VERSION 5.7 ;
BUSBITCHARS "[]" ;
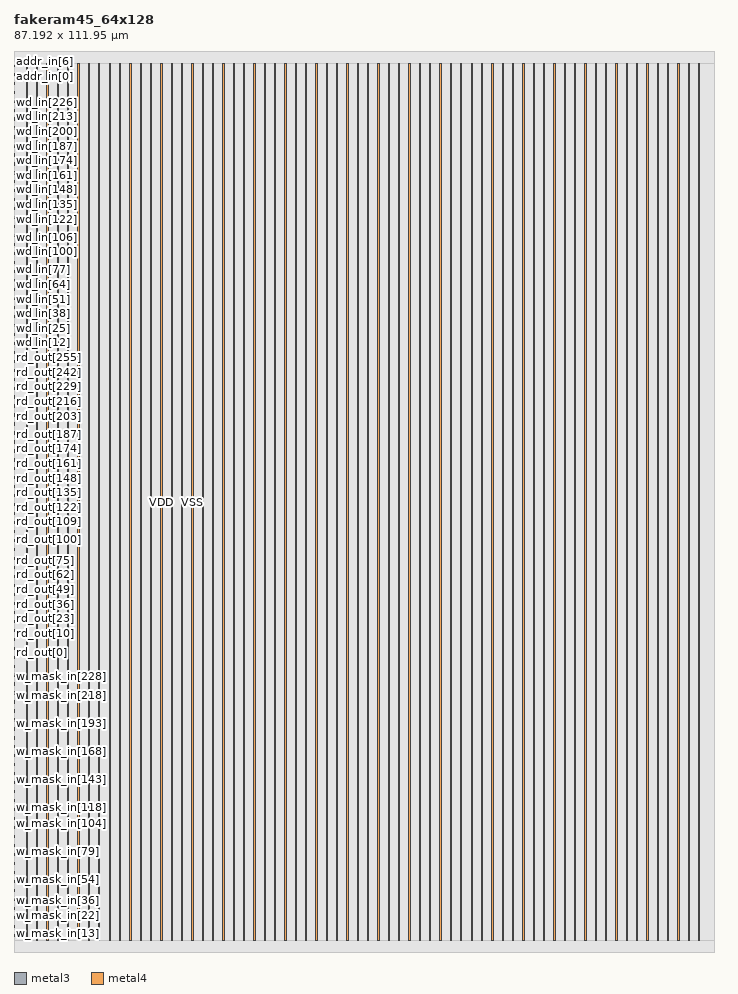
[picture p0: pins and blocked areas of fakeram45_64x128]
MACRO fakeram45_64x128
  FOREIGN fakeram45_64x128 0 0 ;
  SYMMETRY X Y R90 ;
  SIZE 87.192 BY 111.950 ;
  CLASS BLOCK ;
  PIN w_mask_in[0]
    DIRECTION INPUT ;
    USE SIGNAL ;
    SHAPE ABUTMENT ;
    PORT
      LAYER metal3 ;
      RECT 0.000 1.400 0.040 1.435 ;
    END
  END w_mask_in[0]
  PIN w_mask_in[1]
    DIRECTION INPUT ;
    USE SIGNAL ;
    SHAPE ABUTMENT ;
    PORT
      LAYER metal3 ;
      RECT 0.000 1.540 0.040 1.575 ;
    END
  END w_mask_in[1]
  PIN w_mask_in[2]
    DIRECTION INPUT ;
    USE SIGNAL ;
    SHAPE ABUTMENT ;
    PORT
      LAYER metal3 ;
      RECT 0.000 1.680 0.040 1.715 ;
    END
  END w_mask_in[2]
  PIN w_mask_in[3]
    DIRECTION INPUT ;
    USE SIGNAL ;
    SHAPE ABUTMENT ;
    PORT
      LAYER metal3 ;
      RECT 0.000 1.820 0.040 1.855 ;
    END
  END w_mask_in[3]
  PIN w_mask_in[4]
    DIRECTION INPUT ;
    USE SIGNAL ;
    SHAPE ABUTMENT ;
    PORT
      LAYER metal3 ;
      RECT 0.000 1.960 0.040 1.995 ;
    END
  END w_mask_in[4]
  PIN w_mask_in[5]
    DIRECTION INPUT ;
    USE SIGNAL ;
    SHAPE ABUTMENT ;
    PORT
      LAYER metal3 ;
      RECT 0.000 2.100 0.040 2.135 ;
    END
  END w_mask_in[5]
  PIN w_mask_in[6]
    DIRECTION INPUT ;
    USE SIGNAL ;
    SHAPE ABUTMENT ;
    PORT
      LAYER metal3 ;
      RECT 0.000 2.240 0.040 2.275 ;
    END
  END w_mask_in[6]
  PIN w_mask_in[7]
    DIRECTION INPUT ;
    USE SIGNAL ;
    SHAPE ABUTMENT ;
    PORT
      LAYER metal3 ;
      RECT 0.000 2.380 0.040 2.415 ;
    END
  END w_mask_in[7]
  PIN w_mask_in[8]
    DIRECTION INPUT ;
    USE SIGNAL ;
    SHAPE ABUTMENT ;
    PORT
      LAYER metal3 ;
      RECT 0.000 2.520 0.040 2.555 ;
    END
  END w_mask_in[8]
  PIN w_mask_in[9]
    DIRECTION INPUT ;
    USE SIGNAL ;
    SHAPE ABUTMENT ;
    PORT
      LAYER metal3 ;
      RECT 0.000 2.660 0.040 2.695 ;
    END
  END w_mask_in[9]
  PIN w_mask_in[10]
    DIRECTION INPUT ;
    USE SIGNAL ;
    SHAPE ABUTMENT ;
    PORT
      LAYER metal3 ;
      RECT 0.000 2.800 0.040 2.835 ;
    END
  END w_mask_in[10]
  PIN w_mask_in[11]
    DIRECTION INPUT ;
    USE SIGNAL ;
    SHAPE ABUTMENT ;
    PORT
      LAYER metal3 ;
      RECT 0.000 2.940 0.040 2.975 ;
    END
  END w_mask_in[11]
  PIN w_mask_in[12]
    DIRECTION INPUT ;
    USE SIGNAL ;
    SHAPE ABUTMENT ;
    PORT
      LAYER metal3 ;
      RECT 0.000 3.080 0.040 3.115 ;
    END
  END w_mask_in[12]
  PIN w_mask_in[13]
    DIRECTION INPUT ;
    USE SIGNAL ;
    SHAPE ABUTMENT ;
    PORT
      LAYER metal3 ;
      RECT 0.000 3.220 0.040 3.255 ;
    END
  END w_mask_in[13]
  PIN w_mask_in[14]
    DIRECTION INPUT ;
    USE SIGNAL ;
    SHAPE ABUTMENT ;
    PORT
      LAYER metal3 ;
      RECT 0.000 3.360 0.040 3.395 ;
    END
  END w_mask_in[14]
  PIN w_mask_in[15]
    DIRECTION INPUT ;
    USE SIGNAL ;
    SHAPE ABUTMENT ;
    PORT
      LAYER metal3 ;
      RECT 0.000 3.500 0.040 3.535 ;
    END
  END w_mask_in[15]
  PIN w_mask_in[16]
    DIRECTION INPUT ;
    USE SIGNAL ;
    SHAPE ABUTMENT ;
    PORT
      LAYER metal3 ;
      RECT 0.000 3.640 0.040 3.675 ;
    END
  END w_mask_in[16]
  PIN w_mask_in[17]
    DIRECTION INPUT ;
    USE SIGNAL ;
    SHAPE ABUTMENT ;
    PORT
      LAYER metal3 ;
      RECT 0.000 3.780 0.040 3.815 ;
    END
  END w_mask_in[17]
  PIN w_mask_in[18]
    DIRECTION INPUT ;
    USE SIGNAL ;
    SHAPE ABUTMENT ;
    PORT
      LAYER metal3 ;
      RECT 0.000 3.920 0.040 3.955 ;
    END
  END w_mask_in[18]
  PIN w_mask_in[19]
    DIRECTION INPUT ;
    USE SIGNAL ;
    SHAPE ABUTMENT ;
    PORT
      LAYER metal3 ;
      RECT 0.000 4.060 0.040 4.095 ;
    END
  END w_mask_in[19]
  PIN w_mask_in[20]
    DIRECTION INPUT ;
    USE SIGNAL ;
    SHAPE ABUTMENT ;
    PORT
      LAYER metal3 ;
      RECT 0.000 4.200 0.040 4.235 ;
    END
  END w_mask_in[20]
  PIN w_mask_in[21]
    DIRECTION INPUT ;
    USE SIGNAL ;
    SHAPE ABUTMENT ;
    PORT
      LAYER metal3 ;
      RECT 0.000 4.340 0.040 4.375 ;
    END
  END w_mask_in[21]
  PIN w_mask_in[22]
    DIRECTION INPUT ;
    USE SIGNAL ;
    SHAPE ABUTMENT ;
    PORT
      LAYER metal3 ;
      RECT 0.000 4.480 0.040 4.515 ;
    END
  END w_mask_in[22]
  PIN w_mask_in[23]
    DIRECTION INPUT ;
    USE SIGNAL ;
    SHAPE ABUTMENT ;
    PORT
      LAYER metal3 ;
      RECT 0.000 4.620 0.040 4.655 ;
    END
  END w_mask_in[23]
  PIN w_mask_in[24]
    DIRECTION INPUT ;
    USE SIGNAL ;
    SHAPE ABUTMENT ;
    PORT
      LAYER metal3 ;
      RECT 0.000 4.760 0.040 4.795 ;
    END
  END w_mask_in[24]
  PIN w_mask_in[25]
    DIRECTION INPUT ;
    USE SIGNAL ;
    SHAPE ABUTMENT ;
    PORT
      LAYER metal3 ;
      RECT 0.000 4.900 0.040 4.935 ;
    END
  END w_mask_in[25]
  PIN w_mask_in[26]
    DIRECTION INPUT ;
    USE SIGNAL ;
    SHAPE ABUTMENT ;
    PORT
      LAYER metal3 ;
      RECT 0.000 5.040 0.040 5.075 ;
    END
  END w_mask_in[26]
  PIN w_mask_in[27]
    DIRECTION INPUT ;
    USE SIGNAL ;
    SHAPE ABUTMENT ;
    PORT
      LAYER metal3 ;
      RECT 0.000 5.180 0.040 5.215 ;
    END
  END w_mask_in[27]
  PIN w_mask_in[28]
    DIRECTION INPUT ;
    USE SIGNAL ;
    SHAPE ABUTMENT ;
    PORT
      LAYER metal3 ;
      RECT 0.000 5.320 0.040 5.355 ;
    END
  END w_mask_in[28]
  PIN w_mask_in[29]
    DIRECTION INPUT ;
    USE SIGNAL ;
    SHAPE ABUTMENT ;
    PORT
      LAYER metal3 ;
      RECT 0.000 5.460 0.040 5.495 ;
    END
  END w_mask_in[29]
  PIN w_mask_in[30]
    DIRECTION INPUT ;
    USE SIGNAL ;
    SHAPE ABUTMENT ;
    PORT
      LAYER metal3 ;
      RECT 0.000 5.600 0.040 5.635 ;
    END
  END w_mask_in[30]
  PIN w_mask_in[31]
    DIRECTION INPUT ;
    USE SIGNAL ;
    SHAPE ABUTMENT ;
    PORT
      LAYER metal3 ;
      RECT 0.000 5.740 0.040 5.775 ;
    END
  END w_mask_in[31]
  PIN w_mask_in[32]
    DIRECTION INPUT ;
    USE SIGNAL ;
    SHAPE ABUTMENT ;
    PORT
      LAYER metal3 ;
      RECT 0.000 5.880 0.040 5.915 ;
    END
  END w_mask_in[32]
  PIN w_mask_in[33]
    DIRECTION INPUT ;
    USE SIGNAL ;
    SHAPE ABUTMENT ;
    PORT
      LAYER metal3 ;
      RECT 0.000 6.020 0.040 6.055 ;
    END
  END w_mask_in[33]
  PIN w_mask_in[34]
    DIRECTION INPUT ;
    USE SIGNAL ;
    SHAPE ABUTMENT ;
    PORT
      LAYER metal3 ;
      RECT 0.000 6.160 0.040 6.195 ;
    END
  END w_mask_in[34]
  PIN w_mask_in[35]
    DIRECTION INPUT ;
    USE SIGNAL ;
    SHAPE ABUTMENT ;
    PORT
      LAYER metal3 ;
      RECT 0.000 6.300 0.040 6.335 ;
    END
  END w_mask_in[35]
  PIN w_mask_in[36]
    DIRECTION INPUT ;
    USE SIGNAL ;
    SHAPE ABUTMENT ;
    PORT
      LAYER metal3 ;
      RECT 0.000 6.440 0.040 6.475 ;
    END
  END w_mask_in[36]
  PIN w_mask_in[37]
    DIRECTION INPUT ;
    USE SIGNAL ;
    SHAPE ABUTMENT ;
    PORT
      LAYER metal3 ;
      RECT 0.000 6.580 0.040 6.615 ;
    END
  END w_mask_in[37]
  PIN w_mask_in[38]
    DIRECTION INPUT ;
    USE SIGNAL ;
    SHAPE ABUTMENT ;
    PORT
      LAYER metal3 ;
      RECT 0.000 6.720 0.040 6.755 ;
    END
  END w_mask_in[38]
  PIN w_mask_in[39]
    DIRECTION INPUT ;
    USE SIGNAL ;
    SHAPE ABUTMENT ;
    PORT
      LAYER metal3 ;
      RECT 0.000 6.860 0.040 6.895 ;
    END
  END w_mask_in[39]
  PIN w_mask_in[40]
    DIRECTION INPUT ;
    USE SIGNAL ;
    SHAPE ABUTMENT ;
    PORT
      LAYER metal3 ;
      RECT 0.000 7.000 0.040 7.035 ;
    END
  END w_mask_in[40]
  PIN w_mask_in[41]
    DIRECTION INPUT ;
    USE SIGNAL ;
    SHAPE ABUTMENT ;
    PORT
      LAYER metal3 ;
      RECT 0.000 7.140 0.040 7.175 ;
    END
  END w_mask_in[41]
  PIN w_mask_in[42]
    DIRECTION INPUT ;
    USE SIGNAL ;
    SHAPE ABUTMENT ;
    PORT
      LAYER metal3 ;
      RECT 0.000 7.280 0.040 7.315 ;
    END
  END w_mask_in[42]
  PIN w_mask_in[43]
    DIRECTION INPUT ;
    USE SIGNAL ;
    SHAPE ABUTMENT ;
    PORT
      LAYER metal3 ;
      RECT 0.000 7.420 0.040 7.455 ;
    END
  END w_mask_in[43]
  PIN w_mask_in[44]
    DIRECTION INPUT ;
    USE SIGNAL ;
    SHAPE ABUTMENT ;
    PORT
      LAYER metal3 ;
      RECT 0.000 7.560 0.040 7.595 ;
    END
  END w_mask_in[44]
  PIN w_mask_in[45]
    DIRECTION INPUT ;
    USE SIGNAL ;
    SHAPE ABUTMENT ;
    PORT
      LAYER metal3 ;
      RECT 0.000 7.700 0.040 7.735 ;
    END
  END w_mask_in[45]
  PIN w_mask_in[46]
    DIRECTION INPUT ;
    USE SIGNAL ;
    SHAPE ABUTMENT ;
    PORT
      LAYER metal3 ;
      RECT 0.000 7.840 0.040 7.875 ;
    END
  END w_mask_in[46]
  PIN w_mask_in[47]
    DIRECTION INPUT ;
    USE SIGNAL ;
    SHAPE ABUTMENT ;
    PORT
      LAYER metal3 ;
      RECT 0.000 7.980 0.040 8.015 ;
    END
  END w_mask_in[47]
  PIN w_mask_in[48]
    DIRECTION INPUT ;
    USE SIGNAL ;
    SHAPE ABUTMENT ;
    PORT
      LAYER metal3 ;
      RECT 0.000 8.120 0.040 8.155 ;
    END
  END w_mask_in[48]
  PIN w_mask_in[49]
    DIRECTION INPUT ;
    USE SIGNAL ;
    SHAPE ABUTMENT ;
    PORT
      LAYER metal3 ;
      RECT 0.000 8.260 0.040 8.295 ;
    END
  END w_mask_in[49]
  PIN w_mask_in[50]
    DIRECTION INPUT ;
    USE SIGNAL ;
    SHAPE ABUTMENT ;
    PORT
      LAYER metal3 ;
      RECT 0.000 8.400 0.040 8.435 ;
    END
  END w_mask_in[50]
  PIN w_mask_in[51]
    DIRECTION INPUT ;
    USE SIGNAL ;
    SHAPE ABUTMENT ;
    PORT
      LAYER metal3 ;
      RECT 0.000 8.540 0.040 8.575 ;
    END
  END w_mask_in[51]
  PIN w_mask_in[52]
    DIRECTION INPUT ;
    USE SIGNAL ;
    SHAPE ABUTMENT ;
    PORT
      LAYER metal3 ;
      RECT 0.000 8.680 0.040 8.715 ;
    END
  END w_mask_in[52]
  PIN w_mask_in[53]
    DIRECTION INPUT ;
    USE SIGNAL ;
    SHAPE ABUTMENT ;
    PORT
      LAYER metal3 ;
      RECT 0.000 8.820 0.040 8.855 ;
    END
  END w_mask_in[53]
  PIN w_mask_in[54]
    DIRECTION INPUT ;
    USE SIGNAL ;
    SHAPE ABUTMENT ;
    PORT
      LAYER metal3 ;
      RECT 0.000 8.960 0.040 8.995 ;
    END
  END w_mask_in[54]
  PIN w_mask_in[55]
    DIRECTION INPUT ;
    USE SIGNAL ;
    SHAPE ABUTMENT ;
    PORT
      LAYER metal3 ;
      RECT 0.000 9.100 0.040 9.135 ;
    END
  END w_mask_in[55]
  PIN w_mask_in[56]
    DIRECTION INPUT ;
    USE SIGNAL ;
    SHAPE ABUTMENT ;
    PORT
      LAYER metal3 ;
      RECT 0.000 9.240 0.040 9.275 ;
    END
  END w_mask_in[56]
  PIN w_mask_in[57]
    DIRECTION INPUT ;
    USE SIGNAL ;
    SHAPE ABUTMENT ;
    PORT
      LAYER metal3 ;
      RECT 0.000 9.380 0.040 9.415 ;
    END
  END w_mask_in[57]
  PIN w_mask_in[58]
    DIRECTION INPUT ;
    USE SIGNAL ;
    SHAPE ABUTMENT ;
    PORT
      LAYER metal3 ;
      RECT 0.000 9.520 0.040 9.555 ;
    END
  END w_mask_in[58]
  PIN w_mask_in[59]
    DIRECTION INPUT ;
    USE SIGNAL ;
    SHAPE ABUTMENT ;
    PORT
      LAYER metal3 ;
      RECT 0.000 9.660 0.040 9.695 ;
    END
  END w_mask_in[59]
  PIN w_mask_in[60]
    DIRECTION INPUT ;
    USE SIGNAL ;
    SHAPE ABUTMENT ;
    PORT
      LAYER metal3 ;
      RECT 0.000 9.800 0.040 9.835 ;
    END
  END w_mask_in[60]
  PIN w_mask_in[61]
    DIRECTION INPUT ;
    USE SIGNAL ;
    SHAPE ABUTMENT ;
    PORT
      LAYER metal3 ;
      RECT 0.000 9.940 0.040 9.975 ;
    END
  END w_mask_in[61]
  PIN w_mask_in[62]
    DIRECTION INPUT ;
    USE SIGNAL ;
    SHAPE ABUTMENT ;
    PORT
      LAYER metal3 ;
      RECT 0.000 10.080 0.040 10.115 ;
    END
  END w_mask_in[62]
  PIN w_mask_in[63]
    DIRECTION INPUT ;
    USE SIGNAL ;
    SHAPE ABUTMENT ;
    PORT
      LAYER metal3 ;
      RECT 0.000 10.220 0.040 10.255 ;
    END
  END w_mask_in[63]
  PIN w_mask_in[64]
    DIRECTION INPUT ;
    USE SIGNAL ;
    SHAPE ABUTMENT ;
    PORT
      LAYER metal3 ;
      RECT 0.000 10.360 0.040 10.395 ;
    END
  END w_mask_in[64]
  PIN w_mask_in[65]
    DIRECTION INPUT ;
    USE SIGNAL ;
    SHAPE ABUTMENT ;
    PORT
      LAYER metal3 ;
      RECT 0.000 10.500 0.040 10.535 ;
    END
  END w_mask_in[65]
  PIN w_mask_in[66]
    DIRECTION INPUT ;
    USE SIGNAL ;
    SHAPE ABUTMENT ;
    PORT
      LAYER metal3 ;
      RECT 0.000 10.640 0.040 10.675 ;
    END
  END w_mask_in[66]
  PIN w_mask_in[67]
    DIRECTION INPUT ;
    USE SIGNAL ;
    SHAPE ABUTMENT ;
    PORT
      LAYER metal3 ;
      RECT 0.000 10.780 0.040 10.815 ;
    END
  END w_mask_in[67]
  PIN w_mask_in[68]
    DIRECTION INPUT ;
    USE SIGNAL ;
    SHAPE ABUTMENT ;
    PORT
      LAYER metal3 ;
      RECT 0.000 10.920 0.040 10.955 ;
    END
  END w_mask_in[68]
  PIN w_mask_in[69]
    DIRECTION INPUT ;
    USE SIGNAL ;
    SHAPE ABUTMENT ;
    PORT
      LAYER metal3 ;
      RECT 0.000 11.060 0.040 11.095 ;
    END
  END w_mask_in[69]
  PIN w_mask_in[70]
    DIRECTION INPUT ;
    USE SIGNAL ;
    SHAPE ABUTMENT ;
    PORT
      LAYER metal3 ;
      RECT 0.000 11.200 0.040 11.235 ;
    END
  END w_mask_in[70]
  PIN w_mask_in[71]
    DIRECTION INPUT ;
    USE SIGNAL ;
    SHAPE ABUTMENT ;
    PORT
      LAYER metal3 ;
      RECT 0.000 11.340 0.040 11.375 ;
    END
  END w_mask_in[71]
  PIN w_mask_in[72]
    DIRECTION INPUT ;
    USE SIGNAL ;
    SHAPE ABUTMENT ;
    PORT
      LAYER metal3 ;
      RECT 0.000 11.480 0.040 11.515 ;
    END
  END w_mask_in[72]
  PIN w_mask_in[73]
    DIRECTION INPUT ;
    USE SIGNAL ;
    SHAPE ABUTMENT ;
    PORT
      LAYER metal3 ;
      RECT 0.000 11.620 0.040 11.655 ;
    END
  END w_mask_in[73]
  PIN w_mask_in[74]
    DIRECTION INPUT ;
    USE SIGNAL ;
    SHAPE ABUTMENT ;
    PORT
      LAYER metal3 ;
      RECT 0.000 11.760 0.040 11.795 ;
    END
  END w_mask_in[74]
  PIN w_mask_in[75]
    DIRECTION INPUT ;
    USE SIGNAL ;
    SHAPE ABUTMENT ;
    PORT
      LAYER metal3 ;
      RECT 0.000 11.900 0.040 11.935 ;
    END
  END w_mask_in[75]
  PIN w_mask_in[76]
    DIRECTION INPUT ;
    USE SIGNAL ;
    SHAPE ABUTMENT ;
    PORT
      LAYER metal3 ;
      RECT 0.000 12.040 0.040 12.075 ;
    END
  END w_mask_in[76]
  PIN w_mask_in[77]
    DIRECTION INPUT ;
    USE SIGNAL ;
    SHAPE ABUTMENT ;
    PORT
      LAYER metal3 ;
      RECT 0.000 12.180 0.040 12.215 ;
    END
  END w_mask_in[77]
  PIN w_mask_in[78]
    DIRECTION INPUT ;
    USE SIGNAL ;
    SHAPE ABUTMENT ;
    PORT
      LAYER metal3 ;
      RECT 0.000 12.320 0.040 12.355 ;
    END
  END w_mask_in[78]
  PIN w_mask_in[79]
    DIRECTION INPUT ;
    USE SIGNAL ;
    SHAPE ABUTMENT ;
    PORT
      LAYER metal3 ;
      RECT 0.000 12.460 0.040 12.495 ;
    END
  END w_mask_in[79]
  PIN w_mask_in[80]
    DIRECTION INPUT ;
    USE SIGNAL ;
    SHAPE ABUTMENT ;
    PORT
      LAYER metal3 ;
      RECT 0.000 12.600 0.040 12.635 ;
    END
  END w_mask_in[80]
  PIN w_mask_in[81]
    DIRECTION INPUT ;
    USE SIGNAL ;
    SHAPE ABUTMENT ;
    PORT
      LAYER metal3 ;
      RECT 0.000 12.740 0.040 12.775 ;
    END
  END w_mask_in[81]
  PIN w_mask_in[82]
    DIRECTION INPUT ;
    USE SIGNAL ;
    SHAPE ABUTMENT ;
    PORT
      LAYER metal3 ;
      RECT 0.000 12.880 0.040 12.915 ;
    END
  END w_mask_in[82]
  PIN w_mask_in[83]
    DIRECTION INPUT ;
    USE SIGNAL ;
    SHAPE ABUTMENT ;
    PORT
      LAYER metal3 ;
      RECT 0.000 13.020 0.040 13.055 ;
    END
  END w_mask_in[83]
  PIN w_mask_in[84]
    DIRECTION INPUT ;
    USE SIGNAL ;
    SHAPE ABUTMENT ;
    PORT
      LAYER metal3 ;
      RECT 0.000 13.160 0.040 13.195 ;
    END
  END w_mask_in[84]
  PIN w_mask_in[85]
    DIRECTION INPUT ;
    USE SIGNAL ;
    SHAPE ABUTMENT ;
    PORT
      LAYER metal3 ;
      RECT 0.000 13.300 0.040 13.335 ;
    END
  END w_mask_in[85]
  PIN w_mask_in[86]
    DIRECTION INPUT ;
    USE SIGNAL ;
    SHAPE ABUTMENT ;
    PORT
      LAYER metal3 ;
      RECT 0.000 13.440 0.040 13.475 ;
    END
  END w_mask_in[86]
  PIN w_mask_in[87]
    DIRECTION INPUT ;
    USE SIGNAL ;
    SHAPE ABUTMENT ;
    PORT
      LAYER metal3 ;
      RECT 0.000 13.580 0.040 13.615 ;
    END
  END w_mask_in[87]
  PIN w_mask_in[88]
    DIRECTION INPUT ;
    USE SIGNAL ;
    SHAPE ABUTMENT ;
    PORT
      LAYER metal3 ;
      RECT 0.000 13.720 0.040 13.755 ;
    END
  END w_mask_in[88]
  PIN w_mask_in[89]
    DIRECTION INPUT ;
    USE SIGNAL ;
    SHAPE ABUTMENT ;
    PORT
      LAYER metal3 ;
      RECT 0.000 13.860 0.040 13.895 ;
    END
  END w_mask_in[89]
  PIN w_mask_in[90]
    DIRECTION INPUT ;
    USE SIGNAL ;
    SHAPE ABUTMENT ;
    PORT
      LAYER metal3 ;
      RECT 0.000 14.000 0.040 14.035 ;
    END
  END w_mask_in[90]
  PIN w_mask_in[91]
    DIRECTION INPUT ;
    USE SIGNAL ;
    SHAPE ABUTMENT ;
    PORT
      LAYER metal3 ;
      RECT 0.000 14.140 0.040 14.175 ;
    END
  END w_mask_in[91]
  PIN w_mask_in[92]
    DIRECTION INPUT ;
    USE SIGNAL ;
    SHAPE ABUTMENT ;
    PORT
      LAYER metal3 ;
      RECT 0.000 14.280 0.040 14.315 ;
    END
  END w_mask_in[92]
  PIN w_mask_in[93]
    DIRECTION INPUT ;
    USE SIGNAL ;
    SHAPE ABUTMENT ;
    PORT
      LAYER metal3 ;
      RECT 0.000 14.420 0.040 14.455 ;
    END
  END w_mask_in[93]
  PIN w_mask_in[94]
    DIRECTION INPUT ;
    USE SIGNAL ;
    SHAPE ABUTMENT ;
    PORT
      LAYER metal3 ;
      RECT 0.000 14.560 0.040 14.595 ;
    END
  END w_mask_in[94]
  PIN w_mask_in[95]
    DIRECTION INPUT ;
    USE SIGNAL ;
    SHAPE ABUTMENT ;
    PORT
      LAYER metal3 ;
      RECT 0.000 14.700 0.040 14.735 ;
    END
  END w_mask_in[95]
  PIN w_mask_in[96]
    DIRECTION INPUT ;
    USE SIGNAL ;
    SHAPE ABUTMENT ;
    PORT
      LAYER metal3 ;
      RECT 0.000 14.840 0.040 14.875 ;
    END
  END w_mask_in[96]
  PIN w_mask_in[97]
    DIRECTION INPUT ;
    USE SIGNAL ;
    SHAPE ABUTMENT ;
    PORT
      LAYER metal3 ;
      RECT 0.000 14.980 0.040 15.015 ;
    END
  END w_mask_in[97]
  PIN w_mask_in[98]
    DIRECTION INPUT ;
    USE SIGNAL ;
    SHAPE ABUTMENT ;
    PORT
      LAYER metal3 ;
      RECT 0.000 15.120 0.040 15.155 ;
    END
  END w_mask_in[98]
  PIN w_mask_in[99]
    DIRECTION INPUT ;
    USE SIGNAL ;
    SHAPE ABUTMENT ;
    PORT
      LAYER metal3 ;
      RECT 0.000 15.260 0.040 15.295 ;
    END
  END w_mask_in[99]
  PIN w_mask_in[100]
    DIRECTION INPUT ;
    USE SIGNAL ;
    SHAPE ABUTMENT ;
    PORT
      LAYER metal3 ;
      RECT 0.000 15.400 0.040 15.435 ;
    END
  END w_mask_in[100]
  PIN w_mask_in[101]
    DIRECTION INPUT ;
    USE SIGNAL ;
    SHAPE ABUTMENT ;
    PORT
      LAYER metal3 ;
      RECT 0.000 15.540 0.040 15.575 ;
    END
  END w_mask_in[101]
  PIN w_mask_in[102]
    DIRECTION INPUT ;
    USE SIGNAL ;
    SHAPE ABUTMENT ;
    PORT
      LAYER metal3 ;
      RECT 0.000 15.680 0.040 15.715 ;
    END
  END w_mask_in[102]
  PIN w_mask_in[103]
    DIRECTION INPUT ;
    USE SIGNAL ;
    SHAPE ABUTMENT ;
    PORT
      LAYER metal3 ;
      RECT 0.000 15.820 0.040 15.855 ;
    END
  END w_mask_in[103]
  PIN w_mask_in[104]
    DIRECTION INPUT ;
    USE SIGNAL ;
    SHAPE ABUTMENT ;
    PORT
      LAYER metal3 ;
      RECT 0.000 15.960 0.040 15.995 ;
    END
  END w_mask_in[104]
  PIN w_mask_in[105]
    DIRECTION INPUT ;
    USE SIGNAL ;
    SHAPE ABUTMENT ;
    PORT
      LAYER metal3 ;
      RECT 0.000 16.100 0.040 16.135 ;
    END
  END w_mask_in[105]
  PIN w_mask_in[106]
    DIRECTION INPUT ;
    USE SIGNAL ;
    SHAPE ABUTMENT ;
    PORT
      LAYER metal3 ;
      RECT 0.000 16.240 0.040 16.275 ;
    END
  END w_mask_in[106]
  PIN w_mask_in[107]
    DIRECTION INPUT ;
    USE SIGNAL ;
    SHAPE ABUTMENT ;
    PORT
      LAYER metal3 ;
      RECT 0.000 16.380 0.040 16.415 ;
    END
  END w_mask_in[107]
  PIN w_mask_in[108]
    DIRECTION INPUT ;
    USE SIGNAL ;
    SHAPE ABUTMENT ;
    PORT
      LAYER metal3 ;
      RECT 0.000 16.520 0.040 16.555 ;
    END
  END w_mask_in[108]
  PIN w_mask_in[109]
    DIRECTION INPUT ;
    USE SIGNAL ;
    SHAPE ABUTMENT ;
    PORT
      LAYER metal3 ;
      RECT 0.000 16.660 0.040 16.695 ;
    END
  END w_mask_in[109]
  PIN w_mask_in[110]
    DIRECTION INPUT ;
    USE SIGNAL ;
    SHAPE ABUTMENT ;
    PORT
      LAYER metal3 ;
      RECT 0.000 16.800 0.040 16.835 ;
    END
  END w_mask_in[110]
  PIN w_mask_in[111]
    DIRECTION INPUT ;
    USE SIGNAL ;
    SHAPE ABUTMENT ;
    PORT
      LAYER metal3 ;
      RECT 0.000 16.940 0.040 16.975 ;
    END
  END w_mask_in[111]
  PIN w_mask_in[112]
    DIRECTION INPUT ;
    USE SIGNAL ;
    SHAPE ABUTMENT ;
    PORT
      LAYER metal3 ;
      RECT 0.000 17.080 0.040 17.115 ;
    END
  END w_mask_in[112]
  PIN w_mask_in[113]
    DIRECTION INPUT ;
    USE SIGNAL ;
    SHAPE ABUTMENT ;
    PORT
      LAYER metal3 ;
      RECT 0.000 17.220 0.040 17.255 ;
    END
  END w_mask_in[113]
  PIN w_mask_in[114]
    DIRECTION INPUT ;
    USE SIGNAL ;
    SHAPE ABUTMENT ;
    PORT
      LAYER metal3 ;
      RECT 0.000 17.360 0.040 17.395 ;
    END
  END w_mask_in[114]
  PIN w_mask_in[115]
    DIRECTION INPUT ;
    USE SIGNAL ;
    SHAPE ABUTMENT ;
    PORT
      LAYER metal3 ;
      RECT 0.000 17.500 0.040 17.535 ;
    END
  END w_mask_in[115]
  PIN w_mask_in[116]
    DIRECTION INPUT ;
    USE SIGNAL ;
    SHAPE ABUTMENT ;
    PORT
      LAYER metal3 ;
      RECT 0.000 17.640 0.040 17.675 ;
    END
  END w_mask_in[116]
  PIN w_mask_in[117]
    DIRECTION INPUT ;
    USE SIGNAL ;
    SHAPE ABUTMENT ;
    PORT
      LAYER metal3 ;
      RECT 0.000 17.780 0.040 17.815 ;
    END
  END w_mask_in[117]
  PIN w_mask_in[118]
    DIRECTION INPUT ;
    USE SIGNAL ;
    SHAPE ABUTMENT ;
    PORT
      LAYER metal3 ;
      RECT 0.000 17.920 0.040 17.955 ;
    END
  END w_mask_in[118]
  PIN w_mask_in[119]
    DIRECTION INPUT ;
    USE SIGNAL ;
    SHAPE ABUTMENT ;
    PORT
      LAYER metal3 ;
      RECT 0.000 18.060 0.040 18.095 ;
    END
  END w_mask_in[119]
  PIN w_mask_in[120]
    DIRECTION INPUT ;
    USE SIGNAL ;
    SHAPE ABUTMENT ;
    PORT
      LAYER metal3 ;
      RECT 0.000 18.200 0.040 18.235 ;
    END
  END w_mask_in[120]
  PIN w_mask_in[121]
    DIRECTION INPUT ;
    USE SIGNAL ;
    SHAPE ABUTMENT ;
    PORT
      LAYER metal3 ;
      RECT 0.000 18.340 0.040 18.375 ;
    END
  END w_mask_in[121]
  PIN w_mask_in[122]
    DIRECTION INPUT ;
    USE SIGNAL ;
    SHAPE ABUTMENT ;
    PORT
      LAYER metal3 ;
      RECT 0.000 18.480 0.040 18.515 ;
    END
  END w_mask_in[122]
  PIN w_mask_in[123]
    DIRECTION INPUT ;
    USE SIGNAL ;
    SHAPE ABUTMENT ;
    PORT
      LAYER metal3 ;
      RECT 0.000 18.620 0.040 18.655 ;
    END
  END w_mask_in[123]
  PIN w_mask_in[124]
    DIRECTION INPUT ;
    USE SIGNAL ;
    SHAPE ABUTMENT ;
    PORT
      LAYER metal3 ;
      RECT 0.000 18.760 0.040 18.795 ;
    END
  END w_mask_in[124]
  PIN w_mask_in[125]
    DIRECTION INPUT ;
    USE SIGNAL ;
    SHAPE ABUTMENT ;
    PORT
      LAYER metal3 ;
      RECT 0.000 18.900 0.040 18.935 ;
    END
  END w_mask_in[125]
  PIN w_mask_in[126]
    DIRECTION INPUT ;
    USE SIGNAL ;
    SHAPE ABUTMENT ;
    PORT
      LAYER metal3 ;
      RECT 0.000 19.040 0.040 19.075 ;
    END
  END w_mask_in[126]
  PIN w_mask_in[127]
    DIRECTION INPUT ;
    USE SIGNAL ;
    SHAPE ABUTMENT ;
    PORT
      LAYER metal3 ;
      RECT 0.000 19.180 0.040 19.215 ;
    END
  END w_mask_in[127]
  PIN w_mask_in[128]
    DIRECTION INPUT ;
    USE SIGNAL ;
    SHAPE ABUTMENT ;
    PORT
      LAYER metal3 ;
      RECT 0.000 19.320 0.040 19.355 ;
    END
  END w_mask_in[128]
  PIN w_mask_in[129]
    DIRECTION INPUT ;
    USE SIGNAL ;
    SHAPE ABUTMENT ;
    PORT
      LAYER metal3 ;
      RECT 0.000 19.460 0.040 19.495 ;
    END
  END w_mask_in[129]
  PIN w_mask_in[130]
    DIRECTION INPUT ;
    USE SIGNAL ;
    SHAPE ABUTMENT ;
    PORT
      LAYER metal3 ;
      RECT 0.000 19.600 0.040 19.635 ;
    END
  END w_mask_in[130]
  PIN w_mask_in[131]
    DIRECTION INPUT ;
    USE SIGNAL ;
    SHAPE ABUTMENT ;
    PORT
      LAYER metal3 ;
      RECT 0.000 19.740 0.040 19.775 ;
    END
  END w_mask_in[131]
  PIN w_mask_in[132]
    DIRECTION INPUT ;
    USE SIGNAL ;
    SHAPE ABUTMENT ;
    PORT
      LAYER metal3 ;
      RECT 0.000 19.880 0.040 19.915 ;
    END
  END w_mask_in[132]
  PIN w_mask_in[133]
    DIRECTION INPUT ;
    USE SIGNAL ;
    SHAPE ABUTMENT ;
    PORT
      LAYER metal3 ;
      RECT 0.000 20.020 0.040 20.055 ;
    END
  END w_mask_in[133]
  PIN w_mask_in[134]
    DIRECTION INPUT ;
    USE SIGNAL ;
    SHAPE ABUTMENT ;
    PORT
      LAYER metal3 ;
      RECT 0.000 20.160 0.040 20.195 ;
    END
  END w_mask_in[134]
  PIN w_mask_in[135]
    DIRECTION INPUT ;
    USE SIGNAL ;
    SHAPE ABUTMENT ;
    PORT
      LAYER metal3 ;
      RECT 0.000 20.300 0.040 20.335 ;
    END
  END w_mask_in[135]
  PIN w_mask_in[136]
    DIRECTION INPUT ;
    USE SIGNAL ;
    SHAPE ABUTMENT ;
    PORT
      LAYER metal3 ;
      RECT 0.000 20.440 0.040 20.475 ;
    END
  END w_mask_in[136]
  PIN w_mask_in[137]
    DIRECTION INPUT ;
    USE SIGNAL ;
    SHAPE ABUTMENT ;
    PORT
      LAYER metal3 ;
      RECT 0.000 20.580 0.040 20.615 ;
    END
  END w_mask_in[137]
  PIN w_mask_in[138]
    DIRECTION INPUT ;
    USE SIGNAL ;
    SHAPE ABUTMENT ;
    PORT
      LAYER metal3 ;
      RECT 0.000 20.720 0.040 20.755 ;
    END
  END w_mask_in[138]
  PIN w_mask_in[139]
    DIRECTION INPUT ;
    USE SIGNAL ;
    SHAPE ABUTMENT ;
    PORT
      LAYER metal3 ;
      RECT 0.000 20.860 0.040 20.895 ;
    END
  END w_mask_in[139]
  PIN w_mask_in[140]
    DIRECTION INPUT ;
    USE SIGNAL ;
    SHAPE ABUTMENT ;
    PORT
      LAYER metal3 ;
      RECT 0.000 21.000 0.040 21.035 ;
    END
  END w_mask_in[140]
  PIN w_mask_in[141]
    DIRECTION INPUT ;
    USE SIGNAL ;
    SHAPE ABUTMENT ;
    PORT
      LAYER metal3 ;
      RECT 0.000 21.140 0.040 21.175 ;
    END
  END w_mask_in[141]
  PIN w_mask_in[142]
    DIRECTION INPUT ;
    USE SIGNAL ;
    SHAPE ABUTMENT ;
    PORT
      LAYER metal3 ;
      RECT 0.000 21.280 0.040 21.315 ;
    END
  END w_mask_in[142]
  PIN w_mask_in[143]
    DIRECTION INPUT ;
    USE SIGNAL ;
    SHAPE ABUTMENT ;
    PORT
      LAYER metal3 ;
      RECT 0.000 21.420 0.040 21.455 ;
    END
  END w_mask_in[143]
  PIN w_mask_in[144]
    DIRECTION INPUT ;
    USE SIGNAL ;
    SHAPE ABUTMENT ;
    PORT
      LAYER metal3 ;
      RECT 0.000 21.560 0.040 21.595 ;
    END
  END w_mask_in[144]
  PIN w_mask_in[145]
    DIRECTION INPUT ;
    USE SIGNAL ;
    SHAPE ABUTMENT ;
    PORT
      LAYER metal3 ;
      RECT 0.000 21.700 0.040 21.735 ;
    END
  END w_mask_in[145]
  PIN w_mask_in[146]
    DIRECTION INPUT ;
    USE SIGNAL ;
    SHAPE ABUTMENT ;
    PORT
      LAYER metal3 ;
      RECT 0.000 21.840 0.040 21.875 ;
    END
  END w_mask_in[146]
  PIN w_mask_in[147]
    DIRECTION INPUT ;
    USE SIGNAL ;
    SHAPE ABUTMENT ;
    PORT
      LAYER metal3 ;
      RECT 0.000 21.980 0.040 22.015 ;
    END
  END w_mask_in[147]
  PIN w_mask_in[148]
    DIRECTION INPUT ;
    USE SIGNAL ;
    SHAPE ABUTMENT ;
    PORT
      LAYER metal3 ;
      RECT 0.000 22.120 0.040 22.155 ;
    END
  END w_mask_in[148]
  PIN w_mask_in[149]
    DIRECTION INPUT ;
    USE SIGNAL ;
    SHAPE ABUTMENT ;
    PORT
      LAYER metal3 ;
      RECT 0.000 22.260 0.040 22.295 ;
    END
  END w_mask_in[149]
  PIN w_mask_in[150]
    DIRECTION INPUT ;
    USE SIGNAL ;
    SHAPE ABUTMENT ;
    PORT
      LAYER metal3 ;
      RECT 0.000 22.400 0.040 22.435 ;
    END
  END w_mask_in[150]
  PIN w_mask_in[151]
    DIRECTION INPUT ;
    USE SIGNAL ;
    SHAPE ABUTMENT ;
    PORT
      LAYER metal3 ;
      RECT 0.000 22.540 0.040 22.575 ;
    END
  END w_mask_in[151]
  PIN w_mask_in[152]
    DIRECTION INPUT ;
    USE SIGNAL ;
    SHAPE ABUTMENT ;
    PORT
      LAYER metal3 ;
      RECT 0.000 22.680 0.040 22.715 ;
    END
  END w_mask_in[152]
  PIN w_mask_in[153]
    DIRECTION INPUT ;
    USE SIGNAL ;
    SHAPE ABUTMENT ;
    PORT
      LAYER metal3 ;
      RECT 0.000 22.820 0.040 22.855 ;
    END
  END w_mask_in[153]
  PIN w_mask_in[154]
    DIRECTION INPUT ;
    USE SIGNAL ;
    SHAPE ABUTMENT ;
    PORT
      LAYER metal3 ;
      RECT 0.000 22.960 0.040 22.995 ;
    END
  END w_mask_in[154]
  PIN w_mask_in[155]
    DIRECTION INPUT ;
    USE SIGNAL ;
    SHAPE ABUTMENT ;
    PORT
      LAYER metal3 ;
      RECT 0.000 23.100 0.040 23.135 ;
    END
  END w_mask_in[155]
  PIN w_mask_in[156]
    DIRECTION INPUT ;
    USE SIGNAL ;
    SHAPE ABUTMENT ;
    PORT
      LAYER metal3 ;
      RECT 0.000 23.240 0.040 23.275 ;
    END
  END w_mask_in[156]
  PIN w_mask_in[157]
    DIRECTION INPUT ;
    USE SIGNAL ;
    SHAPE ABUTMENT ;
    PORT
      LAYER metal3 ;
      RECT 0.000 23.380 0.040 23.415 ;
    END
  END w_mask_in[157]
  PIN w_mask_in[158]
    DIRECTION INPUT ;
    USE SIGNAL ;
    SHAPE ABUTMENT ;
    PORT
      LAYER metal3 ;
      RECT 0.000 23.520 0.040 23.555 ;
    END
  END w_mask_in[158]
  PIN w_mask_in[159]
    DIRECTION INPUT ;
    USE SIGNAL ;
    SHAPE ABUTMENT ;
    PORT
      LAYER metal3 ;
      RECT 0.000 23.660 0.040 23.695 ;
    END
  END w_mask_in[159]
  PIN w_mask_in[160]
    DIRECTION INPUT ;
    USE SIGNAL ;
    SHAPE ABUTMENT ;
    PORT
      LAYER metal3 ;
      RECT 0.000 23.800 0.040 23.835 ;
    END
  END w_mask_in[160]
  PIN w_mask_in[161]
    DIRECTION INPUT ;
    USE SIGNAL ;
    SHAPE ABUTMENT ;
    PORT
      LAYER metal3 ;
      RECT 0.000 23.940 0.040 23.975 ;
    END
  END w_mask_in[161]
  PIN w_mask_in[162]
    DIRECTION INPUT ;
    USE SIGNAL ;
    SHAPE ABUTMENT ;
    PORT
      LAYER metal3 ;
      RECT 0.000 24.080 0.040 24.115 ;
    END
  END w_mask_in[162]
  PIN w_mask_in[163]
    DIRECTION INPUT ;
    USE SIGNAL ;
    SHAPE ABUTMENT ;
    PORT
      LAYER metal3 ;
      RECT 0.000 24.220 0.040 24.255 ;
    END
  END w_mask_in[163]
  PIN w_mask_in[164]
    DIRECTION INPUT ;
    USE SIGNAL ;
    SHAPE ABUTMENT ;
    PORT
      LAYER metal3 ;
      RECT 0.000 24.360 0.040 24.395 ;
    END
  END w_mask_in[164]
  PIN w_mask_in[165]
    DIRECTION INPUT ;
    USE SIGNAL ;
    SHAPE ABUTMENT ;
    PORT
      LAYER metal3 ;
      RECT 0.000 24.500 0.040 24.535 ;
    END
  END w_mask_in[165]
  PIN w_mask_in[166]
    DIRECTION INPUT ;
    USE SIGNAL ;
    SHAPE ABUTMENT ;
    PORT
      LAYER metal3 ;
      RECT 0.000 24.640 0.040 24.675 ;
    END
  END w_mask_in[166]
  PIN w_mask_in[167]
    DIRECTION INPUT ;
    USE SIGNAL ;
    SHAPE ABUTMENT ;
    PORT
      LAYER metal3 ;
      RECT 0.000 24.780 0.040 24.815 ;
    END
  END w_mask_in[167]
  PIN w_mask_in[168]
    DIRECTION INPUT ;
    USE SIGNAL ;
    SHAPE ABUTMENT ;
    PORT
      LAYER metal3 ;
      RECT 0.000 24.920 0.040 24.955 ;
    END
  END w_mask_in[168]
  PIN w_mask_in[169]
    DIRECTION INPUT ;
    USE SIGNAL ;
    SHAPE ABUTMENT ;
    PORT
      LAYER metal3 ;
      RECT 0.000 25.060 0.040 25.095 ;
    END
  END w_mask_in[169]
  PIN w_mask_in[170]
    DIRECTION INPUT ;
    USE SIGNAL ;
    SHAPE ABUTMENT ;
    PORT
      LAYER metal3 ;
      RECT 0.000 25.200 0.040 25.235 ;
    END
  END w_mask_in[170]
  PIN w_mask_in[171]
    DIRECTION INPUT ;
    USE SIGNAL ;
    SHAPE ABUTMENT ;
    PORT
      LAYER metal3 ;
      RECT 0.000 25.340 0.040 25.375 ;
    END
  END w_mask_in[171]
  PIN w_mask_in[172]
    DIRECTION INPUT ;
    USE SIGNAL ;
    SHAPE ABUTMENT ;
    PORT
      LAYER metal3 ;
      RECT 0.000 25.480 0.040 25.515 ;
    END
  END w_mask_in[172]
  PIN w_mask_in[173]
    DIRECTION INPUT ;
    USE SIGNAL ;
    SHAPE ABUTMENT ;
    PORT
      LAYER metal3 ;
      RECT 0.000 25.620 0.040 25.655 ;
    END
  END w_mask_in[173]
  PIN w_mask_in[174]
    DIRECTION INPUT ;
    USE SIGNAL ;
    SHAPE ABUTMENT ;
    PORT
      LAYER metal3 ;
      RECT 0.000 25.760 0.040 25.795 ;
    END
  END w_mask_in[174]
  PIN w_mask_in[175]
    DIRECTION INPUT ;
    USE SIGNAL ;
    SHAPE ABUTMENT ;
    PORT
      LAYER metal3 ;
      RECT 0.000 25.900 0.040 25.935 ;
    END
  END w_mask_in[175]
  PIN w_mask_in[176]
    DIRECTION INPUT ;
    USE SIGNAL ;
    SHAPE ABUTMENT ;
    PORT
      LAYER metal3 ;
      RECT 0.000 26.040 0.040 26.075 ;
    END
  END w_mask_in[176]
  PIN w_mask_in[177]
    DIRECTION INPUT ;
    USE SIGNAL ;
    SHAPE ABUTMENT ;
    PORT
      LAYER metal3 ;
      RECT 0.000 26.180 0.040 26.215 ;
    END
  END w_mask_in[177]
  PIN w_mask_in[178]
    DIRECTION INPUT ;
    USE SIGNAL ;
    SHAPE ABUTMENT ;
    PORT
      LAYER metal3 ;
      RECT 0.000 26.320 0.040 26.355 ;
    END
  END w_mask_in[178]
  PIN w_mask_in[179]
    DIRECTION INPUT ;
    USE SIGNAL ;
    SHAPE ABUTMENT ;
    PORT
      LAYER metal3 ;
      RECT 0.000 26.460 0.040 26.495 ;
    END
  END w_mask_in[179]
  PIN w_mask_in[180]
    DIRECTION INPUT ;
    USE SIGNAL ;
    SHAPE ABUTMENT ;
    PORT
      LAYER metal3 ;
      RECT 0.000 26.600 0.040 26.635 ;
    END
  END w_mask_in[180]
  PIN w_mask_in[181]
    DIRECTION INPUT ;
    USE SIGNAL ;
    SHAPE ABUTMENT ;
    PORT
      LAYER metal3 ;
      RECT 0.000 26.740 0.040 26.775 ;
    END
  END w_mask_in[181]
  PIN w_mask_in[182]
    DIRECTION INPUT ;
    USE SIGNAL ;
    SHAPE ABUTMENT ;
    PORT
      LAYER metal3 ;
      RECT 0.000 26.880 0.040 26.915 ;
    END
  END w_mask_in[182]
  PIN w_mask_in[183]
    DIRECTION INPUT ;
    USE SIGNAL ;
    SHAPE ABUTMENT ;
    PORT
      LAYER metal3 ;
      RECT 0.000 27.020 0.040 27.055 ;
    END
  END w_mask_in[183]
  PIN w_mask_in[184]
    DIRECTION INPUT ;
    USE SIGNAL ;
    SHAPE ABUTMENT ;
    PORT
      LAYER metal3 ;
      RECT 0.000 27.160 0.040 27.195 ;
    END
  END w_mask_in[184]
  PIN w_mask_in[185]
    DIRECTION INPUT ;
    USE SIGNAL ;
    SHAPE ABUTMENT ;
    PORT
      LAYER metal3 ;
      RECT 0.000 27.300 0.040 27.335 ;
    END
  END w_mask_in[185]
  PIN w_mask_in[186]
    DIRECTION INPUT ;
    USE SIGNAL ;
    SHAPE ABUTMENT ;
    PORT
      LAYER metal3 ;
      RECT 0.000 27.440 0.040 27.475 ;
    END
  END w_mask_in[186]
  PIN w_mask_in[187]
    DIRECTION INPUT ;
    USE SIGNAL ;
    SHAPE ABUTMENT ;
    PORT
      LAYER metal3 ;
      RECT 0.000 27.580 0.040 27.615 ;
    END
  END w_mask_in[187]
  PIN w_mask_in[188]
    DIRECTION INPUT ;
    USE SIGNAL ;
    SHAPE ABUTMENT ;
    PORT
      LAYER metal3 ;
      RECT 0.000 27.720 0.040 27.755 ;
    END
  END w_mask_in[188]
  PIN w_mask_in[189]
    DIRECTION INPUT ;
    USE SIGNAL ;
    SHAPE ABUTMENT ;
    PORT
      LAYER metal3 ;
      RECT 0.000 27.860 0.040 27.895 ;
    END
  END w_mask_in[189]
  PIN w_mask_in[190]
    DIRECTION INPUT ;
    USE SIGNAL ;
    SHAPE ABUTMENT ;
    PORT
      LAYER metal3 ;
      RECT 0.000 28.000 0.040 28.035 ;
    END
  END w_mask_in[190]
  PIN w_mask_in[191]
    DIRECTION INPUT ;
    USE SIGNAL ;
    SHAPE ABUTMENT ;
    PORT
      LAYER metal3 ;
      RECT 0.000 28.140 0.040 28.175 ;
    END
  END w_mask_in[191]
  PIN w_mask_in[192]
    DIRECTION INPUT ;
    USE SIGNAL ;
    SHAPE ABUTMENT ;
    PORT
      LAYER metal3 ;
      RECT 0.000 28.280 0.040 28.315 ;
    END
  END w_mask_in[192]
  PIN w_mask_in[193]
    DIRECTION INPUT ;
    USE SIGNAL ;
    SHAPE ABUTMENT ;
    PORT
      LAYER metal3 ;
      RECT 0.000 28.420 0.040 28.455 ;
    END
  END w_mask_in[193]
  PIN w_mask_in[194]
    DIRECTION INPUT ;
    USE SIGNAL ;
    SHAPE ABUTMENT ;
    PORT
      LAYER metal3 ;
      RECT 0.000 28.560 0.040 28.595 ;
    END
  END w_mask_in[194]
  PIN w_mask_in[195]
    DIRECTION INPUT ;
    USE SIGNAL ;
    SHAPE ABUTMENT ;
    PORT
      LAYER metal3 ;
      RECT 0.000 28.700 0.040 28.735 ;
    END
  END w_mask_in[195]
  PIN w_mask_in[196]
    DIRECTION INPUT ;
    USE SIGNAL ;
    SHAPE ABUTMENT ;
    PORT
      LAYER metal3 ;
      RECT 0.000 28.840 0.040 28.875 ;
    END
  END w_mask_in[196]
  PIN w_mask_in[197]
    DIRECTION INPUT ;
    USE SIGNAL ;
    SHAPE ABUTMENT ;
    PORT
      LAYER metal3 ;
      RECT 0.000 28.980 0.040 29.015 ;
    END
  END w_mask_in[197]
  PIN w_mask_in[198]
    DIRECTION INPUT ;
    USE SIGNAL ;
    SHAPE ABUTMENT ;
    PORT
      LAYER metal3 ;
      RECT 0.000 29.120 0.040 29.155 ;
    END
  END w_mask_in[198]
  PIN w_mask_in[199]
    DIRECTION INPUT ;
    USE SIGNAL ;
    SHAPE ABUTMENT ;
    PORT
      LAYER metal3 ;
      RECT 0.000 29.260 0.040 29.295 ;
    END
  END w_mask_in[199]
  PIN w_mask_in[200]
    DIRECTION INPUT ;
    USE SIGNAL ;
    SHAPE ABUTMENT ;
    PORT
      LAYER metal3 ;
      RECT 0.000 29.400 0.040 29.435 ;
    END
  END w_mask_in[200]
  PIN w_mask_in[201]
    DIRECTION INPUT ;
    USE SIGNAL ;
    SHAPE ABUTMENT ;
    PORT
      LAYER metal3 ;
      RECT 0.000 29.540 0.040 29.575 ;
    END
  END w_mask_in[201]
  PIN w_mask_in[202]
    DIRECTION INPUT ;
    USE SIGNAL ;
    SHAPE ABUTMENT ;
    PORT
      LAYER metal3 ;
      RECT 0.000 29.680 0.040 29.715 ;
    END
  END w_mask_in[202]
  PIN w_mask_in[203]
    DIRECTION INPUT ;
    USE SIGNAL ;
    SHAPE ABUTMENT ;
    PORT
      LAYER metal3 ;
      RECT 0.000 29.820 0.040 29.855 ;
    END
  END w_mask_in[203]
  PIN w_mask_in[204]
    DIRECTION INPUT ;
    USE SIGNAL ;
    SHAPE ABUTMENT ;
    PORT
      LAYER metal3 ;
      RECT 0.000 29.960 0.040 29.995 ;
    END
  END w_mask_in[204]
  PIN w_mask_in[205]
    DIRECTION INPUT ;
    USE SIGNAL ;
    SHAPE ABUTMENT ;
    PORT
      LAYER metal3 ;
      RECT 0.000 30.100 0.040 30.135 ;
    END
  END w_mask_in[205]
  PIN w_mask_in[206]
    DIRECTION INPUT ;
    USE SIGNAL ;
    SHAPE ABUTMENT ;
    PORT
      LAYER metal3 ;
      RECT 0.000 30.240 0.040 30.275 ;
    END
  END w_mask_in[206]
  PIN w_mask_in[207]
    DIRECTION INPUT ;
    USE SIGNAL ;
    SHAPE ABUTMENT ;
    PORT
      LAYER metal3 ;
      RECT 0.000 30.380 0.040 30.415 ;
    END
  END w_mask_in[207]
  PIN w_mask_in[208]
    DIRECTION INPUT ;
    USE SIGNAL ;
    SHAPE ABUTMENT ;
    PORT
      LAYER metal3 ;
      RECT 0.000 30.520 0.040 30.555 ;
    END
  END w_mask_in[208]
  PIN w_mask_in[209]
    DIRECTION INPUT ;
    USE SIGNAL ;
    SHAPE ABUTMENT ;
    PORT
      LAYER metal3 ;
      RECT 0.000 30.660 0.040 30.695 ;
    END
  END w_mask_in[209]
  PIN w_mask_in[210]
    DIRECTION INPUT ;
    USE SIGNAL ;
    SHAPE ABUTMENT ;
    PORT
      LAYER metal3 ;
      RECT 0.000 30.800 0.040 30.835 ;
    END
  END w_mask_in[210]
  PIN w_mask_in[211]
    DIRECTION INPUT ;
    USE SIGNAL ;
    SHAPE ABUTMENT ;
    PORT
      LAYER metal3 ;
      RECT 0.000 30.940 0.040 30.975 ;
    END
  END w_mask_in[211]
  PIN w_mask_in[212]
    DIRECTION INPUT ;
    USE SIGNAL ;
    SHAPE ABUTMENT ;
    PORT
      LAYER metal3 ;
      RECT 0.000 31.080 0.040 31.115 ;
    END
  END w_mask_in[212]
  PIN w_mask_in[213]
    DIRECTION INPUT ;
    USE SIGNAL ;
    SHAPE ABUTMENT ;
    PORT
      LAYER metal3 ;
      RECT 0.000 31.220 0.040 31.255 ;
    END
  END w_mask_in[213]
  PIN w_mask_in[214]
    DIRECTION INPUT ;
    USE SIGNAL ;
    SHAPE ABUTMENT ;
    PORT
      LAYER metal3 ;
      RECT 0.000 31.360 0.040 31.395 ;
    END
  END w_mask_in[214]
  PIN w_mask_in[215]
    DIRECTION INPUT ;
    USE SIGNAL ;
    SHAPE ABUTMENT ;
    PORT
      LAYER metal3 ;
      RECT 0.000 31.500 0.040 31.535 ;
    END
  END w_mask_in[215]
  PIN w_mask_in[216]
    DIRECTION INPUT ;
    USE SIGNAL ;
    SHAPE ABUTMENT ;
    PORT
      LAYER metal3 ;
      RECT 0.000 31.640 0.040 31.675 ;
    END
  END w_mask_in[216]
  PIN w_mask_in[217]
    DIRECTION INPUT ;
    USE SIGNAL ;
    SHAPE ABUTMENT ;
    PORT
      LAYER metal3 ;
      RECT 0.000 31.780 0.040 31.815 ;
    END
  END w_mask_in[217]
  PIN w_mask_in[218]
    DIRECTION INPUT ;
    USE SIGNAL ;
    SHAPE ABUTMENT ;
    PORT
      LAYER metal3 ;
      RECT 0.000 31.920 0.040 31.955 ;
    END
  END w_mask_in[218]
  PIN w_mask_in[219]
    DIRECTION INPUT ;
    USE SIGNAL ;
    SHAPE ABUTMENT ;
    PORT
      LAYER metal3 ;
      RECT 0.000 32.060 0.040 32.095 ;
    END
  END w_mask_in[219]
  PIN w_mask_in[220]
    DIRECTION INPUT ;
    USE SIGNAL ;
    SHAPE ABUTMENT ;
    PORT
      LAYER metal3 ;
      RECT 0.000 32.200 0.040 32.235 ;
    END
  END w_mask_in[220]
  PIN w_mask_in[221]
    DIRECTION INPUT ;
    USE SIGNAL ;
    SHAPE ABUTMENT ;
    PORT
      LAYER metal3 ;
      RECT 0.000 32.340 0.040 32.375 ;
    END
  END w_mask_in[221]
  PIN w_mask_in[222]
    DIRECTION INPUT ;
    USE SIGNAL ;
    SHAPE ABUTMENT ;
    PORT
      LAYER metal3 ;
      RECT 0.000 32.480 0.040 32.515 ;
    END
  END w_mask_in[222]
  PIN w_mask_in[223]
    DIRECTION INPUT ;
    USE SIGNAL ;
    SHAPE ABUTMENT ;
    PORT
      LAYER metal3 ;
      RECT 0.000 32.620 0.040 32.655 ;
    END
  END w_mask_in[223]
  PIN w_mask_in[224]
    DIRECTION INPUT ;
    USE SIGNAL ;
    SHAPE ABUTMENT ;
    PORT
      LAYER metal3 ;
      RECT 0.000 32.760 0.040 32.795 ;
    END
  END w_mask_in[224]
  PIN w_mask_in[225]
    DIRECTION INPUT ;
    USE SIGNAL ;
    SHAPE ABUTMENT ;
    PORT
      LAYER metal3 ;
      RECT 0.000 32.900 0.040 32.935 ;
    END
  END w_mask_in[225]
  PIN w_mask_in[226]
    DIRECTION INPUT ;
    USE SIGNAL ;
    SHAPE ABUTMENT ;
    PORT
      LAYER metal3 ;
      RECT 0.000 33.040 0.040 33.075 ;
    END
  END w_mask_in[226]
  PIN w_mask_in[227]
    DIRECTION INPUT ;
    USE SIGNAL ;
    SHAPE ABUTMENT ;
    PORT
      LAYER metal3 ;
      RECT 0.000 33.180 0.040 33.215 ;
    END
  END w_mask_in[227]
  PIN w_mask_in[228]
    DIRECTION INPUT ;
    USE SIGNAL ;
    SHAPE ABUTMENT ;
    PORT
      LAYER metal3 ;
      RECT 0.000 33.320 0.040 33.355 ;
    END
  END w_mask_in[228]
  PIN w_mask_in[229]
    DIRECTION INPUT ;
    USE SIGNAL ;
    SHAPE ABUTMENT ;
    PORT
      LAYER metal3 ;
      RECT 0.000 33.460 0.040 33.495 ;
    END
  END w_mask_in[229]
  PIN w_mask_in[230]
    DIRECTION INPUT ;
    USE SIGNAL ;
    SHAPE ABUTMENT ;
    PORT
      LAYER metal3 ;
      RECT 0.000 33.600 0.040 33.635 ;
    END
  END w_mask_in[230]
  PIN w_mask_in[231]
    DIRECTION INPUT ;
    USE SIGNAL ;
    SHAPE ABUTMENT ;
    PORT
      LAYER metal3 ;
      RECT 0.000 33.740 0.040 33.775 ;
    END
  END w_mask_in[231]
  PIN w_mask_in[232]
    DIRECTION INPUT ;
    USE SIGNAL ;
    SHAPE ABUTMENT ;
    PORT
      LAYER metal3 ;
      RECT 0.000 33.880 0.040 33.915 ;
    END
  END w_mask_in[232]
  PIN w_mask_in[233]
    DIRECTION INPUT ;
    USE SIGNAL ;
    SHAPE ABUTMENT ;
    PORT
      LAYER metal3 ;
      RECT 0.000 34.020 0.040 34.055 ;
    END
  END w_mask_in[233]
  PIN w_mask_in[234]
    DIRECTION INPUT ;
    USE SIGNAL ;
    SHAPE ABUTMENT ;
    PORT
      LAYER metal3 ;
      RECT 0.000 34.160 0.040 34.195 ;
    END
  END w_mask_in[234]
  PIN w_mask_in[235]
    DIRECTION INPUT ;
    USE SIGNAL ;
    SHAPE ABUTMENT ;
    PORT
      LAYER metal3 ;
      RECT 0.000 34.300 0.040 34.335 ;
    END
  END w_mask_in[235]
  PIN w_mask_in[236]
    DIRECTION INPUT ;
    USE SIGNAL ;
    SHAPE ABUTMENT ;
    PORT
      LAYER metal3 ;
      RECT 0.000 34.440 0.040 34.475 ;
    END
  END w_mask_in[236]
  PIN w_mask_in[237]
    DIRECTION INPUT ;
    USE SIGNAL ;
    SHAPE ABUTMENT ;
    PORT
      LAYER metal3 ;
      RECT 0.000 34.580 0.040 34.615 ;
    END
  END w_mask_in[237]
  PIN w_mask_in[238]
    DIRECTION INPUT ;
    USE SIGNAL ;
    SHAPE ABUTMENT ;
    PORT
      LAYER metal3 ;
      RECT 0.000 34.720 0.040 34.755 ;
    END
  END w_mask_in[238]
  PIN w_mask_in[239]
    DIRECTION INPUT ;
    USE SIGNAL ;
    SHAPE ABUTMENT ;
    PORT
      LAYER metal3 ;
      RECT 0.000 34.860 0.040 34.895 ;
    END
  END w_mask_in[239]
  PIN w_mask_in[240]
    DIRECTION INPUT ;
    USE SIGNAL ;
    SHAPE ABUTMENT ;
    PORT
      LAYER metal3 ;
      RECT 0.000 35.000 0.040 35.035 ;
    END
  END w_mask_in[240]
  PIN w_mask_in[241]
    DIRECTION INPUT ;
    USE SIGNAL ;
    SHAPE ABUTMENT ;
    PORT
      LAYER metal3 ;
      RECT 0.000 35.140 0.040 35.175 ;
    END
  END w_mask_in[241]
  PIN w_mask_in[242]
    DIRECTION INPUT ;
    USE SIGNAL ;
    SHAPE ABUTMENT ;
    PORT
      LAYER metal3 ;
      RECT 0.000 35.280 0.040 35.315 ;
    END
  END w_mask_in[242]
  PIN w_mask_in[243]
    DIRECTION INPUT ;
    USE SIGNAL ;
    SHAPE ABUTMENT ;
    PORT
      LAYER metal3 ;
      RECT 0.000 35.420 0.040 35.455 ;
    END
  END w_mask_in[243]
  PIN w_mask_in[244]
    DIRECTION INPUT ;
    USE SIGNAL ;
    SHAPE ABUTMENT ;
    PORT
      LAYER metal3 ;
      RECT 0.000 35.560 0.040 35.595 ;
    END
  END w_mask_in[244]
  PIN w_mask_in[245]
    DIRECTION INPUT ;
    USE SIGNAL ;
    SHAPE ABUTMENT ;
    PORT
      LAYER metal3 ;
      RECT 0.000 35.700 0.040 35.735 ;
    END
  END w_mask_in[245]
  PIN w_mask_in[246]
    DIRECTION INPUT ;
    USE SIGNAL ;
    SHAPE ABUTMENT ;
    PORT
      LAYER metal3 ;
      RECT 0.000 35.840 0.040 35.875 ;
    END
  END w_mask_in[246]
  PIN w_mask_in[247]
    DIRECTION INPUT ;
    USE SIGNAL ;
    SHAPE ABUTMENT ;
    PORT
      LAYER metal3 ;
      RECT 0.000 35.980 0.040 36.015 ;
    END
  END w_mask_in[247]
  PIN w_mask_in[248]
    DIRECTION INPUT ;
    USE SIGNAL ;
    SHAPE ABUTMENT ;
    PORT
      LAYER metal3 ;
      RECT 0.000 36.120 0.040 36.155 ;
    END
  END w_mask_in[248]
  PIN w_mask_in[249]
    DIRECTION INPUT ;
    USE SIGNAL ;
    SHAPE ABUTMENT ;
    PORT
      LAYER metal3 ;
      RECT 0.000 36.260 0.040 36.295 ;
    END
  END w_mask_in[249]
  PIN w_mask_in[250]
    DIRECTION INPUT ;
    USE SIGNAL ;
    SHAPE ABUTMENT ;
    PORT
      LAYER metal3 ;
      RECT 0.000 36.400 0.040 36.435 ;
    END
  END w_mask_in[250]
  PIN w_mask_in[251]
    DIRECTION INPUT ;
    USE SIGNAL ;
    SHAPE ABUTMENT ;
    PORT
      LAYER metal3 ;
      RECT 0.000 36.540 0.040 36.575 ;
    END
  END w_mask_in[251]
  PIN w_mask_in[252]
    DIRECTION INPUT ;
    USE SIGNAL ;
    SHAPE ABUTMENT ;
    PORT
      LAYER metal3 ;
      RECT 0.000 36.680 0.040 36.715 ;
    END
  END w_mask_in[252]
  PIN w_mask_in[253]
    DIRECTION INPUT ;
    USE SIGNAL ;
    SHAPE ABUTMENT ;
    PORT
      LAYER metal3 ;
      RECT 0.000 36.820 0.040 36.855 ;
    END
  END w_mask_in[253]
  PIN w_mask_in[254]
    DIRECTION INPUT ;
    USE SIGNAL ;
    SHAPE ABUTMENT ;
    PORT
      LAYER metal3 ;
      RECT 0.000 36.960 0.040 36.995 ;
    END
  END w_mask_in[254]
  PIN w_mask_in[255]
    DIRECTION INPUT ;
    USE SIGNAL ;
    SHAPE ABUTMENT ;
    PORT
      LAYER metal3 ;
      RECT 0.000 37.100 0.040 37.135 ;
    END
  END w_mask_in[255]
  PIN rd_out[0]
    DIRECTION OUTPUT ;
    USE SIGNAL ;
    SHAPE ABUTMENT ;
    PORT
      LAYER metal3 ;
      RECT 0.000 37.240 0.040 37.275 ;
    END
  END rd_out[0]
  PIN rd_out[1]
    DIRECTION OUTPUT ;
    USE SIGNAL ;
    SHAPE ABUTMENT ;
    PORT
      LAYER metal3 ;
      RECT 0.000 37.380 0.040 37.415 ;
    END
  END rd_out[1]
  PIN rd_out[2]
    DIRECTION OUTPUT ;
    USE SIGNAL ;
    SHAPE ABUTMENT ;
    PORT
      LAYER metal3 ;
      RECT 0.000 37.520 0.040 37.555 ;
    END
  END rd_out[2]
  PIN rd_out[3]
    DIRECTION OUTPUT ;
    USE SIGNAL ;
    SHAPE ABUTMENT ;
    PORT
      LAYER metal3 ;
      RECT 0.000 37.660 0.040 37.695 ;
    END
  END rd_out[3]
  PIN rd_out[4]
    DIRECTION OUTPUT ;
    USE SIGNAL ;
    SHAPE ABUTMENT ;
    PORT
      LAYER metal3 ;
      RECT 0.000 37.800 0.040 37.835 ;
    END
  END rd_out[4]
  PIN rd_out[5]
    DIRECTION OUTPUT ;
    USE SIGNAL ;
    SHAPE ABUTMENT ;
    PORT
      LAYER metal3 ;
      RECT 0.000 37.940 0.040 37.975 ;
    END
  END rd_out[5]
  PIN rd_out[6]
    DIRECTION OUTPUT ;
    USE SIGNAL ;
    SHAPE ABUTMENT ;
    PORT
      LAYER metal3 ;
      RECT 0.000 38.080 0.040 38.115 ;
    END
  END rd_out[6]
  PIN rd_out[7]
    DIRECTION OUTPUT ;
    USE SIGNAL ;
    SHAPE ABUTMENT ;
    PORT
      LAYER metal3 ;
      RECT 0.000 38.220 0.040 38.255 ;
    END
  END rd_out[7]
  PIN rd_out[8]
    DIRECTION OUTPUT ;
    USE SIGNAL ;
    SHAPE ABUTMENT ;
    PORT
      LAYER metal3 ;
      RECT 0.000 38.360 0.040 38.395 ;
    END
  END rd_out[8]
  PIN rd_out[9]
    DIRECTION OUTPUT ;
    USE SIGNAL ;
    SHAPE ABUTMENT ;
    PORT
      LAYER metal3 ;
      RECT 0.000 38.500 0.040 38.535 ;
    END
  END rd_out[9]
  PIN rd_out[10]
    DIRECTION OUTPUT ;
    USE SIGNAL ;
    SHAPE ABUTMENT ;
    PORT
      LAYER metal3 ;
      RECT 0.000 38.640 0.040 38.675 ;
    END
  END rd_out[10]
  PIN rd_out[11]
    DIRECTION OUTPUT ;
    USE SIGNAL ;
    SHAPE ABUTMENT ;
    PORT
      LAYER metal3 ;
      RECT 0.000 38.780 0.040 38.815 ;
    END
  END rd_out[11]
  PIN rd_out[12]
    DIRECTION OUTPUT ;
    USE SIGNAL ;
    SHAPE ABUTMENT ;
    PORT
      LAYER metal3 ;
      RECT 0.000 38.920 0.040 38.955 ;
    END
  END rd_out[12]
  PIN rd_out[13]
    DIRECTION OUTPUT ;
    USE SIGNAL ;
    SHAPE ABUTMENT ;
    PORT
      LAYER metal3 ;
      RECT 0.000 39.060 0.040 39.095 ;
    END
  END rd_out[13]
  PIN rd_out[14]
    DIRECTION OUTPUT ;
    USE SIGNAL ;
    SHAPE ABUTMENT ;
    PORT
      LAYER metal3 ;
      RECT 0.000 39.200 0.040 39.235 ;
    END
  END rd_out[14]
  PIN rd_out[15]
    DIRECTION OUTPUT ;
    USE SIGNAL ;
    SHAPE ABUTMENT ;
    PORT
      LAYER metal3 ;
      RECT 0.000 39.340 0.040 39.375 ;
    END
  END rd_out[15]
  PIN rd_out[16]
    DIRECTION OUTPUT ;
    USE SIGNAL ;
    SHAPE ABUTMENT ;
    PORT
      LAYER metal3 ;
      RECT 0.000 39.480 0.040 39.515 ;
    END
  END rd_out[16]
  PIN rd_out[17]
    DIRECTION OUTPUT ;
    USE SIGNAL ;
    SHAPE ABUTMENT ;
    PORT
      LAYER metal3 ;
      RECT 0.000 39.620 0.040 39.655 ;
    END
  END rd_out[17]
  PIN rd_out[18]
    DIRECTION OUTPUT ;
    USE SIGNAL ;
    SHAPE ABUTMENT ;
    PORT
      LAYER metal3 ;
      RECT 0.000 39.760 0.040 39.795 ;
    END
  END rd_out[18]
  PIN rd_out[19]
    DIRECTION OUTPUT ;
    USE SIGNAL ;
    SHAPE ABUTMENT ;
    PORT
      LAYER metal3 ;
      RECT 0.000 39.900 0.040 39.935 ;
    END
  END rd_out[19]
  PIN rd_out[20]
    DIRECTION OUTPUT ;
    USE SIGNAL ;
    SHAPE ABUTMENT ;
    PORT
      LAYER metal3 ;
      RECT 0.000 40.040 0.040 40.075 ;
    END
  END rd_out[20]
  PIN rd_out[21]
    DIRECTION OUTPUT ;
    USE SIGNAL ;
    SHAPE ABUTMENT ;
    PORT
      LAYER metal3 ;
      RECT 0.000 40.180 0.040 40.215 ;
    END
  END rd_out[21]
  PIN rd_out[22]
    DIRECTION OUTPUT ;
    USE SIGNAL ;
    SHAPE ABUTMENT ;
    PORT
      LAYER metal3 ;
      RECT 0.000 40.320 0.040 40.355 ;
    END
  END rd_out[22]
  PIN rd_out[23]
    DIRECTION OUTPUT ;
    USE SIGNAL ;
    SHAPE ABUTMENT ;
    PORT
      LAYER metal3 ;
      RECT 0.000 40.460 0.040 40.495 ;
    END
  END rd_out[23]
  PIN rd_out[24]
    DIRECTION OUTPUT ;
    USE SIGNAL ;
    SHAPE ABUTMENT ;
    PORT
      LAYER metal3 ;
      RECT 0.000 40.600 0.040 40.635 ;
    END
  END rd_out[24]
  PIN rd_out[25]
    DIRECTION OUTPUT ;
    USE SIGNAL ;
    SHAPE ABUTMENT ;
    PORT
      LAYER metal3 ;
      RECT 0.000 40.740 0.040 40.775 ;
    END
  END rd_out[25]
  PIN rd_out[26]
    DIRECTION OUTPUT ;
    USE SIGNAL ;
    SHAPE ABUTMENT ;
    PORT
      LAYER metal3 ;
      RECT 0.000 40.880 0.040 40.915 ;
    END
  END rd_out[26]
  PIN rd_out[27]
    DIRECTION OUTPUT ;
    USE SIGNAL ;
    SHAPE ABUTMENT ;
    PORT
      LAYER metal3 ;
      RECT 0.000 41.020 0.040 41.055 ;
    END
  END rd_out[27]
  PIN rd_out[28]
    DIRECTION OUTPUT ;
    USE SIGNAL ;
    SHAPE ABUTMENT ;
    PORT
      LAYER metal3 ;
      RECT 0.000 41.160 0.040 41.195 ;
    END
  END rd_out[28]
  PIN rd_out[29]
    DIRECTION OUTPUT ;
    USE SIGNAL ;
    SHAPE ABUTMENT ;
    PORT
      LAYER metal3 ;
      RECT 0.000 41.300 0.040 41.335 ;
    END
  END rd_out[29]
  PIN rd_out[30]
    DIRECTION OUTPUT ;
    USE SIGNAL ;
    SHAPE ABUTMENT ;
    PORT
      LAYER metal3 ;
      RECT 0.000 41.440 0.040 41.475 ;
    END
  END rd_out[30]
  PIN rd_out[31]
    DIRECTION OUTPUT ;
    USE SIGNAL ;
    SHAPE ABUTMENT ;
    PORT
      LAYER metal3 ;
      RECT 0.000 41.580 0.040 41.615 ;
    END
  END rd_out[31]
  PIN rd_out[32]
    DIRECTION OUTPUT ;
    USE SIGNAL ;
    SHAPE ABUTMENT ;
    PORT
      LAYER metal3 ;
      RECT 0.000 41.720 0.040 41.755 ;
    END
  END rd_out[32]
  PIN rd_out[33]
    DIRECTION OUTPUT ;
    USE SIGNAL ;
    SHAPE ABUTMENT ;
    PORT
      LAYER metal3 ;
      RECT 0.000 41.860 0.040 41.895 ;
    END
  END rd_out[33]
  PIN rd_out[34]
    DIRECTION OUTPUT ;
    USE SIGNAL ;
    SHAPE ABUTMENT ;
    PORT
      LAYER metal3 ;
      RECT 0.000 42.000 0.040 42.035 ;
    END
  END rd_out[34]
  PIN rd_out[35]
    DIRECTION OUTPUT ;
    USE SIGNAL ;
    SHAPE ABUTMENT ;
    PORT
      LAYER metal3 ;
      RECT 0.000 42.140 0.040 42.175 ;
    END
  END rd_out[35]
  PIN rd_out[36]
    DIRECTION OUTPUT ;
    USE SIGNAL ;
    SHAPE ABUTMENT ;
    PORT
      LAYER metal3 ;
      RECT 0.000 42.280 0.040 42.315 ;
    END
  END rd_out[36]
  PIN rd_out[37]
    DIRECTION OUTPUT ;
    USE SIGNAL ;
    SHAPE ABUTMENT ;
    PORT
      LAYER metal3 ;
      RECT 0.000 42.420 0.040 42.455 ;
    END
  END rd_out[37]
  PIN rd_out[38]
    DIRECTION OUTPUT ;
    USE SIGNAL ;
    SHAPE ABUTMENT ;
    PORT
      LAYER metal3 ;
      RECT 0.000 42.560 0.040 42.595 ;
    END
  END rd_out[38]
  PIN rd_out[39]
    DIRECTION OUTPUT ;
    USE SIGNAL ;
    SHAPE ABUTMENT ;
    PORT
      LAYER metal3 ;
      RECT 0.000 42.700 0.040 42.735 ;
    END
  END rd_out[39]
  PIN rd_out[40]
    DIRECTION OUTPUT ;
    USE SIGNAL ;
    SHAPE ABUTMENT ;
    PORT
      LAYER metal3 ;
      RECT 0.000 42.840 0.040 42.875 ;
    END
  END rd_out[40]
  PIN rd_out[41]
    DIRECTION OUTPUT ;
    USE SIGNAL ;
    SHAPE ABUTMENT ;
    PORT
      LAYER metal3 ;
      RECT 0.000 42.980 0.040 43.015 ;
    END
  END rd_out[41]
  PIN rd_out[42]
    DIRECTION OUTPUT ;
    USE SIGNAL ;
    SHAPE ABUTMENT ;
    PORT
      LAYER metal3 ;
      RECT 0.000 43.120 0.040 43.155 ;
    END
  END rd_out[42]
  PIN rd_out[43]
    DIRECTION OUTPUT ;
    USE SIGNAL ;
    SHAPE ABUTMENT ;
    PORT
      LAYER metal3 ;
      RECT 0.000 43.260 0.040 43.295 ;
    END
  END rd_out[43]
  PIN rd_out[44]
    DIRECTION OUTPUT ;
    USE SIGNAL ;
    SHAPE ABUTMENT ;
    PORT
      LAYER metal3 ;
      RECT 0.000 43.400 0.040 43.435 ;
    END
  END rd_out[44]
  PIN rd_out[45]
    DIRECTION OUTPUT ;
    USE SIGNAL ;
    SHAPE ABUTMENT ;
    PORT
      LAYER metal3 ;
      RECT 0.000 43.540 0.040 43.575 ;
    END
  END rd_out[45]
  PIN rd_out[46]
    DIRECTION OUTPUT ;
    USE SIGNAL ;
    SHAPE ABUTMENT ;
    PORT
      LAYER metal3 ;
      RECT 0.000 43.680 0.040 43.715 ;
    END
  END rd_out[46]
  PIN rd_out[47]
    DIRECTION OUTPUT ;
    USE SIGNAL ;
    SHAPE ABUTMENT ;
    PORT
      LAYER metal3 ;
      RECT 0.000 43.820 0.040 43.855 ;
    END
  END rd_out[47]
  PIN rd_out[48]
    DIRECTION OUTPUT ;
    USE SIGNAL ;
    SHAPE ABUTMENT ;
    PORT
      LAYER metal3 ;
      RECT 0.000 43.960 0.040 43.995 ;
    END
  END rd_out[48]
  PIN rd_out[49]
    DIRECTION OUTPUT ;
    USE SIGNAL ;
    SHAPE ABUTMENT ;
    PORT
      LAYER metal3 ;
      RECT 0.000 44.100 0.040 44.135 ;
    END
  END rd_out[49]
  PIN rd_out[50]
    DIRECTION OUTPUT ;
    USE SIGNAL ;
    SHAPE ABUTMENT ;
    PORT
      LAYER metal3 ;
      RECT 0.000 44.240 0.040 44.275 ;
    END
  END rd_out[50]
  PIN rd_out[51]
    DIRECTION OUTPUT ;
    USE SIGNAL ;
    SHAPE ABUTMENT ;
    PORT
      LAYER metal3 ;
      RECT 0.000 44.380 0.040 44.415 ;
    END
  END rd_out[51]
  PIN rd_out[52]
    DIRECTION OUTPUT ;
    USE SIGNAL ;
    SHAPE ABUTMENT ;
    PORT
      LAYER metal3 ;
      RECT 0.000 44.520 0.040 44.555 ;
    END
  END rd_out[52]
  PIN rd_out[53]
    DIRECTION OUTPUT ;
    USE SIGNAL ;
    SHAPE ABUTMENT ;
    PORT
      LAYER metal3 ;
      RECT 0.000 44.660 0.040 44.695 ;
    END
  END rd_out[53]
  PIN rd_out[54]
    DIRECTION OUTPUT ;
    USE SIGNAL ;
    SHAPE ABUTMENT ;
    PORT
      LAYER metal3 ;
      RECT 0.000 44.800 0.040 44.835 ;
    END
  END rd_out[54]
  PIN rd_out[55]
    DIRECTION OUTPUT ;
    USE SIGNAL ;
    SHAPE ABUTMENT ;
    PORT
      LAYER metal3 ;
      RECT 0.000 44.940 0.040 44.975 ;
    END
  END rd_out[55]
  PIN rd_out[56]
    DIRECTION OUTPUT ;
    USE SIGNAL ;
    SHAPE ABUTMENT ;
    PORT
      LAYER metal3 ;
      RECT 0.000 45.080 0.040 45.115 ;
    END
  END rd_out[56]
  PIN rd_out[57]
    DIRECTION OUTPUT ;
    USE SIGNAL ;
    SHAPE ABUTMENT ;
    PORT
      LAYER metal3 ;
      RECT 0.000 45.220 0.040 45.255 ;
    END
  END rd_out[57]
  PIN rd_out[58]
    DIRECTION OUTPUT ;
    USE SIGNAL ;
    SHAPE ABUTMENT ;
    PORT
      LAYER metal3 ;
      RECT 0.000 45.360 0.040 45.395 ;
    END
  END rd_out[58]
  PIN rd_out[59]
    DIRECTION OUTPUT ;
    USE SIGNAL ;
    SHAPE ABUTMENT ;
    PORT
      LAYER metal3 ;
      RECT 0.000 45.500 0.040 45.535 ;
    END
  END rd_out[59]
  PIN rd_out[60]
    DIRECTION OUTPUT ;
    USE SIGNAL ;
    SHAPE ABUTMENT ;
    PORT
      LAYER metal3 ;
      RECT 0.000 45.640 0.040 45.675 ;
    END
  END rd_out[60]
  PIN rd_out[61]
    DIRECTION OUTPUT ;
    USE SIGNAL ;
    SHAPE ABUTMENT ;
    PORT
      LAYER metal3 ;
      RECT 0.000 45.780 0.040 45.815 ;
    END
  END rd_out[61]
  PIN rd_out[62]
    DIRECTION OUTPUT ;
    USE SIGNAL ;
    SHAPE ABUTMENT ;
    PORT
      LAYER metal3 ;
      RECT 0.000 45.920 0.040 45.955 ;
    END
  END rd_out[62]
  PIN rd_out[63]
    DIRECTION OUTPUT ;
    USE SIGNAL ;
    SHAPE ABUTMENT ;
    PORT
      LAYER metal3 ;
      RECT 0.000 46.060 0.040 46.095 ;
    END
  END rd_out[63]
  PIN rd_out[64]
    DIRECTION OUTPUT ;
    USE SIGNAL ;
    SHAPE ABUTMENT ;
    PORT
      LAYER metal3 ;
      RECT 0.000 46.200 0.040 46.235 ;
    END
  END rd_out[64]
  PIN rd_out[65]
    DIRECTION OUTPUT ;
    USE SIGNAL ;
    SHAPE ABUTMENT ;
    PORT
      LAYER metal3 ;
      RECT 0.000 46.340 0.040 46.375 ;
    END
  END rd_out[65]
  PIN rd_out[66]
    DIRECTION OUTPUT ;
    USE SIGNAL ;
    SHAPE ABUTMENT ;
    PORT
      LAYER metal3 ;
      RECT 0.000 46.480 0.040 46.515 ;
    END
  END rd_out[66]
  PIN rd_out[67]
    DIRECTION OUTPUT ;
    USE SIGNAL ;
    SHAPE ABUTMENT ;
    PORT
      LAYER metal3 ;
      RECT 0.000 46.620 0.040 46.655 ;
    END
  END rd_out[67]
  PIN rd_out[68]
    DIRECTION OUTPUT ;
    USE SIGNAL ;
    SHAPE ABUTMENT ;
    PORT
      LAYER metal3 ;
      RECT 0.000 46.760 0.040 46.795 ;
    END
  END rd_out[68]
  PIN rd_out[69]
    DIRECTION OUTPUT ;
    USE SIGNAL ;
    SHAPE ABUTMENT ;
    PORT
      LAYER metal3 ;
      RECT 0.000 46.900 0.040 46.935 ;
    END
  END rd_out[69]
  PIN rd_out[70]
    DIRECTION OUTPUT ;
    USE SIGNAL ;
    SHAPE ABUTMENT ;
    PORT
      LAYER metal3 ;
      RECT 0.000 47.040 0.040 47.075 ;
    END
  END rd_out[70]
  PIN rd_out[71]
    DIRECTION OUTPUT ;
    USE SIGNAL ;
    SHAPE ABUTMENT ;
    PORT
      LAYER metal3 ;
      RECT 0.000 47.180 0.040 47.215 ;
    END
  END rd_out[71]
  PIN rd_out[72]
    DIRECTION OUTPUT ;
    USE SIGNAL ;
    SHAPE ABUTMENT ;
    PORT
      LAYER metal3 ;
      RECT 0.000 47.320 0.040 47.355 ;
    END
  END rd_out[72]
  PIN rd_out[73]
    DIRECTION OUTPUT ;
    USE SIGNAL ;
    SHAPE ABUTMENT ;
    PORT
      LAYER metal3 ;
      RECT 0.000 47.460 0.040 47.495 ;
    END
  END rd_out[73]
  PIN rd_out[74]
    DIRECTION OUTPUT ;
    USE SIGNAL ;
    SHAPE ABUTMENT ;
    PORT
      LAYER metal3 ;
      RECT 0.000 47.600 0.040 47.635 ;
    END
  END rd_out[74]
  PIN rd_out[75]
    DIRECTION OUTPUT ;
    USE SIGNAL ;
    SHAPE ABUTMENT ;
    PORT
      LAYER metal3 ;
      RECT 0.000 47.740 0.040 47.775 ;
    END
  END rd_out[75]
  PIN rd_out[76]
    DIRECTION OUTPUT ;
    USE SIGNAL ;
    SHAPE ABUTMENT ;
    PORT
      LAYER metal3 ;
      RECT 0.000 47.880 0.040 47.915 ;
    END
  END rd_out[76]
  PIN rd_out[77]
    DIRECTION OUTPUT ;
    USE SIGNAL ;
    SHAPE ABUTMENT ;
    PORT
      LAYER metal3 ;
      RECT 0.000 48.020 0.040 48.055 ;
    END
  END rd_out[77]
  PIN rd_out[78]
    DIRECTION OUTPUT ;
    USE SIGNAL ;
    SHAPE ABUTMENT ;
    PORT
      LAYER metal3 ;
      RECT 0.000 48.160 0.040 48.195 ;
    END
  END rd_out[78]
  PIN rd_out[79]
    DIRECTION OUTPUT ;
    USE SIGNAL ;
    SHAPE ABUTMENT ;
    PORT
      LAYER metal3 ;
      RECT 0.000 48.300 0.040 48.335 ;
    END
  END rd_out[79]
  PIN rd_out[80]
    DIRECTION OUTPUT ;
    USE SIGNAL ;
    SHAPE ABUTMENT ;
    PORT
      LAYER metal3 ;
      RECT 0.000 48.440 0.040 48.475 ;
    END
  END rd_out[80]
  PIN rd_out[81]
    DIRECTION OUTPUT ;
    USE SIGNAL ;
    SHAPE ABUTMENT ;
    PORT
      LAYER metal3 ;
      RECT 0.000 48.580 0.040 48.615 ;
    END
  END rd_out[81]
  PIN rd_out[82]
    DIRECTION OUTPUT ;
    USE SIGNAL ;
    SHAPE ABUTMENT ;
    PORT
      LAYER metal3 ;
      RECT 0.000 48.720 0.040 48.755 ;
    END
  END rd_out[82]
  PIN rd_out[83]
    DIRECTION OUTPUT ;
    USE SIGNAL ;
    SHAPE ABUTMENT ;
    PORT
      LAYER metal3 ;
      RECT 0.000 48.860 0.040 48.895 ;
    END
  END rd_out[83]
  PIN rd_out[84]
    DIRECTION OUTPUT ;
    USE SIGNAL ;
    SHAPE ABUTMENT ;
    PORT
      LAYER metal3 ;
      RECT 0.000 49.000 0.040 49.035 ;
    END
  END rd_out[84]
  PIN rd_out[85]
    DIRECTION OUTPUT ;
    USE SIGNAL ;
    SHAPE ABUTMENT ;
    PORT
      LAYER metal3 ;
      RECT 0.000 49.140 0.040 49.175 ;
    END
  END rd_out[85]
  PIN rd_out[86]
    DIRECTION OUTPUT ;
    USE SIGNAL ;
    SHAPE ABUTMENT ;
    PORT
      LAYER metal3 ;
      RECT 0.000 49.280 0.040 49.315 ;
    END
  END rd_out[86]
  PIN rd_out[87]
    DIRECTION OUTPUT ;
    USE SIGNAL ;
    SHAPE ABUTMENT ;
    PORT
      LAYER metal3 ;
      RECT 0.000 49.420 0.040 49.455 ;
    END
  END rd_out[87]
  PIN rd_out[88]
    DIRECTION OUTPUT ;
    USE SIGNAL ;
    SHAPE ABUTMENT ;
    PORT
      LAYER metal3 ;
      RECT 0.000 49.560 0.040 49.595 ;
    END
  END rd_out[88]
  PIN rd_out[89]
    DIRECTION OUTPUT ;
    USE SIGNAL ;
    SHAPE ABUTMENT ;
    PORT
      LAYER metal3 ;
      RECT 0.000 49.700 0.040 49.735 ;
    END
  END rd_out[89]
  PIN rd_out[90]
    DIRECTION OUTPUT ;
    USE SIGNAL ;
    SHAPE ABUTMENT ;
    PORT
      LAYER metal3 ;
      RECT 0.000 49.840 0.040 49.875 ;
    END
  END rd_out[90]
  PIN rd_out[91]
    DIRECTION OUTPUT ;
    USE SIGNAL ;
    SHAPE ABUTMENT ;
    PORT
      LAYER metal3 ;
      RECT 0.000 49.980 0.040 50.015 ;
    END
  END rd_out[91]
  PIN rd_out[92]
    DIRECTION OUTPUT ;
    USE SIGNAL ;
    SHAPE ABUTMENT ;
    PORT
      LAYER metal3 ;
      RECT 0.000 50.120 0.040 50.155 ;
    END
  END rd_out[92]
  PIN rd_out[93]
    DIRECTION OUTPUT ;
    USE SIGNAL ;
    SHAPE ABUTMENT ;
    PORT
      LAYER metal3 ;
      RECT 0.000 50.260 0.040 50.295 ;
    END
  END rd_out[93]
  PIN rd_out[94]
    DIRECTION OUTPUT ;
    USE SIGNAL ;
    SHAPE ABUTMENT ;
    PORT
      LAYER metal3 ;
      RECT 0.000 50.400 0.040 50.435 ;
    END
  END rd_out[94]
  PIN rd_out[95]
    DIRECTION OUTPUT ;
    USE SIGNAL ;
    SHAPE ABUTMENT ;
    PORT
      LAYER metal3 ;
      RECT 0.000 50.540 0.040 50.575 ;
    END
  END rd_out[95]
  PIN rd_out[96]
    DIRECTION OUTPUT ;
    USE SIGNAL ;
    SHAPE ABUTMENT ;
    PORT
      LAYER metal3 ;
      RECT 0.000 50.680 0.040 50.715 ;
    END
  END rd_out[96]
  PIN rd_out[97]
    DIRECTION OUTPUT ;
    USE SIGNAL ;
    SHAPE ABUTMENT ;
    PORT
      LAYER metal3 ;
      RECT 0.000 50.820 0.040 50.855 ;
    END
  END rd_out[97]
  PIN rd_out[98]
    DIRECTION OUTPUT ;
    USE SIGNAL ;
    SHAPE ABUTMENT ;
    PORT
      LAYER metal3 ;
      RECT 0.000 50.960 0.040 50.995 ;
    END
  END rd_out[98]
  PIN rd_out[99]
    DIRECTION OUTPUT ;
    USE SIGNAL ;
    SHAPE ABUTMENT ;
    PORT
      LAYER metal3 ;
      RECT 0.000 51.100 0.040 51.135 ;
    END
  END rd_out[99]
  PIN rd_out[100]
    DIRECTION OUTPUT ;
    USE SIGNAL ;
    SHAPE ABUTMENT ;
    PORT
      LAYER metal3 ;
      RECT 0.000 51.240 0.040 51.275 ;
    END
  END rd_out[100]
  PIN rd_out[101]
    DIRECTION OUTPUT ;
    USE SIGNAL ;
    SHAPE ABUTMENT ;
    PORT
      LAYER metal3 ;
      RECT 0.000 51.380 0.040 51.415 ;
    END
  END rd_out[101]
  PIN rd_out[102]
    DIRECTION OUTPUT ;
    USE SIGNAL ;
    SHAPE ABUTMENT ;
    PORT
      LAYER metal3 ;
      RECT 0.000 51.520 0.040 51.555 ;
    END
  END rd_out[102]
  PIN rd_out[103]
    DIRECTION OUTPUT ;
    USE SIGNAL ;
    SHAPE ABUTMENT ;
    PORT
      LAYER metal3 ;
      RECT 0.000 51.660 0.040 51.695 ;
    END
  END rd_out[103]
  PIN rd_out[104]
    DIRECTION OUTPUT ;
    USE SIGNAL ;
    SHAPE ABUTMENT ;
    PORT
      LAYER metal3 ;
      RECT 0.000 51.800 0.040 51.835 ;
    END
  END rd_out[104]
  PIN rd_out[105]
    DIRECTION OUTPUT ;
    USE SIGNAL ;
    SHAPE ABUTMENT ;
    PORT
      LAYER metal3 ;
      RECT 0.000 51.940 0.040 51.975 ;
    END
  END rd_out[105]
  PIN rd_out[106]
    DIRECTION OUTPUT ;
    USE SIGNAL ;
    SHAPE ABUTMENT ;
    PORT
      LAYER metal3 ;
      RECT 0.000 52.080 0.040 52.115 ;
    END
  END rd_out[106]
  PIN rd_out[107]
    DIRECTION OUTPUT ;
    USE SIGNAL ;
    SHAPE ABUTMENT ;
    PORT
      LAYER metal3 ;
      RECT 0.000 52.220 0.040 52.255 ;
    END
  END rd_out[107]
  PIN rd_out[108]
    DIRECTION OUTPUT ;
    USE SIGNAL ;
    SHAPE ABUTMENT ;
    PORT
      LAYER metal3 ;
      RECT 0.000 52.360 0.040 52.395 ;
    END
  END rd_out[108]
  PIN rd_out[109]
    DIRECTION OUTPUT ;
    USE SIGNAL ;
    SHAPE ABUTMENT ;
    PORT
      LAYER metal3 ;
      RECT 0.000 52.500 0.040 52.535 ;
    END
  END rd_out[109]
  PIN rd_out[110]
    DIRECTION OUTPUT ;
    USE SIGNAL ;
    SHAPE ABUTMENT ;
    PORT
      LAYER metal3 ;
      RECT 0.000 52.640 0.040 52.675 ;
    END
  END rd_out[110]
  PIN rd_out[111]
    DIRECTION OUTPUT ;
    USE SIGNAL ;
    SHAPE ABUTMENT ;
    PORT
      LAYER metal3 ;
      RECT 0.000 52.780 0.040 52.815 ;
    END
  END rd_out[111]
  PIN rd_out[112]
    DIRECTION OUTPUT ;
    USE SIGNAL ;
    SHAPE ABUTMENT ;
    PORT
      LAYER metal3 ;
      RECT 0.000 52.920 0.040 52.955 ;
    END
  END rd_out[112]
  PIN rd_out[113]
    DIRECTION OUTPUT ;
    USE SIGNAL ;
    SHAPE ABUTMENT ;
    PORT
      LAYER metal3 ;
      RECT 0.000 53.060 0.040 53.095 ;
    END
  END rd_out[113]
  PIN rd_out[114]
    DIRECTION OUTPUT ;
    USE SIGNAL ;
    SHAPE ABUTMENT ;
    PORT
      LAYER metal3 ;
      RECT 0.000 53.200 0.040 53.235 ;
    END
  END rd_out[114]
  PIN rd_out[115]
    DIRECTION OUTPUT ;
    USE SIGNAL ;
    SHAPE ABUTMENT ;
    PORT
      LAYER metal3 ;
      RECT 0.000 53.340 0.040 53.375 ;
    END
  END rd_out[115]
  PIN rd_out[116]
    DIRECTION OUTPUT ;
    USE SIGNAL ;
    SHAPE ABUTMENT ;
    PORT
      LAYER metal3 ;
      RECT 0.000 53.480 0.040 53.515 ;
    END
  END rd_out[116]
  PIN rd_out[117]
    DIRECTION OUTPUT ;
    USE SIGNAL ;
    SHAPE ABUTMENT ;
    PORT
      LAYER metal3 ;
      RECT 0.000 53.620 0.040 53.655 ;
    END
  END rd_out[117]
  PIN rd_out[118]
    DIRECTION OUTPUT ;
    USE SIGNAL ;
    SHAPE ABUTMENT ;
    PORT
      LAYER metal3 ;
      RECT 0.000 53.760 0.040 53.795 ;
    END
  END rd_out[118]
  PIN rd_out[119]
    DIRECTION OUTPUT ;
    USE SIGNAL ;
    SHAPE ABUTMENT ;
    PORT
      LAYER metal3 ;
      RECT 0.000 53.900 0.040 53.935 ;
    END
  END rd_out[119]
  PIN rd_out[120]
    DIRECTION OUTPUT ;
    USE SIGNAL ;
    SHAPE ABUTMENT ;
    PORT
      LAYER metal3 ;
      RECT 0.000 54.040 0.040 54.075 ;
    END
  END rd_out[120]
  PIN rd_out[121]
    DIRECTION OUTPUT ;
    USE SIGNAL ;
    SHAPE ABUTMENT ;
    PORT
      LAYER metal3 ;
      RECT 0.000 54.180 0.040 54.215 ;
    END
  END rd_out[121]
  PIN rd_out[122]
    DIRECTION OUTPUT ;
    USE SIGNAL ;
    SHAPE ABUTMENT ;
    PORT
      LAYER metal3 ;
      RECT 0.000 54.320 0.040 54.355 ;
    END
  END rd_out[122]
  PIN rd_out[123]
    DIRECTION OUTPUT ;
    USE SIGNAL ;
    SHAPE ABUTMENT ;
    PORT
      LAYER metal3 ;
      RECT 0.000 54.460 0.040 54.495 ;
    END
  END rd_out[123]
  PIN rd_out[124]
    DIRECTION OUTPUT ;
    USE SIGNAL ;
    SHAPE ABUTMENT ;
    PORT
      LAYER metal3 ;
      RECT 0.000 54.600 0.040 54.635 ;
    END
  END rd_out[124]
  PIN rd_out[125]
    DIRECTION OUTPUT ;
    USE SIGNAL ;
    SHAPE ABUTMENT ;
    PORT
      LAYER metal3 ;
      RECT 0.000 54.740 0.040 54.775 ;
    END
  END rd_out[125]
  PIN rd_out[126]
    DIRECTION OUTPUT ;
    USE SIGNAL ;
    SHAPE ABUTMENT ;
    PORT
      LAYER metal3 ;
      RECT 0.000 54.880 0.040 54.915 ;
    END
  END rd_out[126]
  PIN rd_out[127]
    DIRECTION OUTPUT ;
    USE SIGNAL ;
    SHAPE ABUTMENT ;
    PORT
      LAYER metal3 ;
      RECT 0.000 55.020 0.040 55.055 ;
    END
  END rd_out[127]
  PIN rd_out[128]
    DIRECTION OUTPUT ;
    USE SIGNAL ;
    SHAPE ABUTMENT ;
    PORT
      LAYER metal3 ;
      RECT 0.000 55.160 0.040 55.195 ;
    END
  END rd_out[128]
  PIN rd_out[129]
    DIRECTION OUTPUT ;
    USE SIGNAL ;
    SHAPE ABUTMENT ;
    PORT
      LAYER metal3 ;
      RECT 0.000 55.300 0.040 55.335 ;
    END
  END rd_out[129]
  PIN rd_out[130]
    DIRECTION OUTPUT ;
    USE SIGNAL ;
    SHAPE ABUTMENT ;
    PORT
      LAYER metal3 ;
      RECT 0.000 55.440 0.040 55.475 ;
    END
  END rd_out[130]
  PIN rd_out[131]
    DIRECTION OUTPUT ;
    USE SIGNAL ;
    SHAPE ABUTMENT ;
    PORT
      LAYER metal3 ;
      RECT 0.000 55.580 0.040 55.615 ;
    END
  END rd_out[131]
  PIN rd_out[132]
    DIRECTION OUTPUT ;
    USE SIGNAL ;
    SHAPE ABUTMENT ;
    PORT
      LAYER metal3 ;
      RECT 0.000 55.720 0.040 55.755 ;
    END
  END rd_out[132]
  PIN rd_out[133]
    DIRECTION OUTPUT ;
    USE SIGNAL ;
    SHAPE ABUTMENT ;
    PORT
      LAYER metal3 ;
      RECT 0.000 55.860 0.040 55.895 ;
    END
  END rd_out[133]
  PIN rd_out[134]
    DIRECTION OUTPUT ;
    USE SIGNAL ;
    SHAPE ABUTMENT ;
    PORT
      LAYER metal3 ;
      RECT 0.000 56.000 0.040 56.035 ;
    END
  END rd_out[134]
  PIN rd_out[135]
    DIRECTION OUTPUT ;
    USE SIGNAL ;
    SHAPE ABUTMENT ;
    PORT
      LAYER metal3 ;
      RECT 0.000 56.140 0.040 56.175 ;
    END
  END rd_out[135]
  PIN rd_out[136]
    DIRECTION OUTPUT ;
    USE SIGNAL ;
    SHAPE ABUTMENT ;
    PORT
      LAYER metal3 ;
      RECT 0.000 56.280 0.040 56.315 ;
    END
  END rd_out[136]
  PIN rd_out[137]
    DIRECTION OUTPUT ;
    USE SIGNAL ;
    SHAPE ABUTMENT ;
    PORT
      LAYER metal3 ;
      RECT 0.000 56.420 0.040 56.455 ;
    END
  END rd_out[137]
  PIN rd_out[138]
    DIRECTION OUTPUT ;
    USE SIGNAL ;
    SHAPE ABUTMENT ;
    PORT
      LAYER metal3 ;
      RECT 0.000 56.560 0.040 56.595 ;
    END
  END rd_out[138]
  PIN rd_out[139]
    DIRECTION OUTPUT ;
    USE SIGNAL ;
    SHAPE ABUTMENT ;
    PORT
      LAYER metal3 ;
      RECT 0.000 56.700 0.040 56.735 ;
    END
  END rd_out[139]
  PIN rd_out[140]
    DIRECTION OUTPUT ;
    USE SIGNAL ;
    SHAPE ABUTMENT ;
    PORT
      LAYER metal3 ;
      RECT 0.000 56.840 0.040 56.875 ;
    END
  END rd_out[140]
  PIN rd_out[141]
    DIRECTION OUTPUT ;
    USE SIGNAL ;
    SHAPE ABUTMENT ;
    PORT
      LAYER metal3 ;
      RECT 0.000 56.980 0.040 57.015 ;
    END
  END rd_out[141]
  PIN rd_out[142]
    DIRECTION OUTPUT ;
    USE SIGNAL ;
    SHAPE ABUTMENT ;
    PORT
      LAYER metal3 ;
      RECT 0.000 57.120 0.040 57.155 ;
    END
  END rd_out[142]
  PIN rd_out[143]
    DIRECTION OUTPUT ;
    USE SIGNAL ;
    SHAPE ABUTMENT ;
    PORT
      LAYER metal3 ;
      RECT 0.000 57.260 0.040 57.295 ;
    END
  END rd_out[143]
  PIN rd_out[144]
    DIRECTION OUTPUT ;
    USE SIGNAL ;
    SHAPE ABUTMENT ;
    PORT
      LAYER metal3 ;
      RECT 0.000 57.400 0.040 57.435 ;
    END
  END rd_out[144]
  PIN rd_out[145]
    DIRECTION OUTPUT ;
    USE SIGNAL ;
    SHAPE ABUTMENT ;
    PORT
      LAYER metal3 ;
      RECT 0.000 57.540 0.040 57.575 ;
    END
  END rd_out[145]
  PIN rd_out[146]
    DIRECTION OUTPUT ;
    USE SIGNAL ;
    SHAPE ABUTMENT ;
    PORT
      LAYER metal3 ;
      RECT 0.000 57.680 0.040 57.715 ;
    END
  END rd_out[146]
  PIN rd_out[147]
    DIRECTION OUTPUT ;
    USE SIGNAL ;
    SHAPE ABUTMENT ;
    PORT
      LAYER metal3 ;
      RECT 0.000 57.820 0.040 57.855 ;
    END
  END rd_out[147]
  PIN rd_out[148]
    DIRECTION OUTPUT ;
    USE SIGNAL ;
    SHAPE ABUTMENT ;
    PORT
      LAYER metal3 ;
      RECT 0.000 57.960 0.040 57.995 ;
    END
  END rd_out[148]
  PIN rd_out[149]
    DIRECTION OUTPUT ;
    USE SIGNAL ;
    SHAPE ABUTMENT ;
    PORT
      LAYER metal3 ;
      RECT 0.000 58.100 0.040 58.135 ;
    END
  END rd_out[149]
  PIN rd_out[150]
    DIRECTION OUTPUT ;
    USE SIGNAL ;
    SHAPE ABUTMENT ;
    PORT
      LAYER metal3 ;
      RECT 0.000 58.240 0.040 58.275 ;
    END
  END rd_out[150]
  PIN rd_out[151]
    DIRECTION OUTPUT ;
    USE SIGNAL ;
    SHAPE ABUTMENT ;
    PORT
      LAYER metal3 ;
      RECT 0.000 58.380 0.040 58.415 ;
    END
  END rd_out[151]
  PIN rd_out[152]
    DIRECTION OUTPUT ;
    USE SIGNAL ;
    SHAPE ABUTMENT ;
    PORT
      LAYER metal3 ;
      RECT 0.000 58.520 0.040 58.555 ;
    END
  END rd_out[152]
  PIN rd_out[153]
    DIRECTION OUTPUT ;
    USE SIGNAL ;
    SHAPE ABUTMENT ;
    PORT
      LAYER metal3 ;
      RECT 0.000 58.660 0.040 58.695 ;
    END
  END rd_out[153]
  PIN rd_out[154]
    DIRECTION OUTPUT ;
    USE SIGNAL ;
    SHAPE ABUTMENT ;
    PORT
      LAYER metal3 ;
      RECT 0.000 58.800 0.040 58.835 ;
    END
  END rd_out[154]
  PIN rd_out[155]
    DIRECTION OUTPUT ;
    USE SIGNAL ;
    SHAPE ABUTMENT ;
    PORT
      LAYER metal3 ;
      RECT 0.000 58.940 0.040 58.975 ;
    END
  END rd_out[155]
  PIN rd_out[156]
    DIRECTION OUTPUT ;
    USE SIGNAL ;
    SHAPE ABUTMENT ;
    PORT
      LAYER metal3 ;
      RECT 0.000 59.080 0.040 59.115 ;
    END
  END rd_out[156]
  PIN rd_out[157]
    DIRECTION OUTPUT ;
    USE SIGNAL ;
    SHAPE ABUTMENT ;
    PORT
      LAYER metal3 ;
      RECT 0.000 59.220 0.040 59.255 ;
    END
  END rd_out[157]
  PIN rd_out[158]
    DIRECTION OUTPUT ;
    USE SIGNAL ;
    SHAPE ABUTMENT ;
    PORT
      LAYER metal3 ;
      RECT 0.000 59.360 0.040 59.395 ;
    END
  END rd_out[158]
  PIN rd_out[159]
    DIRECTION OUTPUT ;
    USE SIGNAL ;
    SHAPE ABUTMENT ;
    PORT
      LAYER metal3 ;
      RECT 0.000 59.500 0.040 59.535 ;
    END
  END rd_out[159]
  PIN rd_out[160]
    DIRECTION OUTPUT ;
    USE SIGNAL ;
    SHAPE ABUTMENT ;
    PORT
      LAYER metal3 ;
      RECT 0.000 59.640 0.040 59.675 ;
    END
  END rd_out[160]
  PIN rd_out[161]
    DIRECTION OUTPUT ;
    USE SIGNAL ;
    SHAPE ABUTMENT ;
    PORT
      LAYER metal3 ;
      RECT 0.000 59.780 0.040 59.815 ;
    END
  END rd_out[161]
  PIN rd_out[162]
    DIRECTION OUTPUT ;
    USE SIGNAL ;
    SHAPE ABUTMENT ;
    PORT
      LAYER metal3 ;
      RECT 0.000 59.920 0.040 59.955 ;
    END
  END rd_out[162]
  PIN rd_out[163]
    DIRECTION OUTPUT ;
    USE SIGNAL ;
    SHAPE ABUTMENT ;
    PORT
      LAYER metal3 ;
      RECT 0.000 60.060 0.040 60.095 ;
    END
  END rd_out[163]
  PIN rd_out[164]
    DIRECTION OUTPUT ;
    USE SIGNAL ;
    SHAPE ABUTMENT ;
    PORT
      LAYER metal3 ;
      RECT 0.000 60.200 0.040 60.235 ;
    END
  END rd_out[164]
  PIN rd_out[165]
    DIRECTION OUTPUT ;
    USE SIGNAL ;
    SHAPE ABUTMENT ;
    PORT
      LAYER metal3 ;
      RECT 0.000 60.340 0.040 60.375 ;
    END
  END rd_out[165]
  PIN rd_out[166]
    DIRECTION OUTPUT ;
    USE SIGNAL ;
    SHAPE ABUTMENT ;
    PORT
      LAYER metal3 ;
      RECT 0.000 60.480 0.040 60.515 ;
    END
  END rd_out[166]
  PIN rd_out[167]
    DIRECTION OUTPUT ;
    USE SIGNAL ;
    SHAPE ABUTMENT ;
    PORT
      LAYER metal3 ;
      RECT 0.000 60.620 0.040 60.655 ;
    END
  END rd_out[167]
  PIN rd_out[168]
    DIRECTION OUTPUT ;
    USE SIGNAL ;
    SHAPE ABUTMENT ;
    PORT
      LAYER metal3 ;
      RECT 0.000 60.760 0.040 60.795 ;
    END
  END rd_out[168]
  PIN rd_out[169]
    DIRECTION OUTPUT ;
    USE SIGNAL ;
    SHAPE ABUTMENT ;
    PORT
      LAYER metal3 ;
      RECT 0.000 60.900 0.040 60.935 ;
    END
  END rd_out[169]
  PIN rd_out[170]
    DIRECTION OUTPUT ;
    USE SIGNAL ;
    SHAPE ABUTMENT ;
    PORT
      LAYER metal3 ;
      RECT 0.000 61.040 0.040 61.075 ;
    END
  END rd_out[170]
  PIN rd_out[171]
    DIRECTION OUTPUT ;
    USE SIGNAL ;
    SHAPE ABUTMENT ;
    PORT
      LAYER metal3 ;
      RECT 0.000 61.180 0.040 61.215 ;
    END
  END rd_out[171]
  PIN rd_out[172]
    DIRECTION OUTPUT ;
    USE SIGNAL ;
    SHAPE ABUTMENT ;
    PORT
      LAYER metal3 ;
      RECT 0.000 61.320 0.040 61.355 ;
    END
  END rd_out[172]
  PIN rd_out[173]
    DIRECTION OUTPUT ;
    USE SIGNAL ;
    SHAPE ABUTMENT ;
    PORT
      LAYER metal3 ;
      RECT 0.000 61.460 0.040 61.495 ;
    END
  END rd_out[173]
  PIN rd_out[174]
    DIRECTION OUTPUT ;
    USE SIGNAL ;
    SHAPE ABUTMENT ;
    PORT
      LAYER metal3 ;
      RECT 0.000 61.600 0.040 61.635 ;
    END
  END rd_out[174]
  PIN rd_out[175]
    DIRECTION OUTPUT ;
    USE SIGNAL ;
    SHAPE ABUTMENT ;
    PORT
      LAYER metal3 ;
      RECT 0.000 61.740 0.040 61.775 ;
    END
  END rd_out[175]
  PIN rd_out[176]
    DIRECTION OUTPUT ;
    USE SIGNAL ;
    SHAPE ABUTMENT ;
    PORT
      LAYER metal3 ;
      RECT 0.000 61.880 0.040 61.915 ;
    END
  END rd_out[176]
  PIN rd_out[177]
    DIRECTION OUTPUT ;
    USE SIGNAL ;
    SHAPE ABUTMENT ;
    PORT
      LAYER metal3 ;
      RECT 0.000 62.020 0.040 62.055 ;
    END
  END rd_out[177]
  PIN rd_out[178]
    DIRECTION OUTPUT ;
    USE SIGNAL ;
    SHAPE ABUTMENT ;
    PORT
      LAYER metal3 ;
      RECT 0.000 62.160 0.040 62.195 ;
    END
  END rd_out[178]
  PIN rd_out[179]
    DIRECTION OUTPUT ;
    USE SIGNAL ;
    SHAPE ABUTMENT ;
    PORT
      LAYER metal3 ;
      RECT 0.000 62.300 0.040 62.335 ;
    END
  END rd_out[179]
  PIN rd_out[180]
    DIRECTION OUTPUT ;
    USE SIGNAL ;
    SHAPE ABUTMENT ;
    PORT
      LAYER metal3 ;
      RECT 0.000 62.440 0.040 62.475 ;
    END
  END rd_out[180]
  PIN rd_out[181]
    DIRECTION OUTPUT ;
    USE SIGNAL ;
    SHAPE ABUTMENT ;
    PORT
      LAYER metal3 ;
      RECT 0.000 62.580 0.040 62.615 ;
    END
  END rd_out[181]
  PIN rd_out[182]
    DIRECTION OUTPUT ;
    USE SIGNAL ;
    SHAPE ABUTMENT ;
    PORT
      LAYER metal3 ;
      RECT 0.000 62.720 0.040 62.755 ;
    END
  END rd_out[182]
  PIN rd_out[183]
    DIRECTION OUTPUT ;
    USE SIGNAL ;
    SHAPE ABUTMENT ;
    PORT
      LAYER metal3 ;
      RECT 0.000 62.860 0.040 62.895 ;
    END
  END rd_out[183]
  PIN rd_out[184]
    DIRECTION OUTPUT ;
    USE SIGNAL ;
    SHAPE ABUTMENT ;
    PORT
      LAYER metal3 ;
      RECT 0.000 63.000 0.040 63.035 ;
    END
  END rd_out[184]
  PIN rd_out[185]
    DIRECTION OUTPUT ;
    USE SIGNAL ;
    SHAPE ABUTMENT ;
    PORT
      LAYER metal3 ;
      RECT 0.000 63.140 0.040 63.175 ;
    END
  END rd_out[185]
  PIN rd_out[186]
    DIRECTION OUTPUT ;
    USE SIGNAL ;
    SHAPE ABUTMENT ;
    PORT
      LAYER metal3 ;
      RECT 0.000 63.280 0.040 63.315 ;
    END
  END rd_out[186]
  PIN rd_out[187]
    DIRECTION OUTPUT ;
    USE SIGNAL ;
    SHAPE ABUTMENT ;
    PORT
      LAYER metal3 ;
      RECT 0.000 63.420 0.040 63.455 ;
    END
  END rd_out[187]
  PIN rd_out[188]
    DIRECTION OUTPUT ;
    USE SIGNAL ;
    SHAPE ABUTMENT ;
    PORT
      LAYER metal3 ;
      RECT 0.000 63.560 0.040 63.595 ;
    END
  END rd_out[188]
  PIN rd_out[189]
    DIRECTION OUTPUT ;
    USE SIGNAL ;
    SHAPE ABUTMENT ;
    PORT
      LAYER metal3 ;
      RECT 0.000 63.700 0.040 63.735 ;
    END
  END rd_out[189]
  PIN rd_out[190]
    DIRECTION OUTPUT ;
    USE SIGNAL ;
    SHAPE ABUTMENT ;
    PORT
      LAYER metal3 ;
      RECT 0.000 63.840 0.040 63.875 ;
    END
  END rd_out[190]
  PIN rd_out[191]
    DIRECTION OUTPUT ;
    USE SIGNAL ;
    SHAPE ABUTMENT ;
    PORT
      LAYER metal3 ;
      RECT 0.000 63.980 0.040 64.015 ;
    END
  END rd_out[191]
  PIN rd_out[192]
    DIRECTION OUTPUT ;
    USE SIGNAL ;
    SHAPE ABUTMENT ;
    PORT
      LAYER metal3 ;
      RECT 0.000 64.120 0.040 64.155 ;
    END
  END rd_out[192]
  PIN rd_out[193]
    DIRECTION OUTPUT ;
    USE SIGNAL ;
    SHAPE ABUTMENT ;
    PORT
      LAYER metal3 ;
      RECT 0.000 64.260 0.040 64.295 ;
    END
  END rd_out[193]
  PIN rd_out[194]
    DIRECTION OUTPUT ;
    USE SIGNAL ;
    SHAPE ABUTMENT ;
    PORT
      LAYER metal3 ;
      RECT 0.000 64.400 0.040 64.435 ;
    END
  END rd_out[194]
  PIN rd_out[195]
    DIRECTION OUTPUT ;
    USE SIGNAL ;
    SHAPE ABUTMENT ;
    PORT
      LAYER metal3 ;
      RECT 0.000 64.540 0.040 64.575 ;
    END
  END rd_out[195]
  PIN rd_out[196]
    DIRECTION OUTPUT ;
    USE SIGNAL ;
    SHAPE ABUTMENT ;
    PORT
      LAYER metal3 ;
      RECT 0.000 64.680 0.040 64.715 ;
    END
  END rd_out[196]
  PIN rd_out[197]
    DIRECTION OUTPUT ;
    USE SIGNAL ;
    SHAPE ABUTMENT ;
    PORT
      LAYER metal3 ;
      RECT 0.000 64.820 0.040 64.855 ;
    END
  END rd_out[197]
  PIN rd_out[198]
    DIRECTION OUTPUT ;
    USE SIGNAL ;
    SHAPE ABUTMENT ;
    PORT
      LAYER metal3 ;
      RECT 0.000 64.960 0.040 64.995 ;
    END
  END rd_out[198]
  PIN rd_out[199]
    DIRECTION OUTPUT ;
    USE SIGNAL ;
    SHAPE ABUTMENT ;
    PORT
      LAYER metal3 ;
      RECT 0.000 65.100 0.040 65.135 ;
    END
  END rd_out[199]
  PIN rd_out[200]
    DIRECTION OUTPUT ;
    USE SIGNAL ;
    SHAPE ABUTMENT ;
    PORT
      LAYER metal3 ;
      RECT 0.000 65.240 0.040 65.275 ;
    END
  END rd_out[200]
  PIN rd_out[201]
    DIRECTION OUTPUT ;
    USE SIGNAL ;
    SHAPE ABUTMENT ;
    PORT
      LAYER metal3 ;
      RECT 0.000 65.380 0.040 65.415 ;
    END
  END rd_out[201]
  PIN rd_out[202]
    DIRECTION OUTPUT ;
    USE SIGNAL ;
    SHAPE ABUTMENT ;
    PORT
      LAYER metal3 ;
      RECT 0.000 65.520 0.040 65.555 ;
    END
  END rd_out[202]
  PIN rd_out[203]
    DIRECTION OUTPUT ;
    USE SIGNAL ;
    SHAPE ABUTMENT ;
    PORT
      LAYER metal3 ;
      RECT 0.000 65.660 0.040 65.695 ;
    END
  END rd_out[203]
  PIN rd_out[204]
    DIRECTION OUTPUT ;
    USE SIGNAL ;
    SHAPE ABUTMENT ;
    PORT
      LAYER metal3 ;
      RECT 0.000 65.800 0.040 65.835 ;
    END
  END rd_out[204]
  PIN rd_out[205]
    DIRECTION OUTPUT ;
    USE SIGNAL ;
    SHAPE ABUTMENT ;
    PORT
      LAYER metal3 ;
      RECT 0.000 65.940 0.040 65.975 ;
    END
  END rd_out[205]
  PIN rd_out[206]
    DIRECTION OUTPUT ;
    USE SIGNAL ;
    SHAPE ABUTMENT ;
    PORT
      LAYER metal3 ;
      RECT 0.000 66.080 0.040 66.115 ;
    END
  END rd_out[206]
  PIN rd_out[207]
    DIRECTION OUTPUT ;
    USE SIGNAL ;
    SHAPE ABUTMENT ;
    PORT
      LAYER metal3 ;
      RECT 0.000 66.220 0.040 66.255 ;
    END
  END rd_out[207]
  PIN rd_out[208]
    DIRECTION OUTPUT ;
    USE SIGNAL ;
    SHAPE ABUTMENT ;
    PORT
      LAYER metal3 ;
      RECT 0.000 66.360 0.040 66.395 ;
    END
  END rd_out[208]
  PIN rd_out[209]
    DIRECTION OUTPUT ;
    USE SIGNAL ;
    SHAPE ABUTMENT ;
    PORT
      LAYER metal3 ;
      RECT 0.000 66.500 0.040 66.535 ;
    END
  END rd_out[209]
  PIN rd_out[210]
    DIRECTION OUTPUT ;
    USE SIGNAL ;
    SHAPE ABUTMENT ;
    PORT
      LAYER metal3 ;
      RECT 0.000 66.640 0.040 66.675 ;
    END
  END rd_out[210]
  PIN rd_out[211]
    DIRECTION OUTPUT ;
    USE SIGNAL ;
    SHAPE ABUTMENT ;
    PORT
      LAYER metal3 ;
      RECT 0.000 66.780 0.040 66.815 ;
    END
  END rd_out[211]
  PIN rd_out[212]
    DIRECTION OUTPUT ;
    USE SIGNAL ;
    SHAPE ABUTMENT ;
    PORT
      LAYER metal3 ;
      RECT 0.000 66.920 0.040 66.955 ;
    END
  END rd_out[212]
  PIN rd_out[213]
    DIRECTION OUTPUT ;
    USE SIGNAL ;
    SHAPE ABUTMENT ;
    PORT
      LAYER metal3 ;
      RECT 0.000 67.060 0.040 67.095 ;
    END
  END rd_out[213]
  PIN rd_out[214]
    DIRECTION OUTPUT ;
    USE SIGNAL ;
    SHAPE ABUTMENT ;
    PORT
      LAYER metal3 ;
      RECT 0.000 67.200 0.040 67.235 ;
    END
  END rd_out[214]
  PIN rd_out[215]
    DIRECTION OUTPUT ;
    USE SIGNAL ;
    SHAPE ABUTMENT ;
    PORT
      LAYER metal3 ;
      RECT 0.000 67.340 0.040 67.375 ;
    END
  END rd_out[215]
  PIN rd_out[216]
    DIRECTION OUTPUT ;
    USE SIGNAL ;
    SHAPE ABUTMENT ;
    PORT
      LAYER metal3 ;
      RECT 0.000 67.480 0.040 67.515 ;
    END
  END rd_out[216]
  PIN rd_out[217]
    DIRECTION OUTPUT ;
    USE SIGNAL ;
    SHAPE ABUTMENT ;
    PORT
      LAYER metal3 ;
      RECT 0.000 67.620 0.040 67.655 ;
    END
  END rd_out[217]
  PIN rd_out[218]
    DIRECTION OUTPUT ;
    USE SIGNAL ;
    SHAPE ABUTMENT ;
    PORT
      LAYER metal3 ;
      RECT 0.000 67.760 0.040 67.795 ;
    END
  END rd_out[218]
  PIN rd_out[219]
    DIRECTION OUTPUT ;
    USE SIGNAL ;
    SHAPE ABUTMENT ;
    PORT
      LAYER metal3 ;
      RECT 0.000 67.900 0.040 67.935 ;
    END
  END rd_out[219]
  PIN rd_out[220]
    DIRECTION OUTPUT ;
    USE SIGNAL ;
    SHAPE ABUTMENT ;
    PORT
      LAYER metal3 ;
      RECT 0.000 68.040 0.040 68.075 ;
    END
  END rd_out[220]
  PIN rd_out[221]
    DIRECTION OUTPUT ;
    USE SIGNAL ;
    SHAPE ABUTMENT ;
    PORT
      LAYER metal3 ;
      RECT 0.000 68.180 0.040 68.215 ;
    END
  END rd_out[221]
  PIN rd_out[222]
    DIRECTION OUTPUT ;
    USE SIGNAL ;
    SHAPE ABUTMENT ;
    PORT
      LAYER metal3 ;
      RECT 0.000 68.320 0.040 68.355 ;
    END
  END rd_out[222]
  PIN rd_out[223]
    DIRECTION OUTPUT ;
    USE SIGNAL ;
    SHAPE ABUTMENT ;
    PORT
      LAYER metal3 ;
      RECT 0.000 68.460 0.040 68.495 ;
    END
  END rd_out[223]
  PIN rd_out[224]
    DIRECTION OUTPUT ;
    USE SIGNAL ;
    SHAPE ABUTMENT ;
    PORT
      LAYER metal3 ;
      RECT 0.000 68.600 0.040 68.635 ;
    END
  END rd_out[224]
  PIN rd_out[225]
    DIRECTION OUTPUT ;
    USE SIGNAL ;
    SHAPE ABUTMENT ;
    PORT
      LAYER metal3 ;
      RECT 0.000 68.740 0.040 68.775 ;
    END
  END rd_out[225]
  PIN rd_out[226]
    DIRECTION OUTPUT ;
    USE SIGNAL ;
    SHAPE ABUTMENT ;
    PORT
      LAYER metal3 ;
      RECT 0.000 68.880 0.040 68.915 ;
    END
  END rd_out[226]
  PIN rd_out[227]
    DIRECTION OUTPUT ;
    USE SIGNAL ;
    SHAPE ABUTMENT ;
    PORT
      LAYER metal3 ;
      RECT 0.000 69.020 0.040 69.055 ;
    END
  END rd_out[227]
  PIN rd_out[228]
    DIRECTION OUTPUT ;
    USE SIGNAL ;
    SHAPE ABUTMENT ;
    PORT
      LAYER metal3 ;
      RECT 0.000 69.160 0.040 69.195 ;
    END
  END rd_out[228]
  PIN rd_out[229]
    DIRECTION OUTPUT ;
    USE SIGNAL ;
    SHAPE ABUTMENT ;
    PORT
      LAYER metal3 ;
      RECT 0.000 69.300 0.040 69.335 ;
    END
  END rd_out[229]
  PIN rd_out[230]
    DIRECTION OUTPUT ;
    USE SIGNAL ;
    SHAPE ABUTMENT ;
    PORT
      LAYER metal3 ;
      RECT 0.000 69.440 0.040 69.475 ;
    END
  END rd_out[230]
  PIN rd_out[231]
    DIRECTION OUTPUT ;
    USE SIGNAL ;
    SHAPE ABUTMENT ;
    PORT
      LAYER metal3 ;
      RECT 0.000 69.580 0.040 69.615 ;
    END
  END rd_out[231]
  PIN rd_out[232]
    DIRECTION OUTPUT ;
    USE SIGNAL ;
    SHAPE ABUTMENT ;
    PORT
      LAYER metal3 ;
      RECT 0.000 69.720 0.040 69.755 ;
    END
  END rd_out[232]
  PIN rd_out[233]
    DIRECTION OUTPUT ;
    USE SIGNAL ;
    SHAPE ABUTMENT ;
    PORT
      LAYER metal3 ;
      RECT 0.000 69.860 0.040 69.895 ;
    END
  END rd_out[233]
  PIN rd_out[234]
    DIRECTION OUTPUT ;
    USE SIGNAL ;
    SHAPE ABUTMENT ;
    PORT
      LAYER metal3 ;
      RECT 0.000 70.000 0.040 70.035 ;
    END
  END rd_out[234]
  PIN rd_out[235]
    DIRECTION OUTPUT ;
    USE SIGNAL ;
    SHAPE ABUTMENT ;
    PORT
      LAYER metal3 ;
      RECT 0.000 70.140 0.040 70.175 ;
    END
  END rd_out[235]
  PIN rd_out[236]
    DIRECTION OUTPUT ;
    USE SIGNAL ;
    SHAPE ABUTMENT ;
    PORT
      LAYER metal3 ;
      RECT 0.000 70.280 0.040 70.315 ;
    END
  END rd_out[236]
  PIN rd_out[237]
    DIRECTION OUTPUT ;
    USE SIGNAL ;
    SHAPE ABUTMENT ;
    PORT
      LAYER metal3 ;
      RECT 0.000 70.420 0.040 70.455 ;
    END
  END rd_out[237]
  PIN rd_out[238]
    DIRECTION OUTPUT ;
    USE SIGNAL ;
    SHAPE ABUTMENT ;
    PORT
      LAYER metal3 ;
      RECT 0.000 70.560 0.040 70.595 ;
    END
  END rd_out[238]
  PIN rd_out[239]
    DIRECTION OUTPUT ;
    USE SIGNAL ;
    SHAPE ABUTMENT ;
    PORT
      LAYER metal3 ;
      RECT 0.000 70.700 0.040 70.735 ;
    END
  END rd_out[239]
  PIN rd_out[240]
    DIRECTION OUTPUT ;
    USE SIGNAL ;
    SHAPE ABUTMENT ;
    PORT
      LAYER metal3 ;
      RECT 0.000 70.840 0.040 70.875 ;
    END
  END rd_out[240]
  PIN rd_out[241]
    DIRECTION OUTPUT ;
    USE SIGNAL ;
    SHAPE ABUTMENT ;
    PORT
      LAYER metal3 ;
      RECT 0.000 70.980 0.040 71.015 ;
    END
  END rd_out[241]
  PIN rd_out[242]
    DIRECTION OUTPUT ;
    USE SIGNAL ;
    SHAPE ABUTMENT ;
    PORT
      LAYER metal3 ;
      RECT 0.000 71.120 0.040 71.155 ;
    END
  END rd_out[242]
  PIN rd_out[243]
    DIRECTION OUTPUT ;
    USE SIGNAL ;
    SHAPE ABUTMENT ;
    PORT
      LAYER metal3 ;
      RECT 0.000 71.260 0.040 71.295 ;
    END
  END rd_out[243]
  PIN rd_out[244]
    DIRECTION OUTPUT ;
    USE SIGNAL ;
    SHAPE ABUTMENT ;
    PORT
      LAYER metal3 ;
      RECT 0.000 71.400 0.040 71.435 ;
    END
  END rd_out[244]
  PIN rd_out[245]
    DIRECTION OUTPUT ;
    USE SIGNAL ;
    SHAPE ABUTMENT ;
    PORT
      LAYER metal3 ;
      RECT 0.000 71.540 0.040 71.575 ;
    END
  END rd_out[245]
  PIN rd_out[246]
    DIRECTION OUTPUT ;
    USE SIGNAL ;
    SHAPE ABUTMENT ;
    PORT
      LAYER metal3 ;
      RECT 0.000 71.680 0.040 71.715 ;
    END
  END rd_out[246]
  PIN rd_out[247]
    DIRECTION OUTPUT ;
    USE SIGNAL ;
    SHAPE ABUTMENT ;
    PORT
      LAYER metal3 ;
      RECT 0.000 71.820 0.040 71.855 ;
    END
  END rd_out[247]
  PIN rd_out[248]
    DIRECTION OUTPUT ;
    USE SIGNAL ;
    SHAPE ABUTMENT ;
    PORT
      LAYER metal3 ;
      RECT 0.000 71.960 0.040 71.995 ;
    END
  END rd_out[248]
  PIN rd_out[249]
    DIRECTION OUTPUT ;
    USE SIGNAL ;
    SHAPE ABUTMENT ;
    PORT
      LAYER metal3 ;
      RECT 0.000 72.100 0.040 72.135 ;
    END
  END rd_out[249]
  PIN rd_out[250]
    DIRECTION OUTPUT ;
    USE SIGNAL ;
    SHAPE ABUTMENT ;
    PORT
      LAYER metal3 ;
      RECT 0.000 72.240 0.040 72.275 ;
    END
  END rd_out[250]
  PIN rd_out[251]
    DIRECTION OUTPUT ;
    USE SIGNAL ;
    SHAPE ABUTMENT ;
    PORT
      LAYER metal3 ;
      RECT 0.000 72.380 0.040 72.415 ;
    END
  END rd_out[251]
  PIN rd_out[252]
    DIRECTION OUTPUT ;
    USE SIGNAL ;
    SHAPE ABUTMENT ;
    PORT
      LAYER metal3 ;
      RECT 0.000 72.520 0.040 72.555 ;
    END
  END rd_out[252]
  PIN rd_out[253]
    DIRECTION OUTPUT ;
    USE SIGNAL ;
    SHAPE ABUTMENT ;
    PORT
      LAYER metal3 ;
      RECT 0.000 72.660 0.040 72.695 ;
    END
  END rd_out[253]
  PIN rd_out[254]
    DIRECTION OUTPUT ;
    USE SIGNAL ;
    SHAPE ABUTMENT ;
    PORT
      LAYER metal3 ;
      RECT 0.000 72.800 0.040 72.835 ;
    END
  END rd_out[254]
  PIN rd_out[255]
    DIRECTION OUTPUT ;
    USE SIGNAL ;
    SHAPE ABUTMENT ;
    PORT
      LAYER metal3 ;
      RECT 0.000 72.940 0.040 72.975 ;
    END
  END rd_out[255]
  PIN wd_in[0]
    DIRECTION INPUT ;
    USE SIGNAL ;
    SHAPE ABUTMENT ;
    PORT
      LAYER metal3 ;
      RECT 0.000 73.080 0.040 73.115 ;
    END
  END wd_in[0]
  PIN wd_in[1]
    DIRECTION INPUT ;
    USE SIGNAL ;
    SHAPE ABUTMENT ;
    PORT
      LAYER metal3 ;
      RECT 0.000 73.220 0.040 73.255 ;
    END
  END wd_in[1]
  PIN wd_in[2]
    DIRECTION INPUT ;
    USE SIGNAL ;
    SHAPE ABUTMENT ;
    PORT
      LAYER metal3 ;
      RECT 0.000 73.360 0.040 73.395 ;
    END
  END wd_in[2]
  PIN wd_in[3]
    DIRECTION INPUT ;
    USE SIGNAL ;
    SHAPE ABUTMENT ;
    PORT
      LAYER metal3 ;
      RECT 0.000 73.500 0.040 73.535 ;
    END
  END wd_in[3]
  PIN wd_in[4]
    DIRECTION INPUT ;
    USE SIGNAL ;
    SHAPE ABUTMENT ;
    PORT
      LAYER metal3 ;
      RECT 0.000 73.640 0.040 73.675 ;
    END
  END wd_in[4]
  PIN wd_in[5]
    DIRECTION INPUT ;
    USE SIGNAL ;
    SHAPE ABUTMENT ;
    PORT
      LAYER metal3 ;
      RECT 0.000 73.780 0.040 73.815 ;
    END
  END wd_in[5]
  PIN wd_in[6]
    DIRECTION INPUT ;
    USE SIGNAL ;
    SHAPE ABUTMENT ;
    PORT
      LAYER metal3 ;
      RECT 0.000 73.920 0.040 73.955 ;
    END
  END wd_in[6]
  PIN wd_in[7]
    DIRECTION INPUT ;
    USE SIGNAL ;
    SHAPE ABUTMENT ;
    PORT
      LAYER metal3 ;
      RECT 0.000 74.060 0.040 74.095 ;
    END
  END wd_in[7]
  PIN wd_in[8]
    DIRECTION INPUT ;
    USE SIGNAL ;
    SHAPE ABUTMENT ;
    PORT
      LAYER metal3 ;
      RECT 0.000 74.200 0.040 74.235 ;
    END
  END wd_in[8]
  PIN wd_in[9]
    DIRECTION INPUT ;
    USE SIGNAL ;
    SHAPE ABUTMENT ;
    PORT
      LAYER metal3 ;
      RECT 0.000 74.340 0.040 74.375 ;
    END
  END wd_in[9]
  PIN wd_in[10]
    DIRECTION INPUT ;
    USE SIGNAL ;
    SHAPE ABUTMENT ;
    PORT
      LAYER metal3 ;
      RECT 0.000 74.480 0.040 74.515 ;
    END
  END wd_in[10]
  PIN wd_in[11]
    DIRECTION INPUT ;
    USE SIGNAL ;
    SHAPE ABUTMENT ;
    PORT
      LAYER metal3 ;
      RECT 0.000 74.620 0.040 74.655 ;
    END
  END wd_in[11]
  PIN wd_in[12]
    DIRECTION INPUT ;
    USE SIGNAL ;
    SHAPE ABUTMENT ;
    PORT
      LAYER metal3 ;
      RECT 0.000 74.760 0.040 74.795 ;
    END
  END wd_in[12]
  PIN wd_in[13]
    DIRECTION INPUT ;
    USE SIGNAL ;
    SHAPE ABUTMENT ;
    PORT
      LAYER metal3 ;
      RECT 0.000 74.900 0.040 74.935 ;
    END
  END wd_in[13]
  PIN wd_in[14]
    DIRECTION INPUT ;
    USE SIGNAL ;
    SHAPE ABUTMENT ;
    PORT
      LAYER metal3 ;
      RECT 0.000 75.040 0.040 75.075 ;
    END
  END wd_in[14]
  PIN wd_in[15]
    DIRECTION INPUT ;
    USE SIGNAL ;
    SHAPE ABUTMENT ;
    PORT
      LAYER metal3 ;
      RECT 0.000 75.180 0.040 75.215 ;
    END
  END wd_in[15]
  PIN wd_in[16]
    DIRECTION INPUT ;
    USE SIGNAL ;
    SHAPE ABUTMENT ;
    PORT
      LAYER metal3 ;
      RECT 0.000 75.320 0.040 75.355 ;
    END
  END wd_in[16]
  PIN wd_in[17]
    DIRECTION INPUT ;
    USE SIGNAL ;
    SHAPE ABUTMENT ;
    PORT
      LAYER metal3 ;
      RECT 0.000 75.460 0.040 75.495 ;
    END
  END wd_in[17]
  PIN wd_in[18]
    DIRECTION INPUT ;
    USE SIGNAL ;
    SHAPE ABUTMENT ;
    PORT
      LAYER metal3 ;
      RECT 0.000 75.600 0.040 75.635 ;
    END
  END wd_in[18]
  PIN wd_in[19]
    DIRECTION INPUT ;
    USE SIGNAL ;
    SHAPE ABUTMENT ;
    PORT
      LAYER metal3 ;
      RECT 0.000 75.740 0.040 75.775 ;
    END
  END wd_in[19]
  PIN wd_in[20]
    DIRECTION INPUT ;
    USE SIGNAL ;
    SHAPE ABUTMENT ;
    PORT
      LAYER metal3 ;
      RECT 0.000 75.880 0.040 75.915 ;
    END
  END wd_in[20]
  PIN wd_in[21]
    DIRECTION INPUT ;
    USE SIGNAL ;
    SHAPE ABUTMENT ;
    PORT
      LAYER metal3 ;
      RECT 0.000 76.020 0.040 76.055 ;
    END
  END wd_in[21]
  PIN wd_in[22]
    DIRECTION INPUT ;
    USE SIGNAL ;
    SHAPE ABUTMENT ;
    PORT
      LAYER metal3 ;
      RECT 0.000 76.160 0.040 76.195 ;
    END
  END wd_in[22]
  PIN wd_in[23]
    DIRECTION INPUT ;
    USE SIGNAL ;
    SHAPE ABUTMENT ;
    PORT
      LAYER metal3 ;
      RECT 0.000 76.300 0.040 76.335 ;
    END
  END wd_in[23]
  PIN wd_in[24]
    DIRECTION INPUT ;
    USE SIGNAL ;
    SHAPE ABUTMENT ;
    PORT
      LAYER metal3 ;
      RECT 0.000 76.440 0.040 76.475 ;
    END
  END wd_in[24]
  PIN wd_in[25]
    DIRECTION INPUT ;
    USE SIGNAL ;
    SHAPE ABUTMENT ;
    PORT
      LAYER metal3 ;
      RECT 0.000 76.580 0.040 76.615 ;
    END
  END wd_in[25]
  PIN wd_in[26]
    DIRECTION INPUT ;
    USE SIGNAL ;
    SHAPE ABUTMENT ;
    PORT
      LAYER metal3 ;
      RECT 0.000 76.720 0.040 76.755 ;
    END
  END wd_in[26]
  PIN wd_in[27]
    DIRECTION INPUT ;
    USE SIGNAL ;
    SHAPE ABUTMENT ;
    PORT
      LAYER metal3 ;
      RECT 0.000 76.860 0.040 76.895 ;
    END
  END wd_in[27]
  PIN wd_in[28]
    DIRECTION INPUT ;
    USE SIGNAL ;
    SHAPE ABUTMENT ;
    PORT
      LAYER metal3 ;
      RECT 0.000 77.000 0.040 77.035 ;
    END
  END wd_in[28]
  PIN wd_in[29]
    DIRECTION INPUT ;
    USE SIGNAL ;
    SHAPE ABUTMENT ;
    PORT
      LAYER metal3 ;
      RECT 0.000 77.140 0.040 77.175 ;
    END
  END wd_in[29]
  PIN wd_in[30]
    DIRECTION INPUT ;
    USE SIGNAL ;
    SHAPE ABUTMENT ;
    PORT
      LAYER metal3 ;
      RECT 0.000 77.280 0.040 77.315 ;
    END
  END wd_in[30]
  PIN wd_in[31]
    DIRECTION INPUT ;
    USE SIGNAL ;
    SHAPE ABUTMENT ;
    PORT
      LAYER metal3 ;
      RECT 0.000 77.420 0.040 77.455 ;
    END
  END wd_in[31]
  PIN wd_in[32]
    DIRECTION INPUT ;
    USE SIGNAL ;
    SHAPE ABUTMENT ;
    PORT
      LAYER metal3 ;
      RECT 0.000 77.560 0.040 77.595 ;
    END
  END wd_in[32]
  PIN wd_in[33]
    DIRECTION INPUT ;
    USE SIGNAL ;
    SHAPE ABUTMENT ;
    PORT
      LAYER metal3 ;
      RECT 0.000 77.700 0.040 77.735 ;
    END
  END wd_in[33]
  PIN wd_in[34]
    DIRECTION INPUT ;
    USE SIGNAL ;
    SHAPE ABUTMENT ;
    PORT
      LAYER metal3 ;
      RECT 0.000 77.840 0.040 77.875 ;
    END
  END wd_in[34]
  PIN wd_in[35]
    DIRECTION INPUT ;
    USE SIGNAL ;
    SHAPE ABUTMENT ;
    PORT
      LAYER metal3 ;
      RECT 0.000 77.980 0.040 78.015 ;
    END
  END wd_in[35]
  PIN wd_in[36]
    DIRECTION INPUT ;
    USE SIGNAL ;
    SHAPE ABUTMENT ;
    PORT
      LAYER metal3 ;
      RECT 0.000 78.120 0.040 78.155 ;
    END
  END wd_in[36]
  PIN wd_in[37]
    DIRECTION INPUT ;
    USE SIGNAL ;
    SHAPE ABUTMENT ;
    PORT
      LAYER metal3 ;
      RECT 0.000 78.260 0.040 78.295 ;
    END
  END wd_in[37]
  PIN wd_in[38]
    DIRECTION INPUT ;
    USE SIGNAL ;
    SHAPE ABUTMENT ;
    PORT
      LAYER metal3 ;
      RECT 0.000 78.400 0.040 78.435 ;
    END
  END wd_in[38]
  PIN wd_in[39]
    DIRECTION INPUT ;
    USE SIGNAL ;
    SHAPE ABUTMENT ;
    PORT
      LAYER metal3 ;
      RECT 0.000 78.540 0.040 78.575 ;
    END
  END wd_in[39]
  PIN wd_in[40]
    DIRECTION INPUT ;
    USE SIGNAL ;
    SHAPE ABUTMENT ;
    PORT
      LAYER metal3 ;
      RECT 0.000 78.680 0.040 78.715 ;
    END
  END wd_in[40]
  PIN wd_in[41]
    DIRECTION INPUT ;
    USE SIGNAL ;
    SHAPE ABUTMENT ;
    PORT
      LAYER metal3 ;
      RECT 0.000 78.820 0.040 78.855 ;
    END
  END wd_in[41]
  PIN wd_in[42]
    DIRECTION INPUT ;
    USE SIGNAL ;
    SHAPE ABUTMENT ;
    PORT
      LAYER metal3 ;
      RECT 0.000 78.960 0.040 78.995 ;
    END
  END wd_in[42]
  PIN wd_in[43]
    DIRECTION INPUT ;
    USE SIGNAL ;
    SHAPE ABUTMENT ;
    PORT
      LAYER metal3 ;
      RECT 0.000 79.100 0.040 79.135 ;
    END
  END wd_in[43]
  PIN wd_in[44]
    DIRECTION INPUT ;
    USE SIGNAL ;
    SHAPE ABUTMENT ;
    PORT
      LAYER metal3 ;
      RECT 0.000 79.240 0.040 79.275 ;
    END
  END wd_in[44]
  PIN wd_in[45]
    DIRECTION INPUT ;
    USE SIGNAL ;
    SHAPE ABUTMENT ;
    PORT
      LAYER metal3 ;
      RECT 0.000 79.380 0.040 79.415 ;
    END
  END wd_in[45]
  PIN wd_in[46]
    DIRECTION INPUT ;
    USE SIGNAL ;
    SHAPE ABUTMENT ;
    PORT
      LAYER metal3 ;
      RECT 0.000 79.520 0.040 79.555 ;
    END
  END wd_in[46]
  PIN wd_in[47]
    DIRECTION INPUT ;
    USE SIGNAL ;
    SHAPE ABUTMENT ;
    PORT
      LAYER metal3 ;
      RECT 0.000 79.660 0.040 79.695 ;
    END
  END wd_in[47]
  PIN wd_in[48]
    DIRECTION INPUT ;
    USE SIGNAL ;
    SHAPE ABUTMENT ;
    PORT
      LAYER metal3 ;
      RECT 0.000 79.800 0.040 79.835 ;
    END
  END wd_in[48]
  PIN wd_in[49]
    DIRECTION INPUT ;
    USE SIGNAL ;
    SHAPE ABUTMENT ;
    PORT
      LAYER metal3 ;
      RECT 0.000 79.940 0.040 79.975 ;
    END
  END wd_in[49]
  PIN wd_in[50]
    DIRECTION INPUT ;
    USE SIGNAL ;
    SHAPE ABUTMENT ;
    PORT
      LAYER metal3 ;
      RECT 0.000 80.080 0.040 80.115 ;
    END
  END wd_in[50]
  PIN wd_in[51]
    DIRECTION INPUT ;
    USE SIGNAL ;
    SHAPE ABUTMENT ;
    PORT
      LAYER metal3 ;
      RECT 0.000 80.220 0.040 80.255 ;
    END
  END wd_in[51]
  PIN wd_in[52]
    DIRECTION INPUT ;
    USE SIGNAL ;
    SHAPE ABUTMENT ;
    PORT
      LAYER metal3 ;
      RECT 0.000 80.360 0.040 80.395 ;
    END
  END wd_in[52]
  PIN wd_in[53]
    DIRECTION INPUT ;
    USE SIGNAL ;
    SHAPE ABUTMENT ;
    PORT
      LAYER metal3 ;
      RECT 0.000 80.500 0.040 80.535 ;
    END
  END wd_in[53]
  PIN wd_in[54]
    DIRECTION INPUT ;
    USE SIGNAL ;
    SHAPE ABUTMENT ;
    PORT
      LAYER metal3 ;
      RECT 0.000 80.640 0.040 80.675 ;
    END
  END wd_in[54]
  PIN wd_in[55]
    DIRECTION INPUT ;
    USE SIGNAL ;
    SHAPE ABUTMENT ;
    PORT
      LAYER metal3 ;
      RECT 0.000 80.780 0.040 80.815 ;
    END
  END wd_in[55]
  PIN wd_in[56]
    DIRECTION INPUT ;
    USE SIGNAL ;
    SHAPE ABUTMENT ;
    PORT
      LAYER metal3 ;
      RECT 0.000 80.920 0.040 80.955 ;
    END
  END wd_in[56]
  PIN wd_in[57]
    DIRECTION INPUT ;
    USE SIGNAL ;
    SHAPE ABUTMENT ;
    PORT
      LAYER metal3 ;
      RECT 0.000 81.060 0.040 81.095 ;
    END
  END wd_in[57]
  PIN wd_in[58]
    DIRECTION INPUT ;
    USE SIGNAL ;
    SHAPE ABUTMENT ;
    PORT
      LAYER metal3 ;
      RECT 0.000 81.200 0.040 81.235 ;
    END
  END wd_in[58]
  PIN wd_in[59]
    DIRECTION INPUT ;
    USE SIGNAL ;
    SHAPE ABUTMENT ;
    PORT
      LAYER metal3 ;
      RECT 0.000 81.340 0.040 81.375 ;
    END
  END wd_in[59]
  PIN wd_in[60]
    DIRECTION INPUT ;
    USE SIGNAL ;
    SHAPE ABUTMENT ;
    PORT
      LAYER metal3 ;
      RECT 0.000 81.480 0.040 81.515 ;
    END
  END wd_in[60]
  PIN wd_in[61]
    DIRECTION INPUT ;
    USE SIGNAL ;
    SHAPE ABUTMENT ;
    PORT
      LAYER metal3 ;
      RECT 0.000 81.620 0.040 81.655 ;
    END
  END wd_in[61]
  PIN wd_in[62]
    DIRECTION INPUT ;
    USE SIGNAL ;
    SHAPE ABUTMENT ;
    PORT
      LAYER metal3 ;
      RECT 0.000 81.760 0.040 81.795 ;
    END
  END wd_in[62]
  PIN wd_in[63]
    DIRECTION INPUT ;
    USE SIGNAL ;
    SHAPE ABUTMENT ;
    PORT
      LAYER metal3 ;
      RECT 0.000 81.900 0.040 81.935 ;
    END
  END wd_in[63]
  PIN wd_in[64]
    DIRECTION INPUT ;
    USE SIGNAL ;
    SHAPE ABUTMENT ;
    PORT
      LAYER metal3 ;
      RECT 0.000 82.040 0.040 82.075 ;
    END
  END wd_in[64]
  PIN wd_in[65]
    DIRECTION INPUT ;
    USE SIGNAL ;
    SHAPE ABUTMENT ;
    PORT
      LAYER metal3 ;
      RECT 0.000 82.180 0.040 82.215 ;
    END
  END wd_in[65]
  PIN wd_in[66]
    DIRECTION INPUT ;
    USE SIGNAL ;
    SHAPE ABUTMENT ;
    PORT
      LAYER metal3 ;
      RECT 0.000 82.320 0.040 82.355 ;
    END
  END wd_in[66]
  PIN wd_in[67]
    DIRECTION INPUT ;
    USE SIGNAL ;
    SHAPE ABUTMENT ;
    PORT
      LAYER metal3 ;
      RECT 0.000 82.460 0.040 82.495 ;
    END
  END wd_in[67]
  PIN wd_in[68]
    DIRECTION INPUT ;
    USE SIGNAL ;
    SHAPE ABUTMENT ;
    PORT
      LAYER metal3 ;
      RECT 0.000 82.600 0.040 82.635 ;
    END
  END wd_in[68]
  PIN wd_in[69]
    DIRECTION INPUT ;
    USE SIGNAL ;
    SHAPE ABUTMENT ;
    PORT
      LAYER metal3 ;
      RECT 0.000 82.740 0.040 82.775 ;
    END
  END wd_in[69]
  PIN wd_in[70]
    DIRECTION INPUT ;
    USE SIGNAL ;
    SHAPE ABUTMENT ;
    PORT
      LAYER metal3 ;
      RECT 0.000 82.880 0.040 82.915 ;
    END
  END wd_in[70]
  PIN wd_in[71]
    DIRECTION INPUT ;
    USE SIGNAL ;
    SHAPE ABUTMENT ;
    PORT
      LAYER metal3 ;
      RECT 0.000 83.020 0.040 83.055 ;
    END
  END wd_in[71]
  PIN wd_in[72]
    DIRECTION INPUT ;
    USE SIGNAL ;
    SHAPE ABUTMENT ;
    PORT
      LAYER metal3 ;
      RECT 0.000 83.160 0.040 83.195 ;
    END
  END wd_in[72]
  PIN wd_in[73]
    DIRECTION INPUT ;
    USE SIGNAL ;
    SHAPE ABUTMENT ;
    PORT
      LAYER metal3 ;
      RECT 0.000 83.300 0.040 83.335 ;
    END
  END wd_in[73]
  PIN wd_in[74]
    DIRECTION INPUT ;
    USE SIGNAL ;
    SHAPE ABUTMENT ;
    PORT
      LAYER metal3 ;
      RECT 0.000 83.440 0.040 83.475 ;
    END
  END wd_in[74]
  PIN wd_in[75]
    DIRECTION INPUT ;
    USE SIGNAL ;
    SHAPE ABUTMENT ;
    PORT
      LAYER metal3 ;
      RECT 0.000 83.580 0.040 83.615 ;
    END
  END wd_in[75]
  PIN wd_in[76]
    DIRECTION INPUT ;
    USE SIGNAL ;
    SHAPE ABUTMENT ;
    PORT
      LAYER metal3 ;
      RECT 0.000 83.720 0.040 83.755 ;
    END
  END wd_in[76]
  PIN wd_in[77]
    DIRECTION INPUT ;
    USE SIGNAL ;
    SHAPE ABUTMENT ;
    PORT
      LAYER metal3 ;
      RECT 0.000 83.860 0.040 83.895 ;
    END
  END wd_in[77]
  PIN wd_in[78]
    DIRECTION INPUT ;
    USE SIGNAL ;
    SHAPE ABUTMENT ;
    PORT
      LAYER metal3 ;
      RECT 0.000 84.000 0.040 84.035 ;
    END
  END wd_in[78]
  PIN wd_in[79]
    DIRECTION INPUT ;
    USE SIGNAL ;
    SHAPE ABUTMENT ;
    PORT
      LAYER metal3 ;
      RECT 0.000 84.140 0.040 84.175 ;
    END
  END wd_in[79]
  PIN wd_in[80]
    DIRECTION INPUT ;
    USE SIGNAL ;
    SHAPE ABUTMENT ;
    PORT
      LAYER metal3 ;
      RECT 0.000 84.280 0.040 84.315 ;
    END
  END wd_in[80]
  PIN wd_in[81]
    DIRECTION INPUT ;
    USE SIGNAL ;
    SHAPE ABUTMENT ;
    PORT
      LAYER metal3 ;
      RECT 0.000 84.420 0.040 84.455 ;
    END
  END wd_in[81]
  PIN wd_in[82]
    DIRECTION INPUT ;
    USE SIGNAL ;
    SHAPE ABUTMENT ;
    PORT
      LAYER metal3 ;
      RECT 0.000 84.560 0.040 84.595 ;
    END
  END wd_in[82]
  PIN wd_in[83]
    DIRECTION INPUT ;
    USE SIGNAL ;
    SHAPE ABUTMENT ;
    PORT
      LAYER metal3 ;
      RECT 0.000 84.700 0.040 84.735 ;
    END
  END wd_in[83]
  PIN wd_in[84]
    DIRECTION INPUT ;
    USE SIGNAL ;
    SHAPE ABUTMENT ;
    PORT
      LAYER metal3 ;
      RECT 0.000 84.840 0.040 84.875 ;
    END
  END wd_in[84]
  PIN wd_in[85]
    DIRECTION INPUT ;
    USE SIGNAL ;
    SHAPE ABUTMENT ;
    PORT
      LAYER metal3 ;
      RECT 0.000 84.980 0.040 85.015 ;
    END
  END wd_in[85]
  PIN wd_in[86]
    DIRECTION INPUT ;
    USE SIGNAL ;
    SHAPE ABUTMENT ;
    PORT
      LAYER metal3 ;
      RECT 0.000 85.120 0.040 85.155 ;
    END
  END wd_in[86]
  PIN wd_in[87]
    DIRECTION INPUT ;
    USE SIGNAL ;
    SHAPE ABUTMENT ;
    PORT
      LAYER metal3 ;
      RECT 0.000 85.260 0.040 85.295 ;
    END
  END wd_in[87]
  PIN wd_in[88]
    DIRECTION INPUT ;
    USE SIGNAL ;
    SHAPE ABUTMENT ;
    PORT
      LAYER metal3 ;
      RECT 0.000 85.400 0.040 85.435 ;
    END
  END wd_in[88]
  PIN wd_in[89]
    DIRECTION INPUT ;
    USE SIGNAL ;
    SHAPE ABUTMENT ;
    PORT
      LAYER metal3 ;
      RECT 0.000 85.540 0.040 85.575 ;
    END
  END wd_in[89]
  PIN wd_in[90]
    DIRECTION INPUT ;
    USE SIGNAL ;
    SHAPE ABUTMENT ;
    PORT
      LAYER metal3 ;
      RECT 0.000 85.680 0.040 85.715 ;
    END
  END wd_in[90]
  PIN wd_in[91]
    DIRECTION INPUT ;
    USE SIGNAL ;
    SHAPE ABUTMENT ;
    PORT
      LAYER metal3 ;
      RECT 0.000 85.820 0.040 85.855 ;
    END
  END wd_in[91]
  PIN wd_in[92]
    DIRECTION INPUT ;
    USE SIGNAL ;
    SHAPE ABUTMENT ;
    PORT
      LAYER metal3 ;
      RECT 0.000 85.960 0.040 85.995 ;
    END
  END wd_in[92]
  PIN wd_in[93]
    DIRECTION INPUT ;
    USE SIGNAL ;
    SHAPE ABUTMENT ;
    PORT
      LAYER metal3 ;
      RECT 0.000 86.100 0.040 86.135 ;
    END
  END wd_in[93]
  PIN wd_in[94]
    DIRECTION INPUT ;
    USE SIGNAL ;
    SHAPE ABUTMENT ;
    PORT
      LAYER metal3 ;
      RECT 0.000 86.240 0.040 86.275 ;
    END
  END wd_in[94]
  PIN wd_in[95]
    DIRECTION INPUT ;
    USE SIGNAL ;
    SHAPE ABUTMENT ;
    PORT
      LAYER metal3 ;
      RECT 0.000 86.380 0.040 86.415 ;
    END
  END wd_in[95]
  PIN wd_in[96]
    DIRECTION INPUT ;
    USE SIGNAL ;
    SHAPE ABUTMENT ;
    PORT
      LAYER metal3 ;
      RECT 0.000 86.520 0.040 86.555 ;
    END
  END wd_in[96]
  PIN wd_in[97]
    DIRECTION INPUT ;
    USE SIGNAL ;
    SHAPE ABUTMENT ;
    PORT
      LAYER metal3 ;
      RECT 0.000 86.660 0.040 86.695 ;
    END
  END wd_in[97]
  PIN wd_in[98]
    DIRECTION INPUT ;
    USE SIGNAL ;
    SHAPE ABUTMENT ;
    PORT
      LAYER metal3 ;
      RECT 0.000 86.800 0.040 86.835 ;
    END
  END wd_in[98]
  PIN wd_in[99]
    DIRECTION INPUT ;
    USE SIGNAL ;
    SHAPE ABUTMENT ;
    PORT
      LAYER metal3 ;
      RECT 0.000 86.940 0.040 86.975 ;
    END
  END wd_in[99]
  PIN wd_in[100]
    DIRECTION INPUT ;
    USE SIGNAL ;
    SHAPE ABUTMENT ;
    PORT
      LAYER metal3 ;
      RECT 0.000 87.080 0.040 87.115 ;
    END
  END wd_in[100]
  PIN wd_in[101]
    DIRECTION INPUT ;
    USE SIGNAL ;
    SHAPE ABUTMENT ;
    PORT
      LAYER metal3 ;
      RECT 0.000 87.220 0.040 87.255 ;
    END
  END wd_in[101]
  PIN wd_in[102]
    DIRECTION INPUT ;
    USE SIGNAL ;
    SHAPE ABUTMENT ;
    PORT
      LAYER metal3 ;
      RECT 0.000 87.360 0.040 87.395 ;
    END
  END wd_in[102]
  PIN wd_in[103]
    DIRECTION INPUT ;
    USE SIGNAL ;
    SHAPE ABUTMENT ;
    PORT
      LAYER metal3 ;
      RECT 0.000 87.500 0.040 87.535 ;
    END
  END wd_in[103]
  PIN wd_in[104]
    DIRECTION INPUT ;
    USE SIGNAL ;
    SHAPE ABUTMENT ;
    PORT
      LAYER metal3 ;
      RECT 0.000 87.640 0.040 87.675 ;
    END
  END wd_in[104]
  PIN wd_in[105]
    DIRECTION INPUT ;
    USE SIGNAL ;
    SHAPE ABUTMENT ;
    PORT
      LAYER metal3 ;
      RECT 0.000 87.780 0.040 87.815 ;
    END
  END wd_in[105]
  PIN wd_in[106]
    DIRECTION INPUT ;
    USE SIGNAL ;
    SHAPE ABUTMENT ;
    PORT
      LAYER metal3 ;
      RECT 0.000 87.920 0.040 87.955 ;
    END
  END wd_in[106]
  PIN wd_in[107]
    DIRECTION INPUT ;
    USE SIGNAL ;
    SHAPE ABUTMENT ;
    PORT
      LAYER metal3 ;
      RECT 0.000 88.060 0.040 88.095 ;
    END
  END wd_in[107]
  PIN wd_in[108]
    DIRECTION INPUT ;
    USE SIGNAL ;
    SHAPE ABUTMENT ;
    PORT
      LAYER metal3 ;
      RECT 0.000 88.200 0.040 88.235 ;
    END
  END wd_in[108]
  PIN wd_in[109]
    DIRECTION INPUT ;
    USE SIGNAL ;
    SHAPE ABUTMENT ;
    PORT
      LAYER metal3 ;
      RECT 0.000 88.340 0.040 88.375 ;
    END
  END wd_in[109]
  PIN wd_in[110]
    DIRECTION INPUT ;
    USE SIGNAL ;
    SHAPE ABUTMENT ;
    PORT
      LAYER metal3 ;
      RECT 0.000 88.480 0.040 88.515 ;
    END
  END wd_in[110]
  PIN wd_in[111]
    DIRECTION INPUT ;
    USE SIGNAL ;
    SHAPE ABUTMENT ;
    PORT
      LAYER metal3 ;
      RECT 0.000 88.620 0.040 88.655 ;
    END
  END wd_in[111]
  PIN wd_in[112]
    DIRECTION INPUT ;
    USE SIGNAL ;
    SHAPE ABUTMENT ;
    PORT
      LAYER metal3 ;
      RECT 0.000 88.760 0.040 88.795 ;
    END
  END wd_in[112]
  PIN wd_in[113]
    DIRECTION INPUT ;
    USE SIGNAL ;
    SHAPE ABUTMENT ;
    PORT
      LAYER metal3 ;
      RECT 0.000 88.900 0.040 88.935 ;
    END
  END wd_in[113]
  PIN wd_in[114]
    DIRECTION INPUT ;
    USE SIGNAL ;
    SHAPE ABUTMENT ;
    PORT
      LAYER metal3 ;
      RECT 0.000 89.040 0.040 89.075 ;
    END
  END wd_in[114]
  PIN wd_in[115]
    DIRECTION INPUT ;
    USE SIGNAL ;
    SHAPE ABUTMENT ;
    PORT
      LAYER metal3 ;
      RECT 0.000 89.180 0.040 89.215 ;
    END
  END wd_in[115]
  PIN wd_in[116]
    DIRECTION INPUT ;
    USE SIGNAL ;
    SHAPE ABUTMENT ;
    PORT
      LAYER metal3 ;
      RECT 0.000 89.320 0.040 89.355 ;
    END
  END wd_in[116]
  PIN wd_in[117]
    DIRECTION INPUT ;
    USE SIGNAL ;
    SHAPE ABUTMENT ;
    PORT
      LAYER metal3 ;
      RECT 0.000 89.460 0.040 89.495 ;
    END
  END wd_in[117]
  PIN wd_in[118]
    DIRECTION INPUT ;
    USE SIGNAL ;
    SHAPE ABUTMENT ;
    PORT
      LAYER metal3 ;
      RECT 0.000 89.600 0.040 89.635 ;
    END
  END wd_in[118]
  PIN wd_in[119]
    DIRECTION INPUT ;
    USE SIGNAL ;
    SHAPE ABUTMENT ;
    PORT
      LAYER metal3 ;
      RECT 0.000 89.740 0.040 89.775 ;
    END
  END wd_in[119]
  PIN wd_in[120]
    DIRECTION INPUT ;
    USE SIGNAL ;
    SHAPE ABUTMENT ;
    PORT
      LAYER metal3 ;
      RECT 0.000 89.880 0.040 89.915 ;
    END
  END wd_in[120]
  PIN wd_in[121]
    DIRECTION INPUT ;
    USE SIGNAL ;
    SHAPE ABUTMENT ;
    PORT
      LAYER metal3 ;
      RECT 0.000 90.020 0.040 90.055 ;
    END
  END wd_in[121]
  PIN wd_in[122]
    DIRECTION INPUT ;
    USE SIGNAL ;
    SHAPE ABUTMENT ;
    PORT
      LAYER metal3 ;
      RECT 0.000 90.160 0.040 90.195 ;
    END
  END wd_in[122]
  PIN wd_in[123]
    DIRECTION INPUT ;
    USE SIGNAL ;
    SHAPE ABUTMENT ;
    PORT
      LAYER metal3 ;
      RECT 0.000 90.300 0.040 90.335 ;
    END
  END wd_in[123]
  PIN wd_in[124]
    DIRECTION INPUT ;
    USE SIGNAL ;
    SHAPE ABUTMENT ;
    PORT
      LAYER metal3 ;
      RECT 0.000 90.440 0.040 90.475 ;
    END
  END wd_in[124]
  PIN wd_in[125]
    DIRECTION INPUT ;
    USE SIGNAL ;
    SHAPE ABUTMENT ;
    PORT
      LAYER metal3 ;
      RECT 0.000 90.580 0.040 90.615 ;
    END
  END wd_in[125]
  PIN wd_in[126]
    DIRECTION INPUT ;
    USE SIGNAL ;
    SHAPE ABUTMENT ;
    PORT
      LAYER metal3 ;
      RECT 0.000 90.720 0.040 90.755 ;
    END
  END wd_in[126]
  PIN wd_in[127]
    DIRECTION INPUT ;
    USE SIGNAL ;
    SHAPE ABUTMENT ;
    PORT
      LAYER metal3 ;
      RECT 0.000 90.860 0.040 90.895 ;
    END
  END wd_in[127]
  PIN wd_in[128]
    DIRECTION INPUT ;
    USE SIGNAL ;
    SHAPE ABUTMENT ;
    PORT
      LAYER metal3 ;
      RECT 0.000 91.000 0.040 91.035 ;
    END
  END wd_in[128]
  PIN wd_in[129]
    DIRECTION INPUT ;
    USE SIGNAL ;
    SHAPE ABUTMENT ;
    PORT
      LAYER metal3 ;
      RECT 0.000 91.140 0.040 91.175 ;
    END
  END wd_in[129]
  PIN wd_in[130]
    DIRECTION INPUT ;
    USE SIGNAL ;
    SHAPE ABUTMENT ;
    PORT
      LAYER metal3 ;
      RECT 0.000 91.280 0.040 91.315 ;
    END
  END wd_in[130]
  PIN wd_in[131]
    DIRECTION INPUT ;
    USE SIGNAL ;
    SHAPE ABUTMENT ;
    PORT
      LAYER metal3 ;
      RECT 0.000 91.420 0.040 91.455 ;
    END
  END wd_in[131]
  PIN wd_in[132]
    DIRECTION INPUT ;
    USE SIGNAL ;
    SHAPE ABUTMENT ;
    PORT
      LAYER metal3 ;
      RECT 0.000 91.560 0.040 91.595 ;
    END
  END wd_in[132]
  PIN wd_in[133]
    DIRECTION INPUT ;
    USE SIGNAL ;
    SHAPE ABUTMENT ;
    PORT
      LAYER metal3 ;
      RECT 0.000 91.700 0.040 91.735 ;
    END
  END wd_in[133]
  PIN wd_in[134]
    DIRECTION INPUT ;
    USE SIGNAL ;
    SHAPE ABUTMENT ;
    PORT
      LAYER metal3 ;
      RECT 0.000 91.840 0.040 91.875 ;
    END
  END wd_in[134]
  PIN wd_in[135]
    DIRECTION INPUT ;
    USE SIGNAL ;
    SHAPE ABUTMENT ;
    PORT
      LAYER metal3 ;
      RECT 0.000 91.980 0.040 92.015 ;
    END
  END wd_in[135]
  PIN wd_in[136]
    DIRECTION INPUT ;
    USE SIGNAL ;
    SHAPE ABUTMENT ;
    PORT
      LAYER metal3 ;
      RECT 0.000 92.120 0.040 92.155 ;
    END
  END wd_in[136]
  PIN wd_in[137]
    DIRECTION INPUT ;
    USE SIGNAL ;
    SHAPE ABUTMENT ;
    PORT
      LAYER metal3 ;
      RECT 0.000 92.260 0.040 92.295 ;
    END
  END wd_in[137]
  PIN wd_in[138]
    DIRECTION INPUT ;
    USE SIGNAL ;
    SHAPE ABUTMENT ;
    PORT
      LAYER metal3 ;
      RECT 0.000 92.400 0.040 92.435 ;
    END
  END wd_in[138]
  PIN wd_in[139]
    DIRECTION INPUT ;
    USE SIGNAL ;
    SHAPE ABUTMENT ;
    PORT
      LAYER metal3 ;
      RECT 0.000 92.540 0.040 92.575 ;
    END
  END wd_in[139]
  PIN wd_in[140]
    DIRECTION INPUT ;
    USE SIGNAL ;
    SHAPE ABUTMENT ;
    PORT
      LAYER metal3 ;
      RECT 0.000 92.680 0.040 92.715 ;
    END
  END wd_in[140]
  PIN wd_in[141]
    DIRECTION INPUT ;
    USE SIGNAL ;
    SHAPE ABUTMENT ;
    PORT
      LAYER metal3 ;
      RECT 0.000 92.820 0.040 92.855 ;
    END
  END wd_in[141]
  PIN wd_in[142]
    DIRECTION INPUT ;
    USE SIGNAL ;
    SHAPE ABUTMENT ;
    PORT
      LAYER metal3 ;
      RECT 0.000 92.960 0.040 92.995 ;
    END
  END wd_in[142]
  PIN wd_in[143]
    DIRECTION INPUT ;
    USE SIGNAL ;
    SHAPE ABUTMENT ;
    PORT
      LAYER metal3 ;
      RECT 0.000 93.100 0.040 93.135 ;
    END
  END wd_in[143]
  PIN wd_in[144]
    DIRECTION INPUT ;
    USE SIGNAL ;
    SHAPE ABUTMENT ;
    PORT
      LAYER metal3 ;
      RECT 0.000 93.240 0.040 93.275 ;
    END
  END wd_in[144]
  PIN wd_in[145]
    DIRECTION INPUT ;
    USE SIGNAL ;
    SHAPE ABUTMENT ;
    PORT
      LAYER metal3 ;
      RECT 0.000 93.380 0.040 93.415 ;
    END
  END wd_in[145]
  PIN wd_in[146]
    DIRECTION INPUT ;
    USE SIGNAL ;
    SHAPE ABUTMENT ;
    PORT
      LAYER metal3 ;
      RECT 0.000 93.520 0.040 93.555 ;
    END
  END wd_in[146]
  PIN wd_in[147]
    DIRECTION INPUT ;
    USE SIGNAL ;
    SHAPE ABUTMENT ;
    PORT
      LAYER metal3 ;
      RECT 0.000 93.660 0.040 93.695 ;
    END
  END wd_in[147]
  PIN wd_in[148]
    DIRECTION INPUT ;
    USE SIGNAL ;
    SHAPE ABUTMENT ;
    PORT
      LAYER metal3 ;
      RECT 0.000 93.800 0.040 93.835 ;
    END
  END wd_in[148]
  PIN wd_in[149]
    DIRECTION INPUT ;
    USE SIGNAL ;
    SHAPE ABUTMENT ;
    PORT
      LAYER metal3 ;
      RECT 0.000 93.940 0.040 93.975 ;
    END
  END wd_in[149]
  PIN wd_in[150]
    DIRECTION INPUT ;
    USE SIGNAL ;
    SHAPE ABUTMENT ;
    PORT
      LAYER metal3 ;
      RECT 0.000 94.080 0.040 94.115 ;
    END
  END wd_in[150]
  PIN wd_in[151]
    DIRECTION INPUT ;
    USE SIGNAL ;
    SHAPE ABUTMENT ;
    PORT
      LAYER metal3 ;
      RECT 0.000 94.220 0.040 94.255 ;
    END
  END wd_in[151]
  PIN wd_in[152]
    DIRECTION INPUT ;
    USE SIGNAL ;
    SHAPE ABUTMENT ;
    PORT
      LAYER metal3 ;
      RECT 0.000 94.360 0.040 94.395 ;
    END
  END wd_in[152]
  PIN wd_in[153]
    DIRECTION INPUT ;
    USE SIGNAL ;
    SHAPE ABUTMENT ;
    PORT
      LAYER metal3 ;
      RECT 0.000 94.500 0.040 94.535 ;
    END
  END wd_in[153]
  PIN wd_in[154]
    DIRECTION INPUT ;
    USE SIGNAL ;
    SHAPE ABUTMENT ;
    PORT
      LAYER metal3 ;
      RECT 0.000 94.640 0.040 94.675 ;
    END
  END wd_in[154]
  PIN wd_in[155]
    DIRECTION INPUT ;
    USE SIGNAL ;
    SHAPE ABUTMENT ;
    PORT
      LAYER metal3 ;
      RECT 0.000 94.780 0.040 94.815 ;
    END
  END wd_in[155]
  PIN wd_in[156]
    DIRECTION INPUT ;
    USE SIGNAL ;
    SHAPE ABUTMENT ;
    PORT
      LAYER metal3 ;
      RECT 0.000 94.920 0.040 94.955 ;
    END
  END wd_in[156]
  PIN wd_in[157]
    DIRECTION INPUT ;
    USE SIGNAL ;
    SHAPE ABUTMENT ;
    PORT
      LAYER metal3 ;
      RECT 0.000 95.060 0.040 95.095 ;
    END
  END wd_in[157]
  PIN wd_in[158]
    DIRECTION INPUT ;
    USE SIGNAL ;
    SHAPE ABUTMENT ;
    PORT
      LAYER metal3 ;
      RECT 0.000 95.200 0.040 95.235 ;
    END
  END wd_in[158]
  PIN wd_in[159]
    DIRECTION INPUT ;
    USE SIGNAL ;
    SHAPE ABUTMENT ;
    PORT
      LAYER metal3 ;
      RECT 0.000 95.340 0.040 95.375 ;
    END
  END wd_in[159]
  PIN wd_in[160]
    DIRECTION INPUT ;
    USE SIGNAL ;
    SHAPE ABUTMENT ;
    PORT
      LAYER metal3 ;
      RECT 0.000 95.480 0.040 95.515 ;
    END
  END wd_in[160]
  PIN wd_in[161]
    DIRECTION INPUT ;
    USE SIGNAL ;
    SHAPE ABUTMENT ;
    PORT
      LAYER metal3 ;
      RECT 0.000 95.620 0.040 95.655 ;
    END
  END wd_in[161]
  PIN wd_in[162]
    DIRECTION INPUT ;
    USE SIGNAL ;
    SHAPE ABUTMENT ;
    PORT
      LAYER metal3 ;
      RECT 0.000 95.760 0.040 95.795 ;
    END
  END wd_in[162]
  PIN wd_in[163]
    DIRECTION INPUT ;
    USE SIGNAL ;
    SHAPE ABUTMENT ;
    PORT
      LAYER metal3 ;
      RECT 0.000 95.900 0.040 95.935 ;
    END
  END wd_in[163]
  PIN wd_in[164]
    DIRECTION INPUT ;
    USE SIGNAL ;
    SHAPE ABUTMENT ;
    PORT
      LAYER metal3 ;
      RECT 0.000 96.040 0.040 96.075 ;
    END
  END wd_in[164]
  PIN wd_in[165]
    DIRECTION INPUT ;
    USE SIGNAL ;
    SHAPE ABUTMENT ;
    PORT
      LAYER metal3 ;
      RECT 0.000 96.180 0.040 96.215 ;
    END
  END wd_in[165]
  PIN wd_in[166]
    DIRECTION INPUT ;
    USE SIGNAL ;
    SHAPE ABUTMENT ;
    PORT
      LAYER metal3 ;
      RECT 0.000 96.320 0.040 96.355 ;
    END
  END wd_in[166]
  PIN wd_in[167]
    DIRECTION INPUT ;
    USE SIGNAL ;
    SHAPE ABUTMENT ;
    PORT
      LAYER metal3 ;
      RECT 0.000 96.460 0.040 96.495 ;
    END
  END wd_in[167]
  PIN wd_in[168]
    DIRECTION INPUT ;
    USE SIGNAL ;
    SHAPE ABUTMENT ;
    PORT
      LAYER metal3 ;
      RECT 0.000 96.600 0.040 96.635 ;
    END
  END wd_in[168]
  PIN wd_in[169]
    DIRECTION INPUT ;
    USE SIGNAL ;
    SHAPE ABUTMENT ;
    PORT
      LAYER metal3 ;
      RECT 0.000 96.740 0.040 96.775 ;
    END
  END wd_in[169]
  PIN wd_in[170]
    DIRECTION INPUT ;
    USE SIGNAL ;
    SHAPE ABUTMENT ;
    PORT
      LAYER metal3 ;
      RECT 0.000 96.880 0.040 96.915 ;
    END
  END wd_in[170]
  PIN wd_in[171]
    DIRECTION INPUT ;
    USE SIGNAL ;
    SHAPE ABUTMENT ;
    PORT
      LAYER metal3 ;
      RECT 0.000 97.020 0.040 97.055 ;
    END
  END wd_in[171]
  PIN wd_in[172]
    DIRECTION INPUT ;
    USE SIGNAL ;
    SHAPE ABUTMENT ;
    PORT
      LAYER metal3 ;
      RECT 0.000 97.160 0.040 97.195 ;
    END
  END wd_in[172]
  PIN wd_in[173]
    DIRECTION INPUT ;
    USE SIGNAL ;
    SHAPE ABUTMENT ;
    PORT
      LAYER metal3 ;
      RECT 0.000 97.300 0.040 97.335 ;
    END
  END wd_in[173]
  PIN wd_in[174]
    DIRECTION INPUT ;
    USE SIGNAL ;
    SHAPE ABUTMENT ;
    PORT
      LAYER metal3 ;
      RECT 0.000 97.440 0.040 97.475 ;
    END
  END wd_in[174]
  PIN wd_in[175]
    DIRECTION INPUT ;
    USE SIGNAL ;
    SHAPE ABUTMENT ;
    PORT
      LAYER metal3 ;
      RECT 0.000 97.580 0.040 97.615 ;
    END
  END wd_in[175]
  PIN wd_in[176]
    DIRECTION INPUT ;
    USE SIGNAL ;
    SHAPE ABUTMENT ;
    PORT
      LAYER metal3 ;
      RECT 0.000 97.720 0.040 97.755 ;
    END
  END wd_in[176]
  PIN wd_in[177]
    DIRECTION INPUT ;
    USE SIGNAL ;
    SHAPE ABUTMENT ;
    PORT
      LAYER metal3 ;
      RECT 0.000 97.860 0.040 97.895 ;
    END
  END wd_in[177]
  PIN wd_in[178]
    DIRECTION INPUT ;
    USE SIGNAL ;
    SHAPE ABUTMENT ;
    PORT
      LAYER metal3 ;
      RECT 0.000 98.000 0.040 98.035 ;
    END
  END wd_in[178]
  PIN wd_in[179]
    DIRECTION INPUT ;
    USE SIGNAL ;
    SHAPE ABUTMENT ;
    PORT
      LAYER metal3 ;
      RECT 0.000 98.140 0.040 98.175 ;
    END
  END wd_in[179]
  PIN wd_in[180]
    DIRECTION INPUT ;
    USE SIGNAL ;
    SHAPE ABUTMENT ;
    PORT
      LAYER metal3 ;
      RECT 0.000 98.280 0.040 98.315 ;
    END
  END wd_in[180]
  PIN wd_in[181]
    DIRECTION INPUT ;
    USE SIGNAL ;
    SHAPE ABUTMENT ;
    PORT
      LAYER metal3 ;
      RECT 0.000 98.420 0.040 98.455 ;
    END
  END wd_in[181]
  PIN wd_in[182]
    DIRECTION INPUT ;
    USE SIGNAL ;
    SHAPE ABUTMENT ;
    PORT
      LAYER metal3 ;
      RECT 0.000 98.560 0.040 98.595 ;
    END
  END wd_in[182]
  PIN wd_in[183]
    DIRECTION INPUT ;
    USE SIGNAL ;
    SHAPE ABUTMENT ;
    PORT
      LAYER metal3 ;
      RECT 0.000 98.700 0.040 98.735 ;
    END
  END wd_in[183]
  PIN wd_in[184]
    DIRECTION INPUT ;
    USE SIGNAL ;
    SHAPE ABUTMENT ;
    PORT
      LAYER metal3 ;
      RECT 0.000 98.840 0.040 98.875 ;
    END
  END wd_in[184]
  PIN wd_in[185]
    DIRECTION INPUT ;
    USE SIGNAL ;
    SHAPE ABUTMENT ;
    PORT
      LAYER metal3 ;
      RECT 0.000 98.980 0.040 99.015 ;
    END
  END wd_in[185]
  PIN wd_in[186]
    DIRECTION INPUT ;
    USE SIGNAL ;
    SHAPE ABUTMENT ;
    PORT
      LAYER metal3 ;
      RECT 0.000 99.120 0.040 99.155 ;
    END
  END wd_in[186]
  PIN wd_in[187]
    DIRECTION INPUT ;
    USE SIGNAL ;
    SHAPE ABUTMENT ;
    PORT
      LAYER metal3 ;
      RECT 0.000 99.260 0.040 99.295 ;
    END
  END wd_in[187]
  PIN wd_in[188]
    DIRECTION INPUT ;
    USE SIGNAL ;
    SHAPE ABUTMENT ;
    PORT
      LAYER metal3 ;
      RECT 0.000 99.400 0.040 99.435 ;
    END
  END wd_in[188]
  PIN wd_in[189]
    DIRECTION INPUT ;
    USE SIGNAL ;
    SHAPE ABUTMENT ;
    PORT
      LAYER metal3 ;
      RECT 0.000 99.540 0.040 99.575 ;
    END
  END wd_in[189]
  PIN wd_in[190]
    DIRECTION INPUT ;
    USE SIGNAL ;
    SHAPE ABUTMENT ;
    PORT
      LAYER metal3 ;
      RECT 0.000 99.680 0.040 99.715 ;
    END
  END wd_in[190]
  PIN wd_in[191]
    DIRECTION INPUT ;
    USE SIGNAL ;
    SHAPE ABUTMENT ;
    PORT
      LAYER metal3 ;
      RECT 0.000 99.820 0.040 99.855 ;
    END
  END wd_in[191]
  PIN wd_in[192]
    DIRECTION INPUT ;
    USE SIGNAL ;
    SHAPE ABUTMENT ;
    PORT
      LAYER metal3 ;
      RECT 0.000 99.960 0.040 99.995 ;
    END
  END wd_in[192]
  PIN wd_in[193]
    DIRECTION INPUT ;
    USE SIGNAL ;
    SHAPE ABUTMENT ;
    PORT
      LAYER metal3 ;
      RECT 0.000 100.100 0.040 100.135 ;
    END
  END wd_in[193]
  PIN wd_in[194]
    DIRECTION INPUT ;
    USE SIGNAL ;
    SHAPE ABUTMENT ;
    PORT
      LAYER metal3 ;
      RECT 0.000 100.240 0.040 100.275 ;
    END
  END wd_in[194]
  PIN wd_in[195]
    DIRECTION INPUT ;
    USE SIGNAL ;
    SHAPE ABUTMENT ;
    PORT
      LAYER metal3 ;
      RECT 0.000 100.380 0.040 100.415 ;
    END
  END wd_in[195]
  PIN wd_in[196]
    DIRECTION INPUT ;
    USE SIGNAL ;
    SHAPE ABUTMENT ;
    PORT
      LAYER metal3 ;
      RECT 0.000 100.520 0.040 100.555 ;
    END
  END wd_in[196]
  PIN wd_in[197]
    DIRECTION INPUT ;
    USE SIGNAL ;
    SHAPE ABUTMENT ;
    PORT
      LAYER metal3 ;
      RECT 0.000 100.660 0.040 100.695 ;
    END
  END wd_in[197]
  PIN wd_in[198]
    DIRECTION INPUT ;
    USE SIGNAL ;
    SHAPE ABUTMENT ;
    PORT
      LAYER metal3 ;
      RECT 0.000 100.800 0.040 100.835 ;
    END
  END wd_in[198]
  PIN wd_in[199]
    DIRECTION INPUT ;
    USE SIGNAL ;
    SHAPE ABUTMENT ;
    PORT
      LAYER metal3 ;
      RECT 0.000 100.940 0.040 100.975 ;
    END
  END wd_in[199]
  PIN wd_in[200]
    DIRECTION INPUT ;
    USE SIGNAL ;
    SHAPE ABUTMENT ;
    PORT
      LAYER metal3 ;
      RECT 0.000 101.080 0.040 101.115 ;
    END
  END wd_in[200]
  PIN wd_in[201]
    DIRECTION INPUT ;
    USE SIGNAL ;
    SHAPE ABUTMENT ;
    PORT
      LAYER metal3 ;
      RECT 0.000 101.220 0.040 101.255 ;
    END
  END wd_in[201]
  PIN wd_in[202]
    DIRECTION INPUT ;
    USE SIGNAL ;
    SHAPE ABUTMENT ;
    PORT
      LAYER metal3 ;
      RECT 0.000 101.360 0.040 101.395 ;
    END
  END wd_in[202]
  PIN wd_in[203]
    DIRECTION INPUT ;
    USE SIGNAL ;
    SHAPE ABUTMENT ;
    PORT
      LAYER metal3 ;
      RECT 0.000 101.500 0.040 101.535 ;
    END
  END wd_in[203]
  PIN wd_in[204]
    DIRECTION INPUT ;
    USE SIGNAL ;
    SHAPE ABUTMENT ;
    PORT
      LAYER metal3 ;
      RECT 0.000 101.640 0.040 101.675 ;
    END
  END wd_in[204]
  PIN wd_in[205]
    DIRECTION INPUT ;
    USE SIGNAL ;
    SHAPE ABUTMENT ;
    PORT
      LAYER metal3 ;
      RECT 0.000 101.780 0.040 101.815 ;
    END
  END wd_in[205]
  PIN wd_in[206]
    DIRECTION INPUT ;
    USE SIGNAL ;
    SHAPE ABUTMENT ;
    PORT
      LAYER metal3 ;
      RECT 0.000 101.920 0.040 101.955 ;
    END
  END wd_in[206]
  PIN wd_in[207]
    DIRECTION INPUT ;
    USE SIGNAL ;
    SHAPE ABUTMENT ;
    PORT
      LAYER metal3 ;
      RECT 0.000 102.060 0.040 102.095 ;
    END
  END wd_in[207]
  PIN wd_in[208]
    DIRECTION INPUT ;
    USE SIGNAL ;
    SHAPE ABUTMENT ;
    PORT
      LAYER metal3 ;
      RECT 0.000 102.200 0.040 102.235 ;
    END
  END wd_in[208]
  PIN wd_in[209]
    DIRECTION INPUT ;
    USE SIGNAL ;
    SHAPE ABUTMENT ;
    PORT
      LAYER metal3 ;
      RECT 0.000 102.340 0.040 102.375 ;
    END
  END wd_in[209]
  PIN wd_in[210]
    DIRECTION INPUT ;
    USE SIGNAL ;
    SHAPE ABUTMENT ;
    PORT
      LAYER metal3 ;
      RECT 0.000 102.480 0.040 102.515 ;
    END
  END wd_in[210]
  PIN wd_in[211]
    DIRECTION INPUT ;
    USE SIGNAL ;
    SHAPE ABUTMENT ;
    PORT
      LAYER metal3 ;
      RECT 0.000 102.620 0.040 102.655 ;
    END
  END wd_in[211]
  PIN wd_in[212]
    DIRECTION INPUT ;
    USE SIGNAL ;
    SHAPE ABUTMENT ;
    PORT
      LAYER metal3 ;
      RECT 0.000 102.760 0.040 102.795 ;
    END
  END wd_in[212]
  PIN wd_in[213]
    DIRECTION INPUT ;
    USE SIGNAL ;
    SHAPE ABUTMENT ;
    PORT
      LAYER metal3 ;
      RECT 0.000 102.900 0.040 102.935 ;
    END
  END wd_in[213]
  PIN wd_in[214]
    DIRECTION INPUT ;
    USE SIGNAL ;
    SHAPE ABUTMENT ;
    PORT
      LAYER metal3 ;
      RECT 0.000 103.040 0.040 103.075 ;
    END
  END wd_in[214]
  PIN wd_in[215]
    DIRECTION INPUT ;
    USE SIGNAL ;
    SHAPE ABUTMENT ;
    PORT
      LAYER metal3 ;
      RECT 0.000 103.180 0.040 103.215 ;
    END
  END wd_in[215]
  PIN wd_in[216]
    DIRECTION INPUT ;
    USE SIGNAL ;
    SHAPE ABUTMENT ;
    PORT
      LAYER metal3 ;
      RECT 0.000 103.320 0.040 103.355 ;
    END
  END wd_in[216]
  PIN wd_in[217]
    DIRECTION INPUT ;
    USE SIGNAL ;
    SHAPE ABUTMENT ;
    PORT
      LAYER metal3 ;
      RECT 0.000 103.460 0.040 103.495 ;
    END
  END wd_in[217]
  PIN wd_in[218]
    DIRECTION INPUT ;
    USE SIGNAL ;
    SHAPE ABUTMENT ;
    PORT
      LAYER metal3 ;
      RECT 0.000 103.600 0.040 103.635 ;
    END
  END wd_in[218]
  PIN wd_in[219]
    DIRECTION INPUT ;
    USE SIGNAL ;
    SHAPE ABUTMENT ;
    PORT
      LAYER metal3 ;
      RECT 0.000 103.740 0.040 103.775 ;
    END
  END wd_in[219]
  PIN wd_in[220]
    DIRECTION INPUT ;
    USE SIGNAL ;
    SHAPE ABUTMENT ;
    PORT
      LAYER metal3 ;
      RECT 0.000 103.880 0.040 103.915 ;
    END
  END wd_in[220]
  PIN wd_in[221]
    DIRECTION INPUT ;
    USE SIGNAL ;
    SHAPE ABUTMENT ;
    PORT
      LAYER metal3 ;
      RECT 0.000 104.020 0.040 104.055 ;
    END
  END wd_in[221]
  PIN wd_in[222]
    DIRECTION INPUT ;
    USE SIGNAL ;
    SHAPE ABUTMENT ;
    PORT
      LAYER metal3 ;
      RECT 0.000 104.160 0.040 104.195 ;
    END
  END wd_in[222]
  PIN wd_in[223]
    DIRECTION INPUT ;
    USE SIGNAL ;
    SHAPE ABUTMENT ;
    PORT
      LAYER metal3 ;
      RECT 0.000 104.300 0.040 104.335 ;
    END
  END wd_in[223]
  PIN wd_in[224]
    DIRECTION INPUT ;
    USE SIGNAL ;
    SHAPE ABUTMENT ;
    PORT
      LAYER metal3 ;
      RECT 0.000 104.440 0.040 104.475 ;
    END
  END wd_in[224]
  PIN wd_in[225]
    DIRECTION INPUT ;
    USE SIGNAL ;
    SHAPE ABUTMENT ;
    PORT
      LAYER metal3 ;
      RECT 0.000 104.580 0.040 104.615 ;
    END
  END wd_in[225]
  PIN wd_in[226]
    DIRECTION INPUT ;
    USE SIGNAL ;
    SHAPE ABUTMENT ;
    PORT
      LAYER metal3 ;
      RECT 0.000 104.720 0.040 104.755 ;
    END
  END wd_in[226]
  PIN wd_in[227]
    DIRECTION INPUT ;
    USE SIGNAL ;
    SHAPE ABUTMENT ;
    PORT
      LAYER metal3 ;
      RECT 0.000 104.860 0.040 104.895 ;
    END
  END wd_in[227]
  PIN wd_in[228]
    DIRECTION INPUT ;
    USE SIGNAL ;
    SHAPE ABUTMENT ;
    PORT
      LAYER metal3 ;
      RECT 0.000 105.000 0.040 105.035 ;
    END
  END wd_in[228]
  PIN wd_in[229]
    DIRECTION INPUT ;
    USE SIGNAL ;
    SHAPE ABUTMENT ;
    PORT
      LAYER metal3 ;
      RECT 0.000 105.140 0.040 105.175 ;
    END
  END wd_in[229]
  PIN wd_in[230]
    DIRECTION INPUT ;
    USE SIGNAL ;
    SHAPE ABUTMENT ;
    PORT
      LAYER metal3 ;
      RECT 0.000 105.280 0.040 105.315 ;
    END
  END wd_in[230]
  PIN wd_in[231]
    DIRECTION INPUT ;
    USE SIGNAL ;
    SHAPE ABUTMENT ;
    PORT
      LAYER metal3 ;
      RECT 0.000 105.420 0.040 105.455 ;
    END
  END wd_in[231]
  PIN wd_in[232]
    DIRECTION INPUT ;
    USE SIGNAL ;
    SHAPE ABUTMENT ;
    PORT
      LAYER metal3 ;
      RECT 0.000 105.560 0.040 105.595 ;
    END
  END wd_in[232]
  PIN wd_in[233]
    DIRECTION INPUT ;
    USE SIGNAL ;
    SHAPE ABUTMENT ;
    PORT
      LAYER metal3 ;
      RECT 0.000 105.700 0.040 105.735 ;
    END
  END wd_in[233]
  PIN wd_in[234]
    DIRECTION INPUT ;
    USE SIGNAL ;
    SHAPE ABUTMENT ;
    PORT
      LAYER metal3 ;
      RECT 0.000 105.840 0.040 105.875 ;
    END
  END wd_in[234]
  PIN wd_in[235]
    DIRECTION INPUT ;
    USE SIGNAL ;
    SHAPE ABUTMENT ;
    PORT
      LAYER metal3 ;
      RECT 0.000 105.980 0.040 106.015 ;
    END
  END wd_in[235]
  PIN wd_in[236]
    DIRECTION INPUT ;
    USE SIGNAL ;
    SHAPE ABUTMENT ;
    PORT
      LAYER metal3 ;
      RECT 0.000 106.120 0.040 106.155 ;
    END
  END wd_in[236]
  PIN wd_in[237]
    DIRECTION INPUT ;
    USE SIGNAL ;
    SHAPE ABUTMENT ;
    PORT
      LAYER metal3 ;
      RECT 0.000 106.260 0.040 106.295 ;
    END
  END wd_in[237]
  PIN wd_in[238]
    DIRECTION INPUT ;
    USE SIGNAL ;
    SHAPE ABUTMENT ;
    PORT
      LAYER metal3 ;
      RECT 0.000 106.400 0.040 106.435 ;
    END
  END wd_in[238]
  PIN wd_in[239]
    DIRECTION INPUT ;
    USE SIGNAL ;
    SHAPE ABUTMENT ;
    PORT
      LAYER metal3 ;
      RECT 0.000 106.540 0.040 106.575 ;
    END
  END wd_in[239]
  PIN wd_in[240]
    DIRECTION INPUT ;
    USE SIGNAL ;
    SHAPE ABUTMENT ;
    PORT
      LAYER metal3 ;
      RECT 0.000 106.680 0.040 106.715 ;
    END
  END wd_in[240]
  PIN wd_in[241]
    DIRECTION INPUT ;
    USE SIGNAL ;
    SHAPE ABUTMENT ;
    PORT
      LAYER metal3 ;
      RECT 0.000 106.820 0.040 106.855 ;
    END
  END wd_in[241]
  PIN wd_in[242]
    DIRECTION INPUT ;
    USE SIGNAL ;
    SHAPE ABUTMENT ;
    PORT
      LAYER metal3 ;
      RECT 0.000 106.960 0.040 106.995 ;
    END
  END wd_in[242]
  PIN wd_in[243]
    DIRECTION INPUT ;
    USE SIGNAL ;
    SHAPE ABUTMENT ;
    PORT
      LAYER metal3 ;
      RECT 0.000 107.100 0.040 107.135 ;
    END
  END wd_in[243]
  PIN wd_in[244]
    DIRECTION INPUT ;
    USE SIGNAL ;
    SHAPE ABUTMENT ;
    PORT
      LAYER metal3 ;
      RECT 0.000 107.240 0.040 107.275 ;
    END
  END wd_in[244]
  PIN wd_in[245]
    DIRECTION INPUT ;
    USE SIGNAL ;
    SHAPE ABUTMENT ;
    PORT
      LAYER metal3 ;
      RECT 0.000 107.380 0.040 107.415 ;
    END
  END wd_in[245]
  PIN wd_in[246]
    DIRECTION INPUT ;
    USE SIGNAL ;
    SHAPE ABUTMENT ;
    PORT
      LAYER metal3 ;
      RECT 0.000 107.520 0.040 107.555 ;
    END
  END wd_in[246]
  PIN wd_in[247]
    DIRECTION INPUT ;
    USE SIGNAL ;
    SHAPE ABUTMENT ;
    PORT
      LAYER metal3 ;
      RECT 0.000 107.660 0.040 107.695 ;
    END
  END wd_in[247]
  PIN wd_in[248]
    DIRECTION INPUT ;
    USE SIGNAL ;
    SHAPE ABUTMENT ;
    PORT
      LAYER metal3 ;
      RECT 0.000 107.800 0.040 107.835 ;
    END
  END wd_in[248]
  PIN wd_in[249]
    DIRECTION INPUT ;
    USE SIGNAL ;
    SHAPE ABUTMENT ;
    PORT
      LAYER metal3 ;
      RECT 0.000 107.940 0.040 107.975 ;
    END
  END wd_in[249]
  PIN wd_in[250]
    DIRECTION INPUT ;
    USE SIGNAL ;
    SHAPE ABUTMENT ;
    PORT
      LAYER metal3 ;
      RECT 0.000 108.080 0.040 108.115 ;
    END
  END wd_in[250]
  PIN wd_in[251]
    DIRECTION INPUT ;
    USE SIGNAL ;
    SHAPE ABUTMENT ;
    PORT
      LAYER metal3 ;
      RECT 0.000 108.220 0.040 108.255 ;
    END
  END wd_in[251]
  PIN wd_in[252]
    DIRECTION INPUT ;
    USE SIGNAL ;
    SHAPE ABUTMENT ;
    PORT
      LAYER metal3 ;
      RECT 0.000 108.360 0.040 108.395 ;
    END
  END wd_in[252]
  PIN wd_in[253]
    DIRECTION INPUT ;
    USE SIGNAL ;
    SHAPE ABUTMENT ;
    PORT
      LAYER metal3 ;
      RECT 0.000 108.500 0.040 108.535 ;
    END
  END wd_in[253]
  PIN wd_in[254]
    DIRECTION INPUT ;
    USE SIGNAL ;
    SHAPE ABUTMENT ;
    PORT
      LAYER metal3 ;
      RECT 0.000 108.640 0.040 108.675 ;
    END
  END wd_in[254]
  PIN wd_in[255]
    DIRECTION INPUT ;
    USE SIGNAL ;
    SHAPE ABUTMENT ;
    PORT
      LAYER metal3 ;
      RECT 0.000 108.780 0.040 108.815 ;
    END
  END wd_in[255]
  PIN addr_in[0]
    DIRECTION INPUT ;
    USE SIGNAL ;
    SHAPE ABUTMENT ;
    PORT
      LAYER metal3 ;
      RECT 0.000 108.920 0.040 108.955 ;
    END
  END addr_in[0]
  PIN addr_in[1]
    DIRECTION INPUT ;
    USE SIGNAL ;
    SHAPE ABUTMENT ;
    PORT
      LAYER metal3 ;
      RECT 0.000 109.060 0.040 109.095 ;
    END
  END addr_in[1]
  PIN addr_in[2]
    DIRECTION INPUT ;
    USE SIGNAL ;
    SHAPE ABUTMENT ;
    PORT
      LAYER metal3 ;
      RECT 0.000 109.200 0.040 109.235 ;
    END
  END addr_in[2]
  PIN addr_in[3]
    DIRECTION INPUT ;
    USE SIGNAL ;
    SHAPE ABUTMENT ;
    PORT
      LAYER metal3 ;
      RECT 0.000 109.340 0.040 109.375 ;
    END
  END addr_in[3]
  PIN addr_in[4]
    DIRECTION INPUT ;
    USE SIGNAL ;
    SHAPE ABUTMENT ;
    PORT
      LAYER metal3 ;
      RECT 0.000 109.480 0.040 109.515 ;
    END
  END addr_in[4]
  PIN addr_in[5]
    DIRECTION INPUT ;
    USE SIGNAL ;
    SHAPE ABUTMENT ;
    PORT
      LAYER metal3 ;
      RECT 0.000 109.620 0.040 109.655 ;
    END
  END addr_in[5]
  PIN addr_in[6]
    DIRECTION INPUT ;
    USE SIGNAL ;
    SHAPE ABUTMENT ;
    PORT
      LAYER metal3 ;
      RECT 0.000 109.760 0.040 109.795 ;
    END
  END addr_in[6]
  PIN we_in
    DIRECTION INPUT ;
    USE SIGNAL ;
    SHAPE ABUTMENT ;
    PORT
      LAYER metal3 ;
      RECT 0.000 109.900 0.040 109.935 ;
    END
  END we_in
  PIN ce_in
    DIRECTION INPUT ;
    USE SIGNAL ;
    SHAPE ABUTMENT ;
    PORT
      LAYER metal3 ;
      RECT 0.000 110.040 0.040 110.075 ;
    END
  END ce_in
  PIN clk
    DIRECTION INPUT ;
    USE SIGNAL ;
    SHAPE ABUTMENT ;
    PORT
      LAYER metal3 ;
      RECT 0.000 110.180 0.040 110.215 ;
    END
  END clk
  PIN VSS
    DIRECTION INOUT ;
    USE GROUND ;
    PORT
      LAYER metal4 ;
      RECT 1.528 1.400 1.689 110.550 ;
      RECT 4.101 1.400 4.262 110.550 ;
      RECT 6.674 1.400 6.835 110.550 ;
      RECT 9.247 1.400 9.408 110.550 ;
      RECT 11.820 1.400 11.981 110.550 ;
      RECT 14.393 1.400 14.554 110.550 ;
      RECT 16.966 1.400 17.127 110.550 ;
      RECT 19.539 1.400 19.700 110.550 ;
      RECT 22.112 1.400 22.273 110.550 ;
      RECT 24.686 1.400 24.846 110.550 ;
      RECT 27.259 1.400 27.419 110.550 ;
      RECT 29.832 1.400 29.993 110.550 ;
      RECT 32.405 1.400 32.566 110.550 ;
      RECT 34.978 1.400 35.139 110.550 ;
      RECT 37.551 1.400 37.712 110.550 ;
      RECT 40.124 1.400 40.285 110.550 ;
      RECT 42.697 1.400 42.858 110.550 ;
      RECT 45.270 1.400 45.431 110.550 ;
      RECT 47.843 1.400 48.004 110.550 ;
      RECT 50.416 1.400 50.577 110.550 ;
      RECT 52.989 1.400 53.150 110.550 ;
      RECT 55.563 1.400 55.723 110.550 ;
      RECT 58.136 1.400 58.296 110.550 ;
      RECT 60.709 1.400 60.870 110.550 ;
      RECT 63.282 1.400 63.443 110.550 ;
      RECT 65.855 1.400 66.016 110.550 ;
      RECT 68.428 1.400 68.589 110.550 ;
      RECT 71.001 1.400 71.162 110.550 ;
      RECT 73.574 1.400 73.735 110.550 ;
      RECT 76.147 1.400 76.308 110.550 ;
      RECT 78.720 1.400 78.881 110.550 ;
      RECT 81.293 1.400 81.454 110.550 ;
      RECT 83.866 1.400 84.027 110.550 ;
    END
  END VSS
  PIN VDD
    DIRECTION INOUT ;
    USE POWER ;
    PORT
      LAYER metal4 ;
      RECT 2.814 1.400 2.975 110.550 ;
      RECT 5.387 1.400 5.548 110.550 ;
      RECT 7.960 1.400 8.121 110.550 ;
      RECT 10.534 1.400 10.694 110.550 ;
      RECT 13.107 1.400 13.267 110.550 ;
      RECT 15.680 1.400 15.841 110.550 ;
      RECT 18.253 1.400 18.414 110.550 ;
      RECT 20.826 1.400 20.987 110.550 ;
      RECT 23.399 1.400 23.560 110.550 ;
      RECT 25.972 1.400 26.133 110.550 ;
      RECT 28.545 1.400 28.706 110.550 ;
      RECT 31.118 1.400 31.279 110.550 ;
      RECT 33.691 1.400 33.852 110.550 ;
      RECT 36.264 1.400 36.425 110.550 ;
      RECT 38.837 1.400 38.998 110.550 ;
      RECT 41.411 1.400 41.571 110.550 ;
      RECT 43.984 1.400 44.144 110.550 ;
      RECT 46.557 1.400 46.718 110.550 ;
      RECT 49.130 1.400 49.291 110.550 ;
      RECT 51.703 1.400 51.864 110.550 ;
      RECT 54.276 1.400 54.437 110.550 ;
      RECT 56.849 1.400 57.010 110.550 ;
      RECT 59.422 1.400 59.583 110.550 ;
      RECT 61.995 1.400 62.156 110.550 ;
      RECT 64.568 1.400 64.729 110.550 ;
      RECT 67.141 1.400 67.302 110.550 ;
      RECT 69.715 1.400 69.875 110.550 ;
      RECT 72.288 1.400 72.448 110.550 ;
      RECT 74.861 1.400 75.021 110.550 ;
      RECT 77.434 1.400 77.595 110.550 ;
      RECT 80.007 1.400 80.168 110.550 ;
      RECT 82.580 1.400 82.741 110.550 ;
      RECT 85.153 1.400 85.314 110.550 ;
    END
  END VDD
  OBS
    LAYER metal1 ;
    RECT 0.000 0.000 87.192 111.950 ;
    LAYER metal2 ;
    RECT 0.000 0.000 87.192 111.950 ;
    LAYER metal3 ;
    RECT 0.040 0.000 87.192 111.950 ;
    RECT 0.000 0.000 0.040 1.400 ;
    RECT 0.000 1.435 0.040 1.540 ;
    RECT 0.000 1.575 0.040 1.680 ;
    RECT 0.000 1.715 0.040 1.820 ;
    RECT 0.000 1.855 0.040 1.960 ;
    RECT 0.000 1.995 0.040 2.100 ;
    RECT 0.000 2.135 0.040 2.240 ;
    RECT 0.000 2.275 0.040 2.380 ;
    RECT 0.000 2.415 0.040 2.520 ;
    RECT 0.000 2.555 0.040 2.660 ;
    RECT 0.000 2.695 0.040 2.800 ;
    RECT 0.000 2.835 0.040 2.940 ;
    RECT 0.000 2.975 0.040 3.080 ;
    RECT 0.000 3.115 0.040 3.220 ;
    RECT 0.000 3.255 0.040 3.360 ;
    RECT 0.000 3.395 0.040 3.500 ;
    RECT 0.000 3.535 0.040 3.640 ;
    RECT 0.000 3.675 0.040 3.780 ;
    RECT 0.000 3.815 0.040 3.920 ;
    RECT 0.000 3.955 0.040 4.060 ;
    RECT 0.000 4.095 0.040 4.200 ;
    RECT 0.000 4.235 0.040 4.340 ;
    RECT 0.000 4.375 0.040 4.480 ;
    RECT 0.000 4.515 0.040 4.620 ;
    RECT 0.000 4.655 0.040 4.760 ;
    RECT 0.000 4.795 0.040 4.900 ;
    RECT 0.000 4.935 0.040 5.040 ;
    RECT 0.000 5.075 0.040 5.180 ;
    RECT 0.000 5.215 0.040 5.320 ;
    RECT 0.000 5.355 0.040 5.460 ;
    RECT 0.000 5.495 0.040 5.600 ;
    RECT 0.000 5.635 0.040 5.740 ;
    RECT 0.000 5.775 0.040 5.880 ;
    RECT 0.000 5.915 0.040 6.020 ;
    RECT 0.000 6.055 0.040 6.160 ;
    RECT 0.000 6.195 0.040 6.300 ;
    RECT 0.000 6.335 0.040 6.440 ;
    RECT 0.000 6.475 0.040 6.580 ;
    RECT 0.000 6.615 0.040 6.720 ;
    RECT 0.000 6.755 0.040 6.860 ;
    RECT 0.000 6.895 0.040 7.000 ;
    RECT 0.000 7.035 0.040 7.140 ;
    RECT 0.000 7.175 0.040 7.280 ;
    RECT 0.000 7.315 0.040 7.420 ;
    RECT 0.000 7.455 0.040 7.560 ;
    RECT 0.000 7.595 0.040 7.700 ;
    RECT 0.000 7.735 0.040 7.840 ;
    RECT 0.000 7.875 0.040 7.980 ;
    RECT 0.000 8.015 0.040 8.120 ;
    RECT 0.000 8.155 0.040 8.260 ;
    RECT 0.000 8.295 0.040 8.400 ;
    RECT 0.000 8.435 0.040 8.540 ;
    RECT 0.000 8.575 0.040 8.680 ;
    RECT 0.000 8.715 0.040 8.820 ;
    RECT 0.000 8.855 0.040 8.960 ;
    RECT 0.000 8.995 0.040 9.100 ;
    RECT 0.000 9.135 0.040 9.240 ;
    RECT 0.000 9.275 0.040 9.380 ;
    RECT 0.000 9.415 0.040 9.520 ;
    RECT 0.000 9.555 0.040 9.660 ;
    RECT 0.000 9.695 0.040 9.800 ;
    RECT 0.000 9.835 0.040 9.940 ;
    RECT 0.000 9.975 0.040 10.080 ;
    RECT 0.000 10.115 0.040 10.220 ;
    RECT 0.000 10.255 0.040 10.360 ;
    RECT 0.000 10.395 0.040 10.500 ;
    RECT 0.000 10.535 0.040 10.640 ;
    RECT 0.000 10.675 0.040 10.780 ;
    RECT 0.000 10.815 0.040 10.920 ;
    RECT 0.000 10.955 0.040 11.060 ;
    RECT 0.000 11.095 0.040 11.200 ;
    RECT 0.000 11.235 0.040 11.340 ;
    RECT 0.000 11.375 0.040 11.480 ;
    RECT 0.000 11.515 0.040 11.620 ;
    RECT 0.000 11.655 0.040 11.760 ;
    RECT 0.000 11.795 0.040 11.900 ;
    RECT 0.000 11.935 0.040 12.040 ;
    RECT 0.000 12.075 0.040 12.180 ;
    RECT 0.000 12.215 0.040 12.320 ;
    RECT 0.000 12.355 0.040 12.460 ;
    RECT 0.000 12.495 0.040 12.600 ;
    RECT 0.000 12.635 0.040 12.740 ;
    RECT 0.000 12.775 0.040 12.880 ;
    RECT 0.000 12.915 0.040 13.020 ;
    RECT 0.000 13.055 0.040 13.160 ;
    RECT 0.000 13.195 0.040 13.300 ;
    RECT 0.000 13.335 0.040 13.440 ;
    RECT 0.000 13.475 0.040 13.580 ;
    RECT 0.000 13.615 0.040 13.720 ;
    RECT 0.000 13.755 0.040 13.860 ;
    RECT 0.000 13.895 0.040 14.000 ;
    RECT 0.000 14.035 0.040 14.140 ;
    RECT 0.000 14.175 0.040 14.280 ;
    RECT 0.000 14.315 0.040 14.420 ;
    RECT 0.000 14.455 0.040 14.560 ;
    RECT 0.000 14.595 0.040 14.700 ;
    RECT 0.000 14.735 0.040 14.840 ;
    RECT 0.000 14.875 0.040 14.980 ;
    RECT 0.000 15.015 0.040 15.120 ;
    RECT 0.000 15.155 0.040 15.260 ;
    RECT 0.000 15.295 0.040 15.400 ;
    RECT 0.000 15.435 0.040 15.540 ;
    RECT 0.000 15.575 0.040 15.680 ;
    RECT 0.000 15.715 0.040 15.820 ;
    RECT 0.000 15.855 0.040 15.960 ;
    RECT 0.000 15.995 0.040 16.100 ;
    RECT 0.000 16.135 0.040 16.240 ;
    RECT 0.000 16.275 0.040 16.380 ;
    RECT 0.000 16.415 0.040 16.520 ;
    RECT 0.000 16.555 0.040 16.660 ;
    RECT 0.000 16.695 0.040 16.800 ;
    RECT 0.000 16.835 0.040 16.940 ;
    RECT 0.000 16.975 0.040 17.080 ;
    RECT 0.000 17.115 0.040 17.220 ;
    RECT 0.000 17.255 0.040 17.360 ;
    RECT 0.000 17.395 0.040 17.500 ;
    RECT 0.000 17.535 0.040 17.640 ;
    RECT 0.000 17.675 0.040 17.780 ;
    RECT 0.000 17.815 0.040 17.920 ;
    RECT 0.000 17.955 0.040 18.060 ;
    RECT 0.000 18.095 0.040 18.200 ;
    RECT 0.000 18.235 0.040 18.340 ;
    RECT 0.000 18.375 0.040 18.480 ;
    RECT 0.000 18.515 0.040 18.620 ;
    RECT 0.000 18.655 0.040 18.760 ;
    RECT 0.000 18.795 0.040 18.900 ;
    RECT 0.000 18.935 0.040 19.040 ;
    RECT 0.000 19.075 0.040 19.180 ;
    RECT 0.000 19.215 0.040 19.320 ;
    RECT 0.000 19.355 0.040 19.460 ;
    RECT 0.000 19.495 0.040 19.600 ;
    RECT 0.000 19.635 0.040 19.740 ;
    RECT 0.000 19.775 0.040 19.880 ;
    RECT 0.000 19.915 0.040 20.020 ;
    RECT 0.000 20.055 0.040 20.160 ;
    RECT 0.000 20.195 0.040 20.300 ;
    RECT 0.000 20.335 0.040 20.440 ;
    RECT 0.000 20.475 0.040 20.580 ;
    RECT 0.000 20.615 0.040 20.720 ;
    RECT 0.000 20.755 0.040 20.860 ;
    RECT 0.000 20.895 0.040 21.000 ;
    RECT 0.000 21.035 0.040 21.140 ;
    RECT 0.000 21.175 0.040 21.280 ;
    RECT 0.000 21.315 0.040 21.420 ;
    RECT 0.000 21.455 0.040 21.560 ;
    RECT 0.000 21.595 0.040 21.700 ;
    RECT 0.000 21.735 0.040 21.840 ;
    RECT 0.000 21.875 0.040 21.980 ;
    RECT 0.000 22.015 0.040 22.120 ;
    RECT 0.000 22.155 0.040 22.260 ;
    RECT 0.000 22.295 0.040 22.400 ;
    RECT 0.000 22.435 0.040 22.540 ;
    RECT 0.000 22.575 0.040 22.680 ;
    RECT 0.000 22.715 0.040 22.820 ;
    RECT 0.000 22.855 0.040 22.960 ;
    RECT 0.000 22.995 0.040 23.100 ;
    RECT 0.000 23.135 0.040 23.240 ;
    RECT 0.000 23.275 0.040 23.380 ;
    RECT 0.000 23.415 0.040 23.520 ;
    RECT 0.000 23.555 0.040 23.660 ;
    RECT 0.000 23.695 0.040 23.800 ;
    RECT 0.000 23.835 0.040 23.940 ;
    RECT 0.000 23.975 0.040 24.080 ;
    RECT 0.000 24.115 0.040 24.220 ;
    RECT 0.000 24.255 0.040 24.360 ;
    RECT 0.000 24.395 0.040 24.500 ;
    RECT 0.000 24.535 0.040 24.640 ;
    RECT 0.000 24.675 0.040 24.780 ;
    RECT 0.000 24.815 0.040 24.920 ;
    RECT 0.000 24.955 0.040 25.060 ;
    RECT 0.000 25.095 0.040 25.200 ;
    RECT 0.000 25.235 0.040 25.340 ;
    RECT 0.000 25.375 0.040 25.480 ;
    RECT 0.000 25.515 0.040 25.620 ;
    RECT 0.000 25.655 0.040 25.760 ;
    RECT 0.000 25.795 0.040 25.900 ;
    RECT 0.000 25.935 0.040 26.040 ;
    RECT 0.000 26.075 0.040 26.180 ;
    RECT 0.000 26.215 0.040 26.320 ;
    RECT 0.000 26.355 0.040 26.460 ;
    RECT 0.000 26.495 0.040 26.600 ;
    RECT 0.000 26.635 0.040 26.740 ;
    RECT 0.000 26.775 0.040 26.880 ;
    RECT 0.000 26.915 0.040 27.020 ;
    RECT 0.000 27.055 0.040 27.160 ;
    RECT 0.000 27.195 0.040 27.300 ;
    RECT 0.000 27.335 0.040 27.440 ;
    RECT 0.000 27.475 0.040 27.580 ;
    RECT 0.000 27.615 0.040 27.720 ;
    RECT 0.000 27.755 0.040 27.860 ;
    RECT 0.000 27.895 0.040 28.000 ;
    RECT 0.000 28.035 0.040 28.140 ;
    RECT 0.000 28.175 0.040 28.280 ;
    RECT 0.000 28.315 0.040 28.420 ;
    RECT 0.000 28.455 0.040 28.560 ;
    RECT 0.000 28.595 0.040 28.700 ;
    RECT 0.000 28.735 0.040 28.840 ;
    RECT 0.000 28.875 0.040 28.980 ;
    RECT 0.000 29.015 0.040 29.120 ;
    RECT 0.000 29.155 0.040 29.260 ;
    RECT 0.000 29.295 0.040 29.400 ;
    RECT 0.000 29.435 0.040 29.540 ;
    RECT 0.000 29.575 0.040 29.680 ;
    RECT 0.000 29.715 0.040 29.820 ;
    RECT 0.000 29.855 0.040 29.960 ;
    RECT 0.000 29.995 0.040 30.100 ;
    RECT 0.000 30.135 0.040 30.240 ;
    RECT 0.000 30.275 0.040 30.380 ;
    RECT 0.000 30.415 0.040 30.520 ;
    RECT 0.000 30.555 0.040 30.660 ;
    RECT 0.000 30.695 0.040 30.800 ;
    RECT 0.000 30.835 0.040 30.940 ;
    RECT 0.000 30.975 0.040 31.080 ;
    RECT 0.000 31.115 0.040 31.220 ;
    RECT 0.000 31.255 0.040 31.360 ;
    RECT 0.000 31.395 0.040 31.500 ;
    RECT 0.000 31.535 0.040 31.640 ;
    RECT 0.000 31.675 0.040 31.780 ;
    RECT 0.000 31.815 0.040 31.920 ;
    RECT 0.000 31.955 0.040 32.060 ;
    RECT 0.000 32.095 0.040 32.200 ;
    RECT 0.000 32.235 0.040 32.340 ;
    RECT 0.000 32.375 0.040 32.480 ;
    RECT 0.000 32.515 0.040 32.620 ;
    RECT 0.000 32.655 0.040 32.760 ;
    RECT 0.000 32.795 0.040 32.900 ;
    RECT 0.000 32.935 0.040 33.040 ;
    RECT 0.000 33.075 0.040 33.180 ;
    RECT 0.000 33.215 0.040 33.320 ;
    RECT 0.000 33.355 0.040 33.460 ;
    RECT 0.000 33.495 0.040 33.600 ;
    RECT 0.000 33.635 0.040 33.740 ;
    RECT 0.000 33.775 0.040 33.880 ;
    RECT 0.000 33.915 0.040 34.020 ;
    RECT 0.000 34.055 0.040 34.160 ;
    RECT 0.000 34.195 0.040 34.300 ;
    RECT 0.000 34.335 0.040 34.440 ;
    RECT 0.000 34.475 0.040 34.580 ;
    RECT 0.000 34.615 0.040 34.720 ;
    RECT 0.000 34.755 0.040 34.860 ;
    RECT 0.000 34.895 0.040 35.000 ;
    RECT 0.000 35.035 0.040 35.140 ;
    RECT 0.000 35.175 0.040 35.280 ;
    RECT 0.000 35.315 0.040 35.420 ;
    RECT 0.000 35.455 0.040 35.560 ;
    RECT 0.000 35.595 0.040 35.700 ;
    RECT 0.000 35.735 0.040 35.840 ;
    RECT 0.000 35.875 0.040 35.980 ;
    RECT 0.000 36.015 0.040 36.120 ;
    RECT 0.000 36.155 0.040 36.260 ;
    RECT 0.000 36.295 0.040 36.400 ;
    RECT 0.000 36.435 0.040 36.540 ;
    RECT 0.000 36.575 0.040 36.680 ;
    RECT 0.000 36.715 0.040 36.820 ;
    RECT 0.000 36.855 0.040 36.960 ;
    RECT 0.000 36.995 0.040 37.100 ;
    RECT 0.000 37.135 0.040 37.240 ;
    RECT 0.000 37.275 0.040 37.380 ;
    RECT 0.000 37.415 0.040 37.520 ;
    RECT 0.000 37.555 0.040 37.660 ;
    RECT 0.000 37.695 0.040 37.800 ;
    RECT 0.000 37.835 0.040 37.940 ;
    RECT 0.000 37.975 0.040 38.080 ;
    RECT 0.000 38.115 0.040 38.220 ;
    RECT 0.000 38.255 0.040 38.360 ;
    RECT 0.000 38.395 0.040 38.500 ;
    RECT 0.000 38.535 0.040 38.640 ;
    RECT 0.000 38.675 0.040 38.780 ;
    RECT 0.000 38.815 0.040 38.920 ;
    RECT 0.000 38.955 0.040 39.060 ;
    RECT 0.000 39.095 0.040 39.200 ;
    RECT 0.000 39.235 0.040 39.340 ;
    RECT 0.000 39.375 0.040 39.480 ;
    RECT 0.000 39.515 0.040 39.620 ;
    RECT 0.000 39.655 0.040 39.760 ;
    RECT 0.000 39.795 0.040 39.900 ;
    RECT 0.000 39.935 0.040 40.040 ;
    RECT 0.000 40.075 0.040 40.180 ;
    RECT 0.000 40.215 0.040 40.320 ;
    RECT 0.000 40.355 0.040 40.460 ;
    RECT 0.000 40.495 0.040 40.600 ;
    RECT 0.000 40.635 0.040 40.740 ;
    RECT 0.000 40.775 0.040 40.880 ;
    RECT 0.000 40.915 0.040 41.020 ;
    RECT 0.000 41.055 0.040 41.160 ;
    RECT 0.000 41.195 0.040 41.300 ;
    RECT 0.000 41.335 0.040 41.440 ;
    RECT 0.000 41.475 0.040 41.580 ;
    RECT 0.000 41.615 0.040 41.720 ;
    RECT 0.000 41.755 0.040 41.860 ;
    RECT 0.000 41.895 0.040 42.000 ;
    RECT 0.000 42.035 0.040 42.140 ;
    RECT 0.000 42.175 0.040 42.280 ;
    RECT 0.000 42.315 0.040 42.420 ;
    RECT 0.000 42.455 0.040 42.560 ;
    RECT 0.000 42.595 0.040 42.700 ;
    RECT 0.000 42.735 0.040 42.840 ;
    RECT 0.000 42.875 0.040 42.980 ;
    RECT 0.000 43.015 0.040 43.120 ;
    RECT 0.000 43.155 0.040 43.260 ;
    RECT 0.000 43.295 0.040 43.400 ;
    RECT 0.000 43.435 0.040 43.540 ;
    RECT 0.000 43.575 0.040 43.680 ;
    RECT 0.000 43.715 0.040 43.820 ;
    RECT 0.000 43.855 0.040 43.960 ;
    RECT 0.000 43.995 0.040 44.100 ;
    RECT 0.000 44.135 0.040 44.240 ;
    RECT 0.000 44.275 0.040 44.380 ;
    RECT 0.000 44.415 0.040 44.520 ;
    RECT 0.000 44.555 0.040 44.660 ;
    RECT 0.000 44.695 0.040 44.800 ;
    RECT 0.000 44.835 0.040 44.940 ;
    RECT 0.000 44.975 0.040 45.080 ;
    RECT 0.000 45.115 0.040 45.220 ;
    RECT 0.000 45.255 0.040 45.360 ;
    RECT 0.000 45.395 0.040 45.500 ;
    RECT 0.000 45.535 0.040 45.640 ;
    RECT 0.000 45.675 0.040 45.780 ;
    RECT 0.000 45.815 0.040 45.920 ;
    RECT 0.000 45.955 0.040 46.060 ;
    RECT 0.000 46.095 0.040 46.200 ;
    RECT 0.000 46.235 0.040 46.340 ;
    RECT 0.000 46.375 0.040 46.480 ;
    RECT 0.000 46.515 0.040 46.620 ;
    RECT 0.000 46.655 0.040 46.760 ;
    RECT 0.000 46.795 0.040 46.900 ;
    RECT 0.000 46.935 0.040 47.040 ;
    RECT 0.000 47.075 0.040 47.180 ;
    RECT 0.000 47.215 0.040 47.320 ;
    RECT 0.000 47.355 0.040 47.460 ;
    RECT 0.000 47.495 0.040 47.600 ;
    RECT 0.000 47.635 0.040 47.740 ;
    RECT 0.000 47.775 0.040 47.880 ;
    RECT 0.000 47.915 0.040 48.020 ;
    RECT 0.000 48.055 0.040 48.160 ;
    RECT 0.000 48.195 0.040 48.300 ;
    RECT 0.000 48.335 0.040 48.440 ;
    RECT 0.000 48.475 0.040 48.580 ;
    RECT 0.000 48.615 0.040 48.720 ;
    RECT 0.000 48.755 0.040 48.860 ;
    RECT 0.000 48.895 0.040 49.000 ;
    RECT 0.000 49.035 0.040 49.140 ;
    RECT 0.000 49.175 0.040 49.280 ;
    RECT 0.000 49.315 0.040 49.420 ;
    RECT 0.000 49.455 0.040 49.560 ;
    RECT 0.000 49.595 0.040 49.700 ;
    RECT 0.000 49.735 0.040 49.840 ;
    RECT 0.000 49.875 0.040 49.980 ;
    RECT 0.000 50.015 0.040 50.120 ;
    RECT 0.000 50.155 0.040 50.260 ;
    RECT 0.000 50.295 0.040 50.400 ;
    RECT 0.000 50.435 0.040 50.540 ;
    RECT 0.000 50.575 0.040 50.680 ;
    RECT 0.000 50.715 0.040 50.820 ;
    RECT 0.000 50.855 0.040 50.960 ;
    RECT 0.000 50.995 0.040 51.100 ;
    RECT 0.000 51.135 0.040 51.240 ;
    RECT 0.000 51.275 0.040 51.380 ;
    RECT 0.000 51.415 0.040 51.520 ;
    RECT 0.000 51.555 0.040 51.660 ;
    RECT 0.000 51.695 0.040 51.800 ;
    RECT 0.000 51.835 0.040 51.940 ;
    RECT 0.000 51.975 0.040 52.080 ;
    RECT 0.000 52.115 0.040 52.220 ;
    RECT 0.000 52.255 0.040 52.360 ;
    RECT 0.000 52.395 0.040 52.500 ;
    RECT 0.000 52.535 0.040 52.640 ;
    RECT 0.000 52.675 0.040 52.780 ;
    RECT 0.000 52.815 0.040 52.920 ;
    RECT 0.000 52.955 0.040 53.060 ;
    RECT 0.000 53.095 0.040 53.200 ;
    RECT 0.000 53.235 0.040 53.340 ;
    RECT 0.000 53.375 0.040 53.480 ;
    RECT 0.000 53.515 0.040 53.620 ;
    RECT 0.000 53.655 0.040 53.760 ;
    RECT 0.000 53.795 0.040 53.900 ;
    RECT 0.000 53.935 0.040 54.040 ;
    RECT 0.000 54.075 0.040 54.180 ;
    RECT 0.000 54.215 0.040 54.320 ;
    RECT 0.000 54.355 0.040 54.460 ;
    RECT 0.000 54.495 0.040 54.600 ;
    RECT 0.000 54.635 0.040 54.740 ;
    RECT 0.000 54.775 0.040 54.880 ;
    RECT 0.000 54.915 0.040 55.020 ;
    RECT 0.000 55.055 0.040 55.160 ;
    RECT 0.000 55.195 0.040 55.300 ;
    RECT 0.000 55.335 0.040 55.440 ;
    RECT 0.000 55.475 0.040 55.580 ;
    RECT 0.000 55.615 0.040 55.720 ;
    RECT 0.000 55.755 0.040 55.860 ;
    RECT 0.000 55.895 0.040 56.000 ;
    RECT 0.000 56.035 0.040 56.140 ;
    RECT 0.000 56.175 0.040 56.280 ;
    RECT 0.000 56.315 0.040 56.420 ;
    RECT 0.000 56.455 0.040 56.560 ;
    RECT 0.000 56.595 0.040 56.700 ;
    RECT 0.000 56.735 0.040 56.840 ;
    RECT 0.000 56.875 0.040 56.980 ;
    RECT 0.000 57.015 0.040 57.120 ;
    RECT 0.000 57.155 0.040 57.260 ;
    RECT 0.000 57.295 0.040 57.400 ;
    RECT 0.000 57.435 0.040 57.540 ;
    RECT 0.000 57.575 0.040 57.680 ;
    RECT 0.000 57.715 0.040 57.820 ;
    RECT 0.000 57.855 0.040 57.960 ;
    RECT 0.000 57.995 0.040 58.100 ;
    RECT 0.000 58.135 0.040 58.240 ;
    RECT 0.000 58.275 0.040 58.380 ;
    RECT 0.000 58.415 0.040 58.520 ;
    RECT 0.000 58.555 0.040 58.660 ;
    RECT 0.000 58.695 0.040 58.800 ;
    RECT 0.000 58.835 0.040 58.940 ;
    RECT 0.000 58.975 0.040 59.080 ;
    RECT 0.000 59.115 0.040 59.220 ;
    RECT 0.000 59.255 0.040 59.360 ;
    RECT 0.000 59.395 0.040 59.500 ;
    RECT 0.000 59.535 0.040 59.640 ;
    RECT 0.000 59.675 0.040 59.780 ;
    RECT 0.000 59.815 0.040 59.920 ;
    RECT 0.000 59.955 0.040 60.060 ;
    RECT 0.000 60.095 0.040 60.200 ;
    RECT 0.000 60.235 0.040 60.340 ;
    RECT 0.000 60.375 0.040 60.480 ;
    RECT 0.000 60.515 0.040 60.620 ;
    RECT 0.000 60.655 0.040 60.760 ;
    RECT 0.000 60.795 0.040 60.900 ;
    RECT 0.000 60.935 0.040 61.040 ;
    RECT 0.000 61.075 0.040 61.180 ;
    RECT 0.000 61.215 0.040 61.320 ;
    RECT 0.000 61.355 0.040 61.460 ;
    RECT 0.000 61.495 0.040 61.600 ;
    RECT 0.000 61.635 0.040 61.740 ;
    RECT 0.000 61.775 0.040 61.880 ;
    RECT 0.000 61.915 0.040 62.020 ;
    RECT 0.000 62.055 0.040 62.160 ;
    RECT 0.000 62.195 0.040 62.300 ;
    RECT 0.000 62.335 0.040 62.440 ;
    RECT 0.000 62.475 0.040 62.580 ;
    RECT 0.000 62.615 0.040 62.720 ;
    RECT 0.000 62.755 0.040 62.860 ;
    RECT 0.000 62.895 0.040 63.000 ;
    RECT 0.000 63.035 0.040 63.140 ;
    RECT 0.000 63.175 0.040 63.280 ;
    RECT 0.000 63.315 0.040 63.420 ;
    RECT 0.000 63.455 0.040 63.560 ;
    RECT 0.000 63.595 0.040 63.700 ;
    RECT 0.000 63.735 0.040 63.840 ;
    RECT 0.000 63.875 0.040 63.980 ;
    RECT 0.000 64.015 0.040 64.120 ;
    RECT 0.000 64.155 0.040 64.260 ;
    RECT 0.000 64.295 0.040 64.400 ;
    RECT 0.000 64.435 0.040 64.540 ;
    RECT 0.000 64.575 0.040 64.680 ;
    RECT 0.000 64.715 0.040 64.820 ;
    RECT 0.000 64.855 0.040 64.960 ;
    RECT 0.000 64.995 0.040 65.100 ;
    RECT 0.000 65.135 0.040 65.240 ;
    RECT 0.000 65.275 0.040 65.380 ;
    RECT 0.000 65.415 0.040 65.520 ;
    RECT 0.000 65.555 0.040 65.660 ;
    RECT 0.000 65.695 0.040 65.800 ;
    RECT 0.000 65.835 0.040 65.940 ;
    RECT 0.000 65.975 0.040 66.080 ;
    RECT 0.000 66.115 0.040 66.220 ;
    RECT 0.000 66.255 0.040 66.360 ;
    RECT 0.000 66.395 0.040 66.500 ;
    RECT 0.000 66.535 0.040 66.640 ;
    RECT 0.000 66.675 0.040 66.780 ;
    RECT 0.000 66.815 0.040 66.920 ;
    RECT 0.000 66.955 0.040 67.060 ;
    RECT 0.000 67.095 0.040 67.200 ;
    RECT 0.000 67.235 0.040 67.340 ;
    RECT 0.000 67.375 0.040 67.480 ;
    RECT 0.000 67.515 0.040 67.620 ;
    RECT 0.000 67.655 0.040 67.760 ;
    RECT 0.000 67.795 0.040 67.900 ;
    RECT 0.000 67.935 0.040 68.040 ;
    RECT 0.000 68.075 0.040 68.180 ;
    RECT 0.000 68.215 0.040 68.320 ;
    RECT 0.000 68.355 0.040 68.460 ;
    RECT 0.000 68.495 0.040 68.600 ;
    RECT 0.000 68.635 0.040 68.740 ;
    RECT 0.000 68.775 0.040 68.880 ;
    RECT 0.000 68.915 0.040 69.020 ;
    RECT 0.000 69.055 0.040 69.160 ;
    RECT 0.000 69.195 0.040 69.300 ;
    RECT 0.000 69.335 0.040 69.440 ;
    RECT 0.000 69.475 0.040 69.580 ;
    RECT 0.000 69.615 0.040 69.720 ;
    RECT 0.000 69.755 0.040 69.860 ;
    RECT 0.000 69.895 0.040 70.000 ;
    RECT 0.000 70.035 0.040 70.140 ;
    RECT 0.000 70.175 0.040 70.280 ;
    RECT 0.000 70.315 0.040 70.420 ;
    RECT 0.000 70.455 0.040 70.560 ;
    RECT 0.000 70.595 0.040 70.700 ;
    RECT 0.000 70.735 0.040 70.840 ;
    RECT 0.000 70.875 0.040 70.980 ;
    RECT 0.000 71.015 0.040 71.120 ;
    RECT 0.000 71.155 0.040 71.260 ;
    RECT 0.000 71.295 0.040 71.400 ;
    RECT 0.000 71.435 0.040 71.540 ;
    RECT 0.000 71.575 0.040 71.680 ;
    RECT 0.000 71.715 0.040 71.820 ;
    RECT 0.000 71.855 0.040 71.960 ;
    RECT 0.000 71.995 0.040 72.100 ;
    RECT 0.000 72.135 0.040 72.240 ;
    RECT 0.000 72.275 0.040 72.380 ;
    RECT 0.000 72.415 0.040 72.520 ;
    RECT 0.000 72.555 0.040 72.660 ;
    RECT 0.000 72.695 0.040 72.800 ;
    RECT 0.000 72.835 0.040 72.940 ;
    RECT 0.000 72.975 0.040 73.080 ;
    RECT 0.000 73.115 0.040 73.220 ;
    RECT 0.000 73.255 0.040 73.360 ;
    RECT 0.000 73.395 0.040 73.500 ;
    RECT 0.000 73.535 0.040 73.640 ;
    RECT 0.000 73.675 0.040 73.780 ;
    RECT 0.000 73.815 0.040 73.920 ;
    RECT 0.000 73.955 0.040 74.060 ;
    RECT 0.000 74.095 0.040 74.200 ;
    RECT 0.000 74.235 0.040 74.340 ;
    RECT 0.000 74.375 0.040 74.480 ;
    RECT 0.000 74.515 0.040 74.620 ;
    RECT 0.000 74.655 0.040 74.760 ;
    RECT 0.000 74.795 0.040 74.900 ;
    RECT 0.000 74.935 0.040 75.040 ;
    RECT 0.000 75.075 0.040 75.180 ;
    RECT 0.000 75.215 0.040 75.320 ;
    RECT 0.000 75.355 0.040 75.460 ;
    RECT 0.000 75.495 0.040 75.600 ;
    RECT 0.000 75.635 0.040 75.740 ;
    RECT 0.000 75.775 0.040 75.880 ;
    RECT 0.000 75.915 0.040 76.020 ;
    RECT 0.000 76.055 0.040 76.160 ;
    RECT 0.000 76.195 0.040 76.300 ;
    RECT 0.000 76.335 0.040 76.440 ;
    RECT 0.000 76.475 0.040 76.580 ;
    RECT 0.000 76.615 0.040 76.720 ;
    RECT 0.000 76.755 0.040 76.860 ;
    RECT 0.000 76.895 0.040 77.000 ;
    RECT 0.000 77.035 0.040 77.140 ;
    RECT 0.000 77.175 0.040 77.280 ;
    RECT 0.000 77.315 0.040 77.420 ;
    RECT 0.000 77.455 0.040 77.560 ;
    RECT 0.000 77.595 0.040 77.700 ;
    RECT 0.000 77.735 0.040 77.840 ;
    RECT 0.000 77.875 0.040 77.980 ;
    RECT 0.000 78.015 0.040 78.120 ;
    RECT 0.000 78.155 0.040 78.260 ;
    RECT 0.000 78.295 0.040 78.400 ;
    RECT 0.000 78.435 0.040 78.540 ;
    RECT 0.000 78.575 0.040 78.680 ;
    RECT 0.000 78.715 0.040 78.820 ;
    RECT 0.000 78.855 0.040 78.960 ;
    RECT 0.000 78.995 0.040 79.100 ;
    RECT 0.000 79.135 0.040 79.240 ;
    RECT 0.000 79.275 0.040 79.380 ;
    RECT 0.000 79.415 0.040 79.520 ;
    RECT 0.000 79.555 0.040 79.660 ;
    RECT 0.000 79.695 0.040 79.800 ;
    RECT 0.000 79.835 0.040 79.940 ;
    RECT 0.000 79.975 0.040 80.080 ;
    RECT 0.000 80.115 0.040 80.220 ;
    RECT 0.000 80.255 0.040 80.360 ;
    RECT 0.000 80.395 0.040 80.500 ;
    RECT 0.000 80.535 0.040 80.640 ;
    RECT 0.000 80.675 0.040 80.780 ;
    RECT 0.000 80.815 0.040 80.920 ;
    RECT 0.000 80.955 0.040 81.060 ;
    RECT 0.000 81.095 0.040 81.200 ;
    RECT 0.000 81.235 0.040 81.340 ;
    RECT 0.000 81.375 0.040 81.480 ;
    RECT 0.000 81.515 0.040 81.620 ;
    RECT 0.000 81.655 0.040 81.760 ;
    RECT 0.000 81.795 0.040 81.900 ;
    RECT 0.000 81.935 0.040 82.040 ;
    RECT 0.000 82.075 0.040 82.180 ;
    RECT 0.000 82.215 0.040 82.320 ;
    RECT 0.000 82.355 0.040 82.460 ;
    RECT 0.000 82.495 0.040 82.600 ;
    RECT 0.000 82.635 0.040 82.740 ;
    RECT 0.000 82.775 0.040 82.880 ;
    RECT 0.000 82.915 0.040 83.020 ;
    RECT 0.000 83.055 0.040 83.160 ;
    RECT 0.000 83.195 0.040 83.300 ;
    RECT 0.000 83.335 0.040 83.440 ;
    RECT 0.000 83.475 0.040 83.580 ;
    RECT 0.000 83.615 0.040 83.720 ;
    RECT 0.000 83.755 0.040 83.860 ;
    RECT 0.000 83.895 0.040 84.000 ;
    RECT 0.000 84.035 0.040 84.140 ;
    RECT 0.000 84.175 0.040 84.280 ;
    RECT 0.000 84.315 0.040 84.420 ;
    RECT 0.000 84.455 0.040 84.560 ;
    RECT 0.000 84.595 0.040 84.700 ;
    RECT 0.000 84.735 0.040 84.840 ;
    RECT 0.000 84.875 0.040 84.980 ;
    RECT 0.000 85.015 0.040 85.120 ;
    RECT 0.000 85.155 0.040 85.260 ;
    RECT 0.000 85.295 0.040 85.400 ;
    RECT 0.000 85.435 0.040 85.540 ;
    RECT 0.000 85.575 0.040 85.680 ;
    RECT 0.000 85.715 0.040 85.820 ;
    RECT 0.000 85.855 0.040 85.960 ;
    RECT 0.000 85.995 0.040 86.100 ;
    RECT 0.000 86.135 0.040 86.240 ;
    RECT 0.000 86.275 0.040 86.380 ;
    RECT 0.000 86.415 0.040 86.520 ;
    RECT 0.000 86.555 0.040 86.660 ;
    RECT 0.000 86.695 0.040 86.800 ;
    RECT 0.000 86.835 0.040 86.940 ;
    RECT 0.000 86.975 0.040 87.080 ;
    RECT 0.000 87.115 0.040 87.220 ;
    RECT 0.000 87.255 0.040 87.360 ;
    RECT 0.000 87.395 0.040 87.500 ;
    RECT 0.000 87.535 0.040 87.640 ;
    RECT 0.000 87.675 0.040 87.780 ;
    RECT 0.000 87.815 0.040 87.920 ;
    RECT 0.000 87.955 0.040 88.060 ;
    RECT 0.000 88.095 0.040 88.200 ;
    RECT 0.000 88.235 0.040 88.340 ;
    RECT 0.000 88.375 0.040 88.480 ;
    RECT 0.000 88.515 0.040 88.620 ;
    RECT 0.000 88.655 0.040 88.760 ;
    RECT 0.000 88.795 0.040 88.900 ;
    RECT 0.000 88.935 0.040 89.040 ;
    RECT 0.000 89.075 0.040 89.180 ;
    RECT 0.000 89.215 0.040 89.320 ;
    RECT 0.000 89.355 0.040 89.460 ;
    RECT 0.000 89.495 0.040 89.600 ;
    RECT 0.000 89.635 0.040 89.740 ;
    RECT 0.000 89.775 0.040 89.880 ;
    RECT 0.000 89.915 0.040 90.020 ;
    RECT 0.000 90.055 0.040 90.160 ;
    RECT 0.000 90.195 0.040 90.300 ;
    RECT 0.000 90.335 0.040 90.440 ;
    RECT 0.000 90.475 0.040 90.580 ;
    RECT 0.000 90.615 0.040 90.720 ;
    RECT 0.000 90.755 0.040 90.860 ;
    RECT 0.000 90.895 0.040 91.000 ;
    RECT 0.000 91.035 0.040 91.140 ;
    RECT 0.000 91.175 0.040 91.280 ;
    RECT 0.000 91.315 0.040 91.420 ;
    RECT 0.000 91.455 0.040 91.560 ;
    RECT 0.000 91.595 0.040 91.700 ;
    RECT 0.000 91.735 0.040 91.840 ;
    RECT 0.000 91.875 0.040 91.980 ;
    RECT 0.000 92.015 0.040 92.120 ;
    RECT 0.000 92.155 0.040 92.260 ;
    RECT 0.000 92.295 0.040 92.400 ;
    RECT 0.000 92.435 0.040 92.540 ;
    RECT 0.000 92.575 0.040 92.680 ;
    RECT 0.000 92.715 0.040 92.820 ;
    RECT 0.000 92.855 0.040 92.960 ;
    RECT 0.000 92.995 0.040 93.100 ;
    RECT 0.000 93.135 0.040 93.240 ;
    RECT 0.000 93.275 0.040 93.380 ;
    RECT 0.000 93.415 0.040 93.520 ;
    RECT 0.000 93.555 0.040 93.660 ;
    RECT 0.000 93.695 0.040 93.800 ;
    RECT 0.000 93.835 0.040 93.940 ;
    RECT 0.000 93.975 0.040 94.080 ;
    RECT 0.000 94.115 0.040 94.220 ;
    RECT 0.000 94.255 0.040 94.360 ;
    RECT 0.000 94.395 0.040 94.500 ;
    RECT 0.000 94.535 0.040 94.640 ;
    RECT 0.000 94.675 0.040 94.780 ;
    RECT 0.000 94.815 0.040 94.920 ;
    RECT 0.000 94.955 0.040 95.060 ;
    RECT 0.000 95.095 0.040 95.200 ;
    RECT 0.000 95.235 0.040 95.340 ;
    RECT 0.000 95.375 0.040 95.480 ;
    RECT 0.000 95.515 0.040 95.620 ;
    RECT 0.000 95.655 0.040 95.760 ;
    RECT 0.000 95.795 0.040 95.900 ;
    RECT 0.000 95.935 0.040 96.040 ;
    RECT 0.000 96.075 0.040 96.180 ;
    RECT 0.000 96.215 0.040 96.320 ;
    RECT 0.000 96.355 0.040 96.460 ;
    RECT 0.000 96.495 0.040 96.600 ;
    RECT 0.000 96.635 0.040 96.740 ;
    RECT 0.000 96.775 0.040 96.880 ;
    RECT 0.000 96.915 0.040 97.020 ;
    RECT 0.000 97.055 0.040 97.160 ;
    RECT 0.000 97.195 0.040 97.300 ;
    RECT 0.000 97.335 0.040 97.440 ;
    RECT 0.000 97.475 0.040 97.580 ;
    RECT 0.000 97.615 0.040 97.720 ;
    RECT 0.000 97.755 0.040 97.860 ;
    RECT 0.000 97.895 0.040 98.000 ;
    RECT 0.000 98.035 0.040 98.140 ;
    RECT 0.000 98.175 0.040 98.280 ;
    RECT 0.000 98.315 0.040 98.420 ;
    RECT 0.000 98.455 0.040 98.560 ;
    RECT 0.000 98.595 0.040 98.700 ;
    RECT 0.000 98.735 0.040 98.840 ;
    RECT 0.000 98.875 0.040 98.980 ;
    RECT 0.000 99.015 0.040 99.120 ;
    RECT 0.000 99.155 0.040 99.260 ;
    RECT 0.000 99.295 0.040 99.400 ;
    RECT 0.000 99.435 0.040 99.540 ;
    RECT 0.000 99.575 0.040 99.680 ;
    RECT 0.000 99.715 0.040 99.820 ;
    RECT 0.000 99.855 0.040 99.960 ;
    RECT 0.000 99.995 0.040 100.100 ;
    RECT 0.000 100.135 0.040 100.240 ;
    RECT 0.000 100.275 0.040 100.380 ;
    RECT 0.000 100.415 0.040 100.520 ;
    RECT 0.000 100.555 0.040 100.660 ;
    RECT 0.000 100.695 0.040 100.800 ;
    RECT 0.000 100.835 0.040 100.940 ;
    RECT 0.000 100.975 0.040 101.080 ;
    RECT 0.000 101.115 0.040 101.220 ;
    RECT 0.000 101.255 0.040 101.360 ;
    RECT 0.000 101.395 0.040 101.500 ;
    RECT 0.000 101.535 0.040 101.640 ;
    RECT 0.000 101.675 0.040 101.780 ;
    RECT 0.000 101.815 0.040 101.920 ;
    RECT 0.000 101.955 0.040 102.060 ;
    RECT 0.000 102.095 0.040 102.200 ;
    RECT 0.000 102.235 0.040 102.340 ;
    RECT 0.000 102.375 0.040 102.480 ;
    RECT 0.000 102.515 0.040 102.620 ;
    RECT 0.000 102.655 0.040 102.760 ;
    RECT 0.000 102.795 0.040 102.900 ;
    RECT 0.000 102.935 0.040 103.040 ;
    RECT 0.000 103.075 0.040 103.180 ;
    RECT 0.000 103.215 0.040 103.320 ;
    RECT 0.000 103.355 0.040 103.460 ;
    RECT 0.000 103.495 0.040 103.600 ;
    RECT 0.000 103.635 0.040 103.740 ;
    RECT 0.000 103.775 0.040 103.880 ;
    RECT 0.000 103.915 0.040 104.020 ;
    RECT 0.000 104.055 0.040 104.160 ;
    RECT 0.000 104.195 0.040 104.300 ;
    RECT 0.000 104.335 0.040 104.440 ;
    RECT 0.000 104.475 0.040 104.580 ;
    RECT 0.000 104.615 0.040 104.720 ;
    RECT 0.000 104.755 0.040 104.860 ;
    RECT 0.000 104.895 0.040 105.000 ;
    RECT 0.000 105.035 0.040 105.140 ;
    RECT 0.000 105.175 0.040 105.280 ;
    RECT 0.000 105.315 0.040 105.420 ;
    RECT 0.000 105.455 0.040 105.560 ;
    RECT 0.000 105.595 0.040 105.700 ;
    RECT 0.000 105.735 0.040 105.840 ;
    RECT 0.000 105.875 0.040 105.980 ;
    RECT 0.000 106.015 0.040 106.120 ;
    RECT 0.000 106.155 0.040 106.260 ;
    RECT 0.000 106.295 0.040 106.400 ;
    RECT 0.000 106.435 0.040 106.540 ;
    RECT 0.000 106.575 0.040 106.680 ;
    RECT 0.000 106.715 0.040 106.820 ;
    RECT 0.000 106.855 0.040 106.960 ;
    RECT 0.000 106.995 0.040 107.100 ;
    RECT 0.000 107.135 0.040 107.240 ;
    RECT 0.000 107.275 0.040 107.380 ;
    RECT 0.000 107.415 0.040 107.520 ;
    RECT 0.000 107.555 0.040 107.660 ;
    RECT 0.000 107.695 0.040 107.800 ;
    RECT 0.000 107.835 0.040 107.940 ;
    RECT 0.000 107.975 0.040 108.080 ;
    RECT 0.000 108.115 0.040 108.220 ;
    RECT 0.000 108.255 0.040 108.360 ;
    RECT 0.000 108.395 0.040 108.500 ;
    RECT 0.000 108.535 0.040 108.640 ;
    RECT 0.000 108.675 0.040 108.780 ;
    RECT 0.000 108.815 0.040 108.920 ;
    RECT 0.000 108.955 0.040 109.060 ;
    RECT 0.000 109.095 0.040 109.200 ;
    RECT 0.000 109.235 0.040 109.340 ;
    RECT 0.000 109.375 0.040 109.480 ;
    RECT 0.000 109.515 0.040 109.620 ;
    RECT 0.000 109.655 0.040 109.760 ;
    RECT 0.000 109.795 0.040 109.900 ;
    RECT 0.000 109.935 0.040 110.040 ;
    RECT 0.000 110.075 0.040 110.180 ;
    RECT 0.000 110.215 0.040 111.950 ;
    LAYER metal4 ;
    RECT 0.000 0.000 87.192 1.400 ;
    RECT 0.000 110.550 87.192 111.950 ;
    RECT 0.000 1.400 1.528 110.550 ;
    RECT 1.689 1.400 2.814 110.550 ;
    RECT 2.975 1.400 4.101 110.550 ;
    RECT 4.262 1.400 5.387 110.550 ;
    RECT 5.548 1.400 6.674 110.550 ;
    RECT 6.835 1.400 7.960 110.550 ;
    RECT 8.121 1.400 9.247 110.550 ;
    RECT 9.408 1.400 10.534 110.550 ;
    RECT 10.694 1.400 11.820 110.550 ;
    RECT 11.981 1.400 13.107 110.550 ;
    RECT 13.267 1.400 14.393 110.550 ;
    RECT 14.554 1.400 15.680 110.550 ;
    RECT 15.841 1.400 16.966 110.550 ;
    RECT 17.127 1.400 18.253 110.550 ;
    RECT 18.414 1.400 19.539 110.550 ;
    RECT 19.700 1.400 20.826 110.550 ;
    RECT 20.987 1.400 22.112 110.550 ;
    RECT 22.273 1.400 23.399 110.550 ;
    RECT 23.560 1.400 24.686 110.550 ;
    RECT 24.846 1.400 25.972 110.550 ;
    RECT 26.133 1.400 27.259 110.550 ;
    RECT 27.419 1.400 28.545 110.550 ;
    RECT 28.706 1.400 29.832 110.550 ;
    RECT 29.993 1.400 31.118 110.550 ;
    RECT 31.279 1.400 32.405 110.550 ;
    RECT 32.566 1.400 33.691 110.550 ;
    RECT 33.852 1.400 34.978 110.550 ;
    RECT 35.139 1.400 36.264 110.550 ;
    RECT 36.425 1.400 37.551 110.550 ;
    RECT 37.712 1.400 38.837 110.550 ;
    RECT 38.998 1.400 40.124 110.550 ;
    RECT 40.285 1.400 41.411 110.550 ;
    RECT 41.571 1.400 42.697 110.550 ;
    RECT 42.858 1.400 43.984 110.550 ;
    RECT 44.144 1.400 45.270 110.550 ;
    RECT 45.431 1.400 46.557 110.550 ;
    RECT 46.718 1.400 47.843 110.550 ;
    RECT 48.004 1.400 49.130 110.550 ;
    RECT 49.291 1.400 50.416 110.550 ;
    RECT 50.577 1.400 51.703 110.550 ;
    RECT 51.864 1.400 52.989 110.550 ;
    RECT 53.150 1.400 54.276 110.550 ;
    RECT 54.437 1.400 55.563 110.550 ;
    RECT 55.723 1.400 56.849 110.550 ;
    RECT 57.010 1.400 58.136 110.550 ;
    RECT 58.296 1.400 59.422 110.550 ;
    RECT 59.583 1.400 60.709 110.550 ;
    RECT 60.870 1.400 61.995 110.550 ;
    RECT 62.156 1.400 63.282 110.550 ;
    RECT 63.443 1.400 64.568 110.550 ;
    RECT 64.729 1.400 65.855 110.550 ;
    RECT 66.016 1.400 67.141 110.550 ;
    RECT 67.302 1.400 68.428 110.550 ;
    RECT 68.589 1.400 69.715 110.550 ;
    RECT 69.875 1.400 71.001 110.550 ;
    RECT 71.162 1.400 72.288 110.550 ;
    RECT 72.448 1.400 73.574 110.550 ;
    RECT 73.735 1.400 74.861 110.550 ;
    RECT 75.021 1.400 76.147 110.550 ;
    RECT 76.308 1.400 77.434 110.550 ;
    RECT 77.595 1.400 78.720 110.550 ;
    RECT 78.881 1.400 80.007 110.550 ;
    RECT 80.168 1.400 81.293 110.550 ;
    RECT 81.454 1.400 82.580 110.550 ;
    RECT 82.741 1.400 83.866 110.550 ;
    RECT 84.027 1.400 85.153 110.550 ;
    RECT 85.314 1.400 87.192 110.550 ;
  END
END fakeram45_64x128

END LIBRARY
